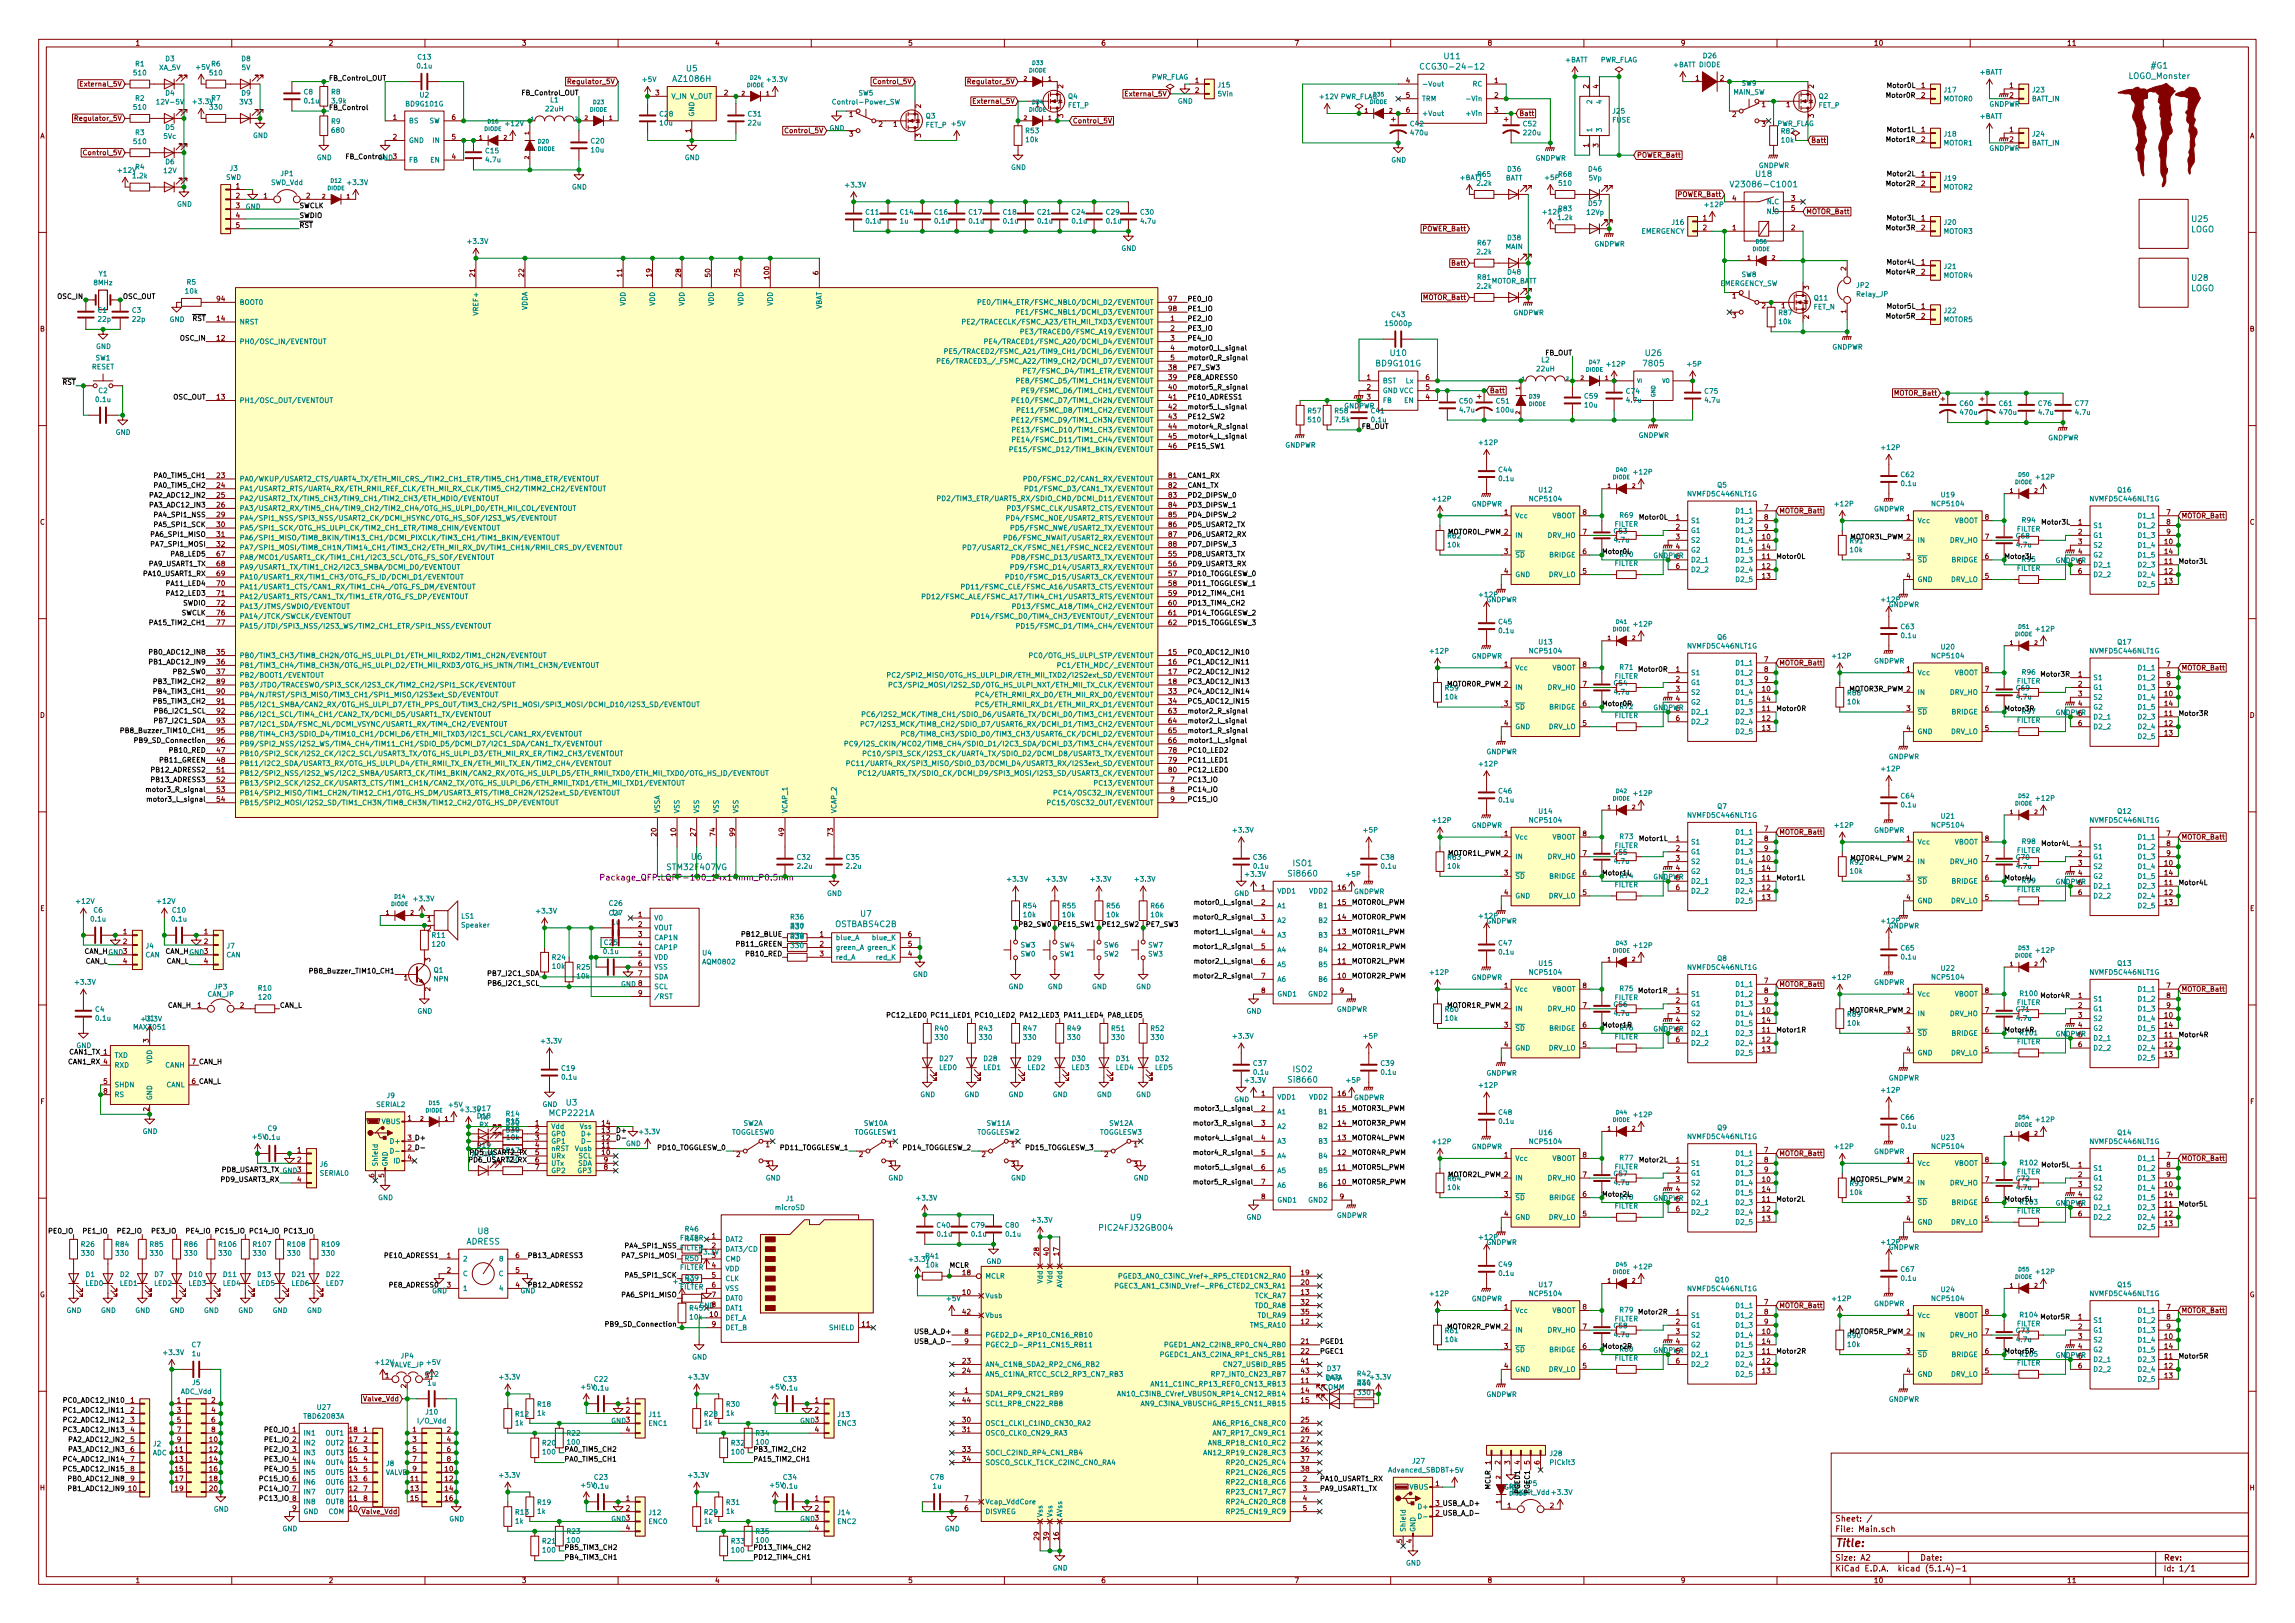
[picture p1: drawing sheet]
<svg xmlns="http://www.w3.org/2000/svg" width="594mm" height="420mm" viewBox="0 0 594 420" stroke-linecap="round" stroke-linejoin="round" font-family="sans-serif">
<defs><g id="words">
<text font-size="2.8" fill="#840000" x="475" y="400.4">Title:</text>
<g font-size="2.1" fill="#008484">
<text x="374" y="15.3">U11</text>
<text x="556.9" y="17.7">#G1</text>
<text x="174.5" y="21.2">AZ1086H</text>
<text x="177.7" y="18.5">U5</text>
<text x="369.3" y="18">CCG30-24-12</text>
<text x="551.1" y="20.4">LOGO_Monster</text>
<text x="454.6" y="45.8">U18</text>
<text x="449.4" y="48.5">V23086-C1001</text>
<text x="567.5" y="57.4">U25</text>
<text x="567.1" y="60.1">LOGO</text>
<text x="567.1" y="75.4">LOGO</text>
<text x="567.5" y="72.7">U28</text>
<text x="356.4" y="94.8">BD9G101G</text>
<text x="360" y="92.1">U10</text>
<text x="425.6" y="94.8">7805</text>
<text x="426.1" y="92.1">U26</text>
<text x="173" y="225.2">STM32F407VG</text>
<text x="179" y="222.5">U6</text>
<text x="333.8" y="226.9">Si8660</text>
<text x="334.8" y="224.2">ISO1</text>
<text x="216.3" y="240">OSTBABS4C2B</text>
<text x="222.8" y="237.3">U7</text>
<text x="333.8" y="280.3">Si8660</text>
<text x="334.8" y="277.6">ISO2</text>
<text x="146.6" y="286.2">U3</text>
<text x="142.5" y="288.9">MCP2221A</text>
<text x="292.7" y="315.9">U9</text>
<text x="120.7" y="322.2">ADRESS</text>
<text x="123.7" y="319.5">U8</text>
<text x="285.3" y="318.6">PIC24FJ32GB004</text>
</g>
<text font-size="2.1" fill="#008400" x="157.9" y="227.9">Package_QFP:LQFP-100_14x14mm_P0.5mm</text>
<g font-size="2.1" fill="#840000">
<text x="475" y="393.9">Sheet: /</text>
<text x="475" y="396.6">File: Main.sch</text>
<text x="475" y="406.8">KiCad E.D.A. kicad (5.1.4)-1</text>
<text x="475" y="404">Size: A2</text>
<text x="497" y="404">Date:</text>
<text x="560" y="404">Rev:</text>
<text x="560" y="406.8">Id: 1/1</text>
</g>
<g font-size="1.8" fill="#840000">
<text x="35" y="11.8">1</text>
<text x="85" y="11.8">2</text>
<text x="135" y="11.8">3</text>
<text x="185" y="11.8">4</text>
<text x="235" y="11.8">5</text>
<text x="285" y="11.8">6</text>
<text x="335" y="11.8">7</text>
<text x="385" y="11.8">8</text>
<text x="435" y="11.8">9</text>
<text x="485" y="11.8">10</text>
<text x="535" y="11.8">11</text>
<text x="21.5" y="22.4">External_5V</text>
<text x="147.8" y="21.8">Regulator_5V</text>
<text x="226.6" y="21.8">Control_5V</text>
<text x="251.3" y="21.8">Regulator_5V</text>
<text x="275.2" y="22.9" transform="rotate(-90 275.2 22.9)">2</text>
<text x="309.4" y="21.5">1</text>
<text x="364" y="21.5">4</text>
<text x="386.9" y="21.5">1</text>
<text x="411.2" y="22.9" transform="rotate(-90 411.2 22.9)">2</text>
<text x="413.8" y="22.9" transform="rotate(-90 413.8 22.9)">4</text>
<text x="438.9" y="20.9">1</text>
<text x="445.3" y="20.9">2</text>
<text x="469.5" y="22.9" transform="rotate(-90 469.5 22.9)">2</text>
<text x="497.4" y="22.8">1</text>
<text x="520.2" y="22.8">1</text>
<text x="169.7" y="24.7">3</text>
<text x="187.5" y="24.7">2</text>
<text x="238.4" y="28" transform="rotate(-90 238.4 28)">2</text>
<text x="252.6" y="26.8">External_5V</text>
<text x="292" y="24.9">External_5V</text>
<text x="309.4" y="24">2</text>
<text x="364" y="25.3">5</text>
<text x="364" y="29.1">6</text>
<text x="386.9" y="25.3">2</text>
<text x="386.9" y="29.1">3</text>
<text x="456.1" y="27.7">1</text>
<text x="462.4" y="27.7">1</text>
<text x="497.4" y="25.3">2</text>
<text x="520.2" y="25.3">2</text>
<text x="10.4" y="35.8">A</text>
<text x="20.2" y="31.3">Regulator_5V</text>
<text x="101.8" y="31">1</text>
<text x="117" y="31">6</text>
<text x="178.8" y="34.3" transform="rotate(-90 178.8 34.3)">1</text>
<text x="203.8" y="34.5">Control_5V</text>
<text x="219.9" y="30.3">1</text>
<text x="219.9" y="35.3">3</text>
<text x="227.5" y="32.8">2</text>
<text x="231.3" y="32.8">1</text>
<text x="238.4" y="35.6" transform="rotate(-90 238.4 35.6)">3</text>
<text x="275.2" y="30.5" transform="rotate(-90 275.2 30.5)">3</text>
<text x="277.6" y="31.9">Control_5V</text>
<text x="393.2" y="30">Batt</text>
<text x="448.5" y="30.3">2</text>
<text x="456.1" y="32.8">3</text>
<text x="469.5" y="30.5" transform="rotate(-90 469.5 30.5)">3</text>
<text x="497.4" y="34.2">1</text>
<text x="520.2" y="34.2">1</text>
<text x="582.4" y="35.8">A</text>
<text x="22.2" y="40.2">Control_5V</text>
<text x="101.8" y="36.1">2</text>
<text x="117" y="41.2">4</text>
<text x="117" y="36.1">5</text>
<text x="411.2" y="38.1" transform="rotate(-90 411.2 38.1)">1</text>
<text x="413.8" y="38.1" transform="rotate(-90 413.8 38.1)">3</text>
<text x="423.7" y="40.8">POWER_Batt</text>
<text x="468.8" y="37">Batt</text>
<text x="497.4" y="36.7">2</text>
<text x="520.2" y="36.7">2</text>
<text x="497.4" y="45.6">1</text>
<text x="61.1" y="48.8">1</text>
<text x="61.1" y="51.4">2</text>
<text x="61.1" y="53.9">3</text>
<text x="68.3" y="51.4">1</text>
<text x="79.3" y="51.4">2</text>
<text x="434.5" y="51">POWER_Batt</text>
<text x="448.5" y="52">4</text>
<text x="463.7" y="52">3</text>
<text x="497.4" y="48.2">2</text>
<text x="61.1" y="56.4">4</text>
<text x="61.1" y="59">5</text>
<text x="368.5" y="59.9">POWER_Batt</text>
<text x="440.8" y="57.1">1</text>
<text x="440.8" y="59.6">2</text>
<text x="448.5" y="59.6">1</text>
<text x="463.7" y="59.6">2</text>
<text x="463.7" y="54.5">5</text>
<text x="467.5" y="55.4">MOTOR_Batt</text>
<text x="497.4" y="57.1">1</text>
<text x="497.4" y="59.6">2</text>
<text x="122.9" y="71.6" transform="rotate(-90 122.9 71.6)">21</text>
<text x="135.6" y="71.6" transform="rotate(-90 135.6 71.6)">22</text>
<text x="161" y="71.6" transform="rotate(-90 161 71.6)">11</text>
<text x="168.7" y="71.6" transform="rotate(-90 168.7 71.6)">19</text>
<text x="176.3" y="71.6" transform="rotate(-90 176.3 71.6)">28</text>
<text x="183.9" y="71.6" transform="rotate(-90 183.9 71.6)">50</text>
<text x="191.5" y="71.6" transform="rotate(-90 191.5 71.6)">75</text>
<text x="211.8" y="71.1" transform="rotate(-90 211.8 71.1)">6</text>
<text x="376.1" y="68.7">Batt</text>
<text x="477.9" y="70" transform="rotate(-90 477.9 70)">2</text>
<text x="497.4" y="68.5">1</text>
<text x="497.4" y="71">2</text>
<text x="199.1" y="72.1" transform="rotate(-90 199.1 72.1)">100</text>
<text x="368.6" y="77.6">MOTOR_Batt</text>
<text x="448.5" y="77.3">1</text>
<text x="468.2" y="74.9" transform="rotate(-90 468.2 74.9)">3</text>
<text x="56.2" y="83.1">14</text>
<text x="56.2" y="78">94</text>
<text x="302.6" y="78">97</text>
<text x="302.6" y="80.6">98</text>
<text x="303" y="83.1">1</text>
<text x="448.5" y="82.3">3</text>
<text x="456.1" y="79.8">2</text>
<text x="461.2" y="79.8">1</text>
<text x="468.2" y="82.6" transform="rotate(-90 468.2 82.6)">2</text>
<text x="477.9" y="81.1" transform="rotate(-90 477.9 81.1)">1</text>
<text x="497.4" y="79.9">1</text>
<text x="497.4" y="82.5">2</text>
<text x="10.4" y="85.8">B</text>
<text x="56.2" y="88.2">12</text>
<text x="303" y="85.6">2</text>
<text x="303" y="88.2">3</text>
<text x="582.4" y="85.8">B</text>
<text x="302.6" y="95.8">38</text>
<text x="303" y="90.7">4</text>
<text x="303" y="93.3">5</text>
<text x="302.6" y="98.3">39</text>
<text x="302.6" y="100.9">40</text>
<text x="353.8" y="98.3">1</text>
<text x="353.8" y="100.9">2</text>
<text x="369.1" y="100.9">5</text>
<text x="369.1" y="98.3">6</text>
<text x="385.6" y="101.8">Batt</text>
<text x="56.2" y="103.4">13</text>
<text x="302.6" y="103.4">41</text>
<text x="302.6" y="106">42</text>
<text x="353.8" y="103.4">3</text>
<text x="369.1" y="103.4">4</text>
<text x="490.5" y="102.4">MOTOR_Batt</text>
<text x="302.6" y="108.5">43</text>
<text x="302.6" y="111">44</text>
<text x="302.6" y="113.6">45</text>
<text x="302.6" y="116.1">46</text>
<text x="56.2" y="123.7">23</text>
<text x="302.6" y="123.7">81</text>
<text x="56.2" y="126.3">24</text>
<text x="56.2" y="128.8">25</text>
<text x="56.2" y="131.4">26</text>
<text x="302.6" y="126.3">82</text>
<text x="302.6" y="128.8">83</text>
<text x="302.6" y="131.4">84</text>
<text x="456.7" y="132">7</text>
<text x="10.4" y="135.8">C</text>
<text x="56.2" y="133.9">29</text>
<text x="56.2" y="136.4">30</text>
<text x="302.6" y="133.9">85</text>
<text x="302.6" y="136.4">86</text>
<text x="389.4" y="133.3">1</text>
<text x="409.7" y="133.3">8</text>
<text x="433.9" y="134.5">1</text>
<text x="433.9" y="137.1">2</text>
<text x="456.7" y="134.5">8</text>
<text x="456.7" y="137.1">9</text>
<text x="460.5" y="132.9">MOTOR_Batt</text>
<text x="493.5" y="134.5">1</text>
<text x="513.9" y="134.5">8</text>
<text x="538" y="135.8">1</text>
<text x="560.9" y="133.3">7</text>
<text x="560.9" y="135.8">8</text>
<text x="564.7" y="134.2">MOTOR_Batt</text>
<text x="582.4" y="135.8">C</text>
<text x="56.2" y="139">31</text>
<text x="56.2" y="141.5">32</text>
<text x="302.6" y="139">87</text>
<text x="302.6" y="141.5">88</text>
<text x="389.4" y="143.4">3</text>
<text x="409.7" y="143.4">6</text>
<text x="409.7" y="138.3">7</text>
<text x="433.9" y="139.6">3</text>
<text x="433.9" y="142.2">4</text>
<text x="456.2" y="139.6">10</text>
<text x="456.2" y="142.2">14</text>
<text x="513.9" y="139.6">7</text>
<text x="538" y="138.3">2</text>
<text x="538" y="140.9">3</text>
<text x="538" y="143.4">4</text>
<text x="560.4" y="140.9">10</text>
<text x="560.4" y="143.4">14</text>
<text x="560.9" y="138.3">9</text>
<text x="56.2" y="144.1">67</text>
<text x="56.2" y="146.6">68</text>
<text x="56.2" y="149.1">69</text>
<text x="302.6" y="144.1">55</text>
<text x="302.6" y="146.6">56</text>
<text x="302.6" y="149.1">57</text>
<text x="389.4" y="148.5">4</text>
<text x="409.7" y="148.5">5</text>
<text x="433.9" y="144.7">5</text>
<text x="433.9" y="147.2">6</text>
<text x="456.2" y="144.7">11</text>
<text x="456.2" y="147.2">12</text>
<text x="456.2" y="149.8">13</text>
<text x="493.5" y="144.7">3</text>
<text x="493.5" y="149.8">4</text>
<text x="513.9" y="149.8">5</text>
<text x="513.9" y="144.7">6</text>
<text x="538" y="146">5</text>
<text x="538" y="148.5">6</text>
<text x="560.4" y="146">11</text>
<text x="560.4" y="148.5">12</text>
<text x="56.2" y="151.7">70</text>
<text x="56.2" y="154.2">71</text>
<text x="302.6" y="151.7">58</text>
<text x="302.6" y="154.2">59</text>
<text x="560.4" y="151">13</text>
<text x="56.2" y="156.8">72</text>
<text x="56.2" y="159.3">76</text>
<text x="56.2" y="161.8">77</text>
<text x="302.6" y="156.8">60</text>
<text x="302.6" y="159.3">61</text>
<text x="302.6" y="161.8">62</text>
<text x="56.2" y="169.5">35</text>
<text x="56.2" y="172">36</text>
<text x="302.6" y="169.5">15</text>
<text x="302.6" y="172">16</text>
<text x="389.4" y="172.6">1</text>
<text x="409.7" y="172.6">8</text>
<text x="433.9" y="173.9">1</text>
<text x="456.7" y="171.4">7</text>
<text x="456.7" y="173.9">8</text>
<text x="460.5" y="172.3">MOTOR_Batt</text>
<text x="493.5" y="173.9">1</text>
<text x="513.9" y="173.9">8</text>
<text x="560.9" y="172.6">7</text>
<text x="564.7" y="173.5">MOTOR_Batt</text>
<text x="56.2" y="174.5">37</text>
<text x="56.2" y="177.1">89</text>
<text x="56.2" y="179.6">90</text>
<text x="302.6" y="174.5">17</text>
<text x="302.6" y="177.1">18</text>
<text x="302.6" y="179.6">33</text>
<text x="409.7" y="177.7">7</text>
<text x="433.9" y="176.4">2</text>
<text x="433.9" y="179">3</text>
<text x="456.2" y="179">10</text>
<text x="456.7" y="176.4">9</text>
<text x="513.9" y="179">7</text>
<text x="538" y="175.2">1</text>
<text x="538" y="177.7">2</text>
<text x="560.9" y="175.2">8</text>
<text x="560.9" y="177.7">9</text>
<text x="10.4" y="185.8">D</text>
<text x="56.2" y="182.2">91</text>
<text x="56.2" y="184.7">92</text>
<text x="302.6" y="182.2">34</text>
<text x="302.6" y="184.7">63</text>
<text x="389.4" y="182.8">3</text>
<text x="409.7" y="182.8">6</text>
<text x="433.9" y="181.5">4</text>
<text x="433.9" y="184.1">5</text>
<text x="456.2" y="184.1">11</text>
<text x="456.2" y="181.5">14</text>
<text x="493.5" y="184.1">3</text>
<text x="513.9" y="184.1">6</text>
<text x="538" y="180.3">3</text>
<text x="538" y="182.8">4</text>
<text x="538" y="185.3">5</text>
<text x="560.4" y="180.3">10</text>
<text x="560.4" y="185.3">11</text>
<text x="560.4" y="182.8">14</text>
<text x="582.4" y="185.8">D</text>
<text x="56.2" y="187.2">93</text>
<text x="56.2" y="189.8">95</text>
<text x="302.6" y="187.2">64</text>
<text x="302.6" y="189.8">65</text>
<text x="389.4" y="187.9">4</text>
<text x="409.7" y="187.9">5</text>
<text x="433.9" y="186.6">6</text>
<text x="456.2" y="186.6">12</text>
<text x="456.2" y="189.1">13</text>
<text x="493.5" y="189.1">4</text>
<text x="513.9" y="189.1">5</text>
<text x="538" y="187.9">6</text>
<text x="560.4" y="187.9">12</text>
<text x="560.4" y="190.4">13</text>
<text x="56.2" y="194.9">47</text>
<text x="56.2" y="197.4">48</text>
<text x="56.2" y="192.3">96</text>
<text x="302.6" y="192.3">66</text>
<text x="302.6" y="194.9">78</text>
<text x="302.6" y="197.4">79</text>
<text x="56.2" y="199.9">51</text>
<text x="56.2" y="202.5">52</text>
<text x="302.6" y="199.9">80</text>
<text x="303" y="202.5">7</text>
<text x="56.2" y="205">53</text>
<text x="56.2" y="207.6">54</text>
<text x="303" y="205">8</text>
<text x="303" y="207.6">9</text>
<text x="456.7" y="215.2">7</text>
<text x="169.9" y="216.4" transform="rotate(-90 169.9 216.4)">20</text>
<text x="175" y="216.4" transform="rotate(-90 175 216.4)">10</text>
<text x="180.1" y="216.4" transform="rotate(-90 180.1 216.4)">27</text>
<text x="185.2" y="216.4" transform="rotate(-90 185.2 216.4)">74</text>
<text x="190.2" y="216.4" transform="rotate(-90 190.2 216.4)">99</text>
<text x="202.9" y="216.4" transform="rotate(-90 202.9 216.4)">49</text>
<text x="215.6" y="216.4" transform="rotate(-90 215.6 216.4)">73</text>
<text x="389.4" y="216.5">1</text>
<text x="409.7" y="221.5">7</text>
<text x="409.7" y="216.5">8</text>
<text x="433.9" y="217.7">1</text>
<text x="433.9" y="220.3">2</text>
<text x="456.7" y="217.7">8</text>
<text x="456.7" y="220.3">9</text>
<text x="460.5" y="216.1">MOTOR_Batt</text>
<text x="493.5" y="217.7">1</text>
<text x="513.9" y="217.7">8</text>
<text x="538" y="219">1</text>
<text x="538" y="221.5">2</text>
<text x="560.9" y="216.5">7</text>
<text x="560.9" y="219">8</text>
<text x="560.9" y="221.5">9</text>
<text x="564.7" y="217.3">MOTOR_Batt</text>
<text x="389.4" y="226.6">3</text>
<text x="409.7" y="226.6">6</text>
<text x="433.9" y="222.8">3</text>
<text x="433.9" y="225.3">4</text>
<text x="433.9" y="227.9">5</text>
<text x="456.2" y="222.8">10</text>
<text x="456.2" y="227.9">11</text>
<text x="456.2" y="225.3">14</text>
<text x="493.5" y="227.9">3</text>
<text x="513.9" y="227.9">6</text>
<text x="513.9" y="222.8">7</text>
<text x="538" y="224.1">3</text>
<text x="538" y="226.6">4</text>
<text x="560.4" y="224.1">10</text>
<text x="560.4" y="226.6">14</text>
<text x="326.5" y="230.4">1</text>
<text x="346.4" y="230.4">16</text>
<text x="389.4" y="231.7">4</text>
<text x="409.7" y="231.7">5</text>
<text x="433.9" y="230.4">6</text>
<text x="456.2" y="230.4">12</text>
<text x="456.2" y="233">13</text>
<text x="493.5" y="233">4</text>
<text x="513.9" y="233">5</text>
<text x="538" y="229.2">5</text>
<text x="538" y="231.7">6</text>
<text x="560.4" y="229.2">11</text>
<text x="560.4" y="231.7">12</text>
<text x="10.4" y="235.8">E</text>
<text x="110.6" y="238.5">1</text>
<text x="165.3" y="237.4">1</text>
<text x="165.3" y="239.9">2</text>
<text x="326.5" y="234.2">2</text>
<text x="326.5" y="238">3</text>
<text x="346.4" y="238">14</text>
<text x="346.4" y="234.2">15</text>
<text x="560.4" y="234.2">13</text>
<text x="582.4" y="235.8">E</text>
<text x="31.9" y="241.9">1</text>
<text x="31.9" y="244.4">2</text>
<text x="52.9" y="241.9">1</text>
<text x="52.9" y="244.4">2</text>
<text x="110.6" y="241.1">2</text>
<text x="165.3" y="242.5">3</text>
<text x="165.3" y="245">4</text>
<text x="212.2" y="242.5">1</text>
<text x="212.2" y="245">2</text>
<text x="235.1" y="245">5</text>
<text x="235.1" y="242.5">6</text>
<text x="326.5" y="241.9">4</text>
<text x="326.5" y="245.7">5</text>
<text x="346.4" y="245.7">12</text>
<text x="346.4" y="241.9">13</text>
<text x="31.9" y="249.5">4</text>
<text x="52.9" y="249.5">4</text>
<text x="111.4" y="248.9" transform="rotate(-90 111.4 248.9)">3</text>
<text x="165.3" y="247.6">5</text>
<text x="165.3" y="250.1">6</text>
<text x="212.2" y="247.6">3</text>
<text x="235.1" y="247.6">4</text>
<text x="326.5" y="249.5">6</text>
<text x="346.4" y="249.5">11</text>
<text x="104.6" y="253.8">1</text>
<text x="111.4" y="256.6" transform="rotate(-90 111.4 256.6)">2</text>
<text x="160.7" y="255.4">GND 8</text>
<text x="165.3" y="252.6">7</text>
<text x="165.3" y="257.7">9</text>
<text x="326.5" y="253.3">7</text>
<text x="326.5" y="257.1">8</text>
<text x="346.4" y="253.3">10</text>
<text x="346.9" y="257.1">9</text>
<text x="389.4" y="255.8">1</text>
<text x="409.7" y="255.8">8</text>
<text x="433.9" y="257.1">1</text>
<text x="456.7" y="254.6">7</text>
<text x="456.7" y="257.1">8</text>
<text x="460.5" y="255.4">MOTOR_Batt</text>
<text x="493.5" y="257.1">1</text>
<text x="513.9" y="257.1">8</text>
<text x="560.9" y="255.8">7</text>
<text x="564.7" y="256.7">MOTOR_Batt</text>
<text x="51.1" y="260.9">1</text>
<text x="62.2" y="260.9">2</text>
<text x="409.7" y="260.9">7</text>
<text x="433.9" y="259.6">2</text>
<text x="433.9" y="262.2">3</text>
<text x="456.2" y="262.2">10</text>
<text x="456.7" y="259.6">9</text>
<text x="513.9" y="262.2">7</text>
<text x="538" y="258.4">1</text>
<text x="538" y="260.9">2</text>
<text x="538" y="263.4">3</text>
<text x="560.4" y="263.4">10</text>
<text x="560.9" y="258.4">8</text>
<text x="560.9" y="260.9">9</text>
<text x="34.8" y="266.5">MAX3051</text>
<text x="38.5" y="269.9" transform="rotate(-90 38.5 269.9)">3</text>
<text x="389.4" y="266">3</text>
<text x="409.7" y="266">6</text>
<text x="433.9" y="264.7">4</text>
<text x="433.9" y="267.3">5</text>
<text x="433.9" y="269.8">6</text>
<text x="456.2" y="267.3">11</text>
<text x="456.2" y="269.8">12</text>
<text x="456.2" y="264.7">14</text>
<text x="493.5" y="267.3">3</text>
<text x="513.9" y="267.3">6</text>
<text x="538" y="266">4</text>
<text x="538" y="268.5">5</text>
<text x="560.4" y="268.5">11</text>
<text x="560.4" y="266">14</text>
<text x="389.4" y="271.1">4</text>
<text x="409.7" y="271.1">5</text>
<text x="456.2" y="272.3">13</text>
<text x="493.5" y="272.3">4</text>
<text x="513.9" y="272.3">5</text>
<text x="538" y="271.1">6</text>
<text x="560.4" y="271.1">12</text>
<text x="560.4" y="273.6">13</text>
<text x="26.8" y="280.6">5</text>
<text x="10.5" y="285.8">F</text>
<text x="26.8" y="283.1">8</text>
<text x="38.5" y="287.7" transform="rotate(-90 38.5 287.7)">2</text>
<text x="326.5" y="283.8">1</text>
<text x="326.5" y="287.6">2</text>
<text x="346.4" y="287.6">15</text>
<text x="346.4" y="283.8">16</text>
<text x="582.5" y="285.8">F</text>
<text x="105.6" y="290.1">1</text>
<text x="138.6" y="291.4">1</text>
<text x="138.6" y="293.3">2</text>
<text x="155.9" y="293.3">13</text>
<text x="155.9" y="291.4">14</text>
<text x="326.5" y="291.4">3</text>
<text x="346.4" y="291.4">14</text>
<text x="77" y="298.4">1</text>
<text x="123.6" y="297.1">D19</text>
<text x="138.6" y="295.2">3</text>
<text x="138.6" y="297.1">4</text>
<text x="138.6" y="299">5</text>
<text x="155.9" y="299">10</text>
<text x="155.9" y="297.1">11</text>
<text x="155.9" y="295.2">12</text>
<text x="190.7" y="299.5">2</text>
<text x="198.3" y="297">1</text>
<text x="222.4" y="299.5">2</text>
<text x="230" y="297">1</text>
<text x="254.2" y="299.5">2</text>
<text x="261.8" y="297">1</text>
<text x="285.9" y="299.5">2</text>
<text x="293.5" y="297">1</text>
<text x="326.5" y="295.2">4</text>
<text x="326.5" y="299">5</text>
<text x="346.4" y="299">12</text>
<text x="346.4" y="295.2">13</text>
<text x="389.4" y="299.6">1</text>
<text x="409.7" y="299.6">8</text>
<text x="456.7" y="298.4">7</text>
<text x="460.5" y="299.3">MOTOR_Batt</text>
<text x="560.9" y="299.6">7</text>
<text x="77" y="300.9">2</text>
<text x="77" y="306">4</text>
<text x="96.9" y="304.8" transform="rotate(-90 96.9 304.8)">6</text>
<text x="99.4" y="304.8" transform="rotate(-90 99.4 304.8)">5</text>
<text x="105.6" y="300.3">4</text>
<text x="138.6" y="300.9">6</text>
<text x="138.6" y="302.8">7</text>
<text x="156.4" y="302.8">8</text>
<text x="156.4" y="300.9">9</text>
<text x="198.3" y="302">3</text>
<text x="230" y="302">3</text>
<text x="261.8" y="302">3</text>
<text x="293.5" y="302">3</text>
<text x="326.5" y="302.8">6</text>
<text x="346.4" y="302.8">11</text>
<text x="409.7" y="304.7">7</text>
<text x="433.9" y="300.9">1</text>
<text x="433.9" y="303.4">2</text>
<text x="433.9" y="306">3</text>
<text x="456.2" y="306">10</text>
<text x="456.7" y="300.9">8</text>
<text x="456.7" y="303.4">9</text>
<text x="493.5" y="300.9">1</text>
<text x="513.9" y="306">7</text>
<text x="513.9" y="300.9">8</text>
<text x="538" y="302.2">1</text>
<text x="538" y="304.7">2</text>
<text x="560.9" y="302.2">8</text>
<text x="560.9" y="304.7">9</text>
<text x="564.7" y="300.5">MOTOR_Batt</text>
<text x="326.5" y="306.6">7</text>
<text x="326.5" y="310.4">8</text>
<text x="346.4" y="306.6">10</text>
<text x="346.9" y="310.4">9</text>
<text x="389.4" y="309.8">3</text>
<text x="409.7" y="309.8">6</text>
<text x="433.9" y="308.5">4</text>
<text x="433.9" y="311.1">5</text>
<text x="456.2" y="311.1">11</text>
<text x="456.2" y="308.5">14</text>
<text x="493.5" y="311.1">3</text>
<text x="513.9" y="311.1">6</text>
<text x="538" y="307.3">3</text>
<text x="538" y="309.8">4</text>
<text x="560.4" y="307.3">10</text>
<text x="560.4" y="309.8">14</text>
<text x="389.4" y="314.9">4</text>
<text x="409.7" y="314.9">5</text>
<text x="433.9" y="313.6">6</text>
<text x="456.2" y="313.6">12</text>
<text x="456.2" y="316.1">13</text>
<text x="493.5" y="316.1">4</text>
<text x="513.9" y="316.1">5</text>
<text x="538" y="312.3">5</text>
<text x="538" y="314.9">6</text>
<text x="560.4" y="312.3">11</text>
<text x="560.4" y="314.9">12</text>
<text x="560.4" y="317.4">13</text>
<text x="184.3" y="320.6">1</text>
<text x="184.3" y="323.1">2</text>
<text x="115.7" y="325.7">1</text>
<text x="115.7" y="329.5">2</text>
<text x="133.5" y="329.5">5</text>
<text x="133.5" y="325.7">6</text>
<text x="184.3" y="325.7">3</text>
<text x="184.3" y="328.2">4</text>
<text x="269" y="325" transform="rotate(-90 269 325)">28</text>
<text x="271.5" y="325" transform="rotate(-90 271.5 325)">40</text>
<text x="274.1" y="325" transform="rotate(-90 274.1 325)">17</text>
<text x="10.3" y="335.8">G</text>
<text x="115.7" y="333.3">3</text>
<text x="133.5" y="333.3">4</text>
<text x="174.6" y="332.4">+3.3V</text>
<text x="184.3" y="330.8">5</text>
<text x="184.3" y="333.3">6</text>
<text x="184.3" y="335.8">7</text>
<text x="249.2" y="335.2">10</text>
<text x="249.2" y="330.1">18</text>
<text x="336.9" y="335.2">13</text>
<text x="336.9" y="330.1">19</text>
<text x="336.9" y="332.7">20</text>
<text x="582.3" y="335.8">G</text>
<text x="183.8" y="340.9">10</text>
<text x="249.2" y="340.3">42</text>
<text x="336.9" y="337.7">32</text>
<text x="336.9" y="340.3">35</text>
<text x="389.4" y="339">1</text>
<text x="409.7" y="339">8</text>
<text x="433.9" y="340.3">1</text>
<text x="456.7" y="337.7">7</text>
<text x="456.7" y="340.3">8</text>
<text x="460.5" y="338.6">MOTOR_Batt</text>
<text x="493.5" y="340.3">1</text>
<text x="513.9" y="340.3">8</text>
<text x="538" y="341.5">1</text>
<text x="560.9" y="339">7</text>
<text x="560.9" y="341.5">8</text>
<text x="564.7" y="339.9">MOTOR_Batt</text>
<text x="184.3" y="343.5">9</text>
<text x="223.2" y="343.5">11</text>
<text x="249.7" y="345.4">8</text>
<text x="249.7" y="347.9">9</text>
<text x="336.9" y="342.8">12</text>
<text x="336.9" y="347.9">21</text>
<text x="409.7" y="344.1">7</text>
<text x="433.9" y="342.8">2</text>
<text x="433.9" y="345.4">3</text>
<text x="433.9" y="347.9">4</text>
<text x="456.2" y="345.4">10</text>
<text x="456.2" y="347.9">14</text>
<text x="456.7" y="342.8">9</text>
<text x="513.9" y="345.4">7</text>
<text x="538" y="344.1">2</text>
<text x="538" y="346.6">3</text>
<text x="560.4" y="346.6">10</text>
<text x="560.9" y="344.1">9</text>
<text x="249.2" y="353">23</text>
<text x="336.9" y="350.4">22</text>
<text x="336.9" y="353">41</text>
<text x="389.4" y="349.2">3</text>
<text x="409.7" y="349.2">6</text>
<text x="433.9" y="350.4">5</text>
<text x="433.9" y="353">6</text>
<text x="456.2" y="350.4">11</text>
<text x="456.2" y="353">12</text>
<text x="493.5" y="350.4">3</text>
<text x="513.9" y="350.4">6</text>
<text x="538" y="349.2">4</text>
<text x="538" y="351.7">5</text>
<text x="560.4" y="351.7">11</text>
<text x="560.4" y="349.2">14</text>
<text x="99.8" y="356.8">1</text>
<text x="105.2" y="359.3" transform="rotate(-90 105.2 359.3)">2</text>
<text x="110.1" y="356.8">3</text>
<text x="249.2" y="355.5">24</text>
<text x="336.9" y="358.1">11</text>
<text x="336.9" y="355.5">43</text>
<text x="342.5" y="359.8">COMM</text>
<text x="389.4" y="354.2">4</text>
<text x="409.7" y="354.2">5</text>
<text x="456.2" y="355.5">13</text>
<text x="493.5" y="355.5">4</text>
<text x="513.9" y="355.5">5</text>
<text x="538" y="354.2">6</text>
<text x="560.4" y="354.2">12</text>
<text x="560.4" y="356.8">13</text>
<text x="33.8" y="363.1">1</text>
<text x="33.8" y="365.7">2</text>
<text x="45.9" y="363.1">1</text>
<text x="45.9" y="365.7">3</text>
<text x="54.8" y="363.1">2</text>
<text x="54.8" y="365.7">4</text>
<text x="94.4" y="362.8">Valve_Vdd</text>
<text x="162.1" y="363.1">1</text>
<text x="162.1" y="365.7">2</text>
<text x="211" y="363.1">1</text>
<text x="211" y="365.7">2</text>
<text x="249.2" y="363.1">44</text>
<text x="249.7" y="360.6">1</text>
<text x="336.9" y="360.6">14</text>
<text x="336.9" y="363.1">15</text>
<text x="33.8" y="368.2">3</text>
<text x="33.8" y="370.8">4</text>
<text x="45.9" y="368.2">5</text>
<text x="45.9" y="370.8">7</text>
<text x="54.8" y="368.2">6</text>
<text x="54.8" y="370.8">8</text>
<text x="90.5" y="370.8">18</text>
<text x="94.1" y="370.8">1</text>
<text x="106.8" y="370.8">1</text>
<text x="115.7" y="370.8">2</text>
<text x="158.2" y="368.5">GND3</text>
<text x="162.1" y="370.8">4</text>
<text x="211" y="370.8">4</text>
<text x="249.2" y="368.2">30</text>
<text x="249.2" y="370.8">31</text>
<text x="336.9" y="368.2">25</text>
<text x="336.9" y="370.8">26</text>
<text x="33.8" y="373.3">5</text>
<text x="33.8" y="375.8">6</text>
<text x="45.4" y="375.8">11</text>
<text x="45.9" y="373.3">9</text>
<text x="54.3" y="373.3">10</text>
<text x="54.3" y="375.8">12</text>
<text x="90.5" y="375.8">16</text>
<text x="90.5" y="373.3">17</text>
<text x="94.1" y="373.3">2</text>
<text x="94.1" y="375.8">3</text>
<text x="106.8" y="373.3">3</text>
<text x="106.8" y="375.8">5</text>
<text x="115.7" y="373.3">4</text>
<text x="115.7" y="375.8">6</text>
<text x="249.2" y="375.8">33</text>
<text x="336.9" y="373.3">27</text>
<text x="336.9" y="375.8">36</text>
<text x="33.8" y="378.4">7</text>
<text x="33.8" y="380.9">8</text>
<text x="33.8" y="383.5">9</text>
<text x="45.4" y="378.4">13</text>
<text x="45.4" y="380.9">15</text>
<text x="45.4" y="383.5">17</text>
<text x="54.3" y="378.4">14</text>
<text x="54.3" y="380.9">16</text>
<text x="54.3" y="383.5">18</text>
<text x="90.5" y="383.5">13</text>
<text x="90.5" y="380.9">14</text>
<text x="90.5" y="378.4">15</text>
<text x="94.1" y="378.4">4</text>
<text x="94.1" y="380.9">5</text>
<text x="94.1" y="383.5">6</text>
<text x="106.3" y="383.5">11</text>
<text x="106.8" y="378.4">7</text>
<text x="106.8" y="380.9">9</text>
<text x="115.2" y="380.9">10</text>
<text x="115.2" y="383.5">12</text>
<text x="115.7" y="378.4">8</text>
<text x="249.2" y="378.4">34</text>
<text x="336.9" y="378.4">37</text>
<text x="336.9" y="380.9">38</text>
<text x="337.3" y="383.5">2</text>
<text x="385.8" y="379.1" transform="rotate(-90 385.8 379.1)">1</text>
<text x="388.4" y="379.1" transform="rotate(-90 388.4 379.1)">2</text>
<text x="390.9" y="379.1" transform="rotate(-90 390.9 379.1)">3</text>
<text x="393.4" y="379.1" transform="rotate(-90 393.4 379.1)">4</text>
<text x="396" y="379.1" transform="rotate(-90 396 379.1)">5</text>
<text x="398.5" y="379.1" transform="rotate(-90 398.5 379.1)">6</text>
<text x="10.4" y="385.8">H</text>
<text x="33.3" y="386">10</text>
<text x="45.4" y="386">19</text>
<text x="54.3" y="386">20</text>
<text x="90.5" y="388.5">11</text>
<text x="90.5" y="386">12</text>
<text x="94.1" y="386">7</text>
<text x="94.1" y="388.5">8</text>
<text x="106.3" y="386">13</text>
<text x="106.3" y="388.5">15</text>
<text x="115.2" y="386">14</text>
<text x="115.2" y="388.5">16</text>
<text x="162.1" y="388.5">1</text>
<text x="211" y="388.5">1</text>
<text x="249.7" y="388.5">7</text>
<text x="337.3" y="386">3</text>
<text x="337.3" y="388.5">4</text>
<text x="371.6" y="384.7">1</text>
<text x="582.4" y="385.8">H</text>
<text x="75.7" y="391.1">9</text>
<text x="90.5" y="391.1">10</text>
<text x="93.5" y="392">Valve_Vdd</text>
<text x="162.1" y="391.1">2</text>
<text x="211" y="391.1">2</text>
<text x="249.7" y="391.1">6</text>
<text x="337.3" y="391.1">5</text>
<text x="390.2" y="390.4">1</text>
<text x="401.3" y="390.4">2</text>
<text x="162.1" y="396.2">4</text>
<text x="211" y="396.2">4</text>
<text x="269" y="398.6" transform="rotate(-90 269 398.6)">29</text>
<text x="271.5" y="398.6" transform="rotate(-90 271.5 398.6)">39</text>
<text x="274.1" y="398.6" transform="rotate(-90 274.1 398.6)">16</text>
<text x="363" y="399.4" transform="rotate(-90 363 399.4)">5</text>
<text x="365.5" y="399.4" transform="rotate(-90 365.5 399.4)">4</text>
<text x="35" y="409.8">1</text>
<text x="85" y="409.8">2</text>
<text x="135" y="409.8">3</text>
<text x="185" y="409.8">4</text>
<text x="235" y="409.8">5</text>
<text x="285" y="409.8">6</text>
<text x="335" y="409.8">7</text>
<text x="385" y="409.8">8</text>
<text x="435" y="409.8">9</text>
<text x="485" y="409.8">10</text>
<text x="535" y="409.8">11</text>
</g>
<g font-size="1.8" fill="#008484">
<text x="35.1" y="17.2">R1</text>
<text x="42.9" y="15.8">D3</text>
<text x="54.8" y="17.2">R6</text>
<text x="62.6" y="15.8">D8</text>
<text x="108.1" y="17.7">0.1u</text>
<text x="108.2" y="15.4">C13</text>
<text x="405.2" y="16.1">+BATT</text>
<text x="414.1" y="16.1">PWR_FLAG</text>
<text x="433.1" y="17.4">+BATT DIODE</text>
<text x="441" y="15.1">D26</text>
<text x="34.7" y="19.5">510</text>
<text x="41.2" y="18.2">XA_5V</text>
<text x="50.9" y="18.1">+5V</text>
<text x="54.4" y="19.5">510</text>
<text x="62.6" y="18.2">5V</text>
<text x="166.4" y="21.2">+5V</text>
<text x="198.7" y="21.2">+3.3V</text>
<text x="297.9" y="20.6">PWR_FLAG</text>
<text x="315.4" y="22.6">J15</text>
<text x="368" y="22.4">-Vout</text>
<text x="381.2" y="22.4">RC</text>
<text x="450.8" y="22.2">SW9</text>
<text x="503.3" y="23.9">J17</text>
<text x="512.5" y="19.3">+BATT</text>
<text x="526.2" y="23.9">J23</text>
<text x="34.7" y="28.4">510</text>
<text x="35.1" y="26.1">R2</text>
<text x="41" y="27">12V-5V</text>
<text x="42.9" y="24.7">D4</text>
<text x="50.1" y="26.9">+3.3V</text>
<text x="54.4" y="28.4">330</text>
<text x="54.8" y="26.1">R7</text>
<text x="62.1" y="27">3V3</text>
<text x="62.6" y="24.7">D9</text>
<text x="78.7" y="24.5">C8</text>
<text x="78.9" y="26.8">0.1u</text>
<text x="85.8" y="24.5">R8</text>
<text x="86" y="26.8">3.9k</text>
<text x="105.2" y="27.6">BD9G101G</text>
<text x="108.7" y="25.2">U2</text>
<text x="141.4" y="28.8">22uH</text>
<text x="142.5" y="26.5">L1</text>
<text x="173.7" y="25.6">V_IN V_OUT</text>
<text x="216.2" y="27">Control-Power_SW</text>
<text x="222.2" y="24.7">SW5</text>
<text x="268.1" y="27.7">1</text>
<text x="276.4" y="27.9">FET_P</text>
<text x="276.6" y="25.6">Q4</text>
<text x="304.9" y="26.8">GND</text>
<text x="315.3" y="25">5Vin</text>
<text x="341.8" y="25.7">+12V PWR_FLAG</text>
<text x="368" y="26.2">TRM</text>
<text x="380.4" y="26.2">-Vin</text>
<text x="412.1" y="26.7" transform="rotate(-90 412.1 26.7)">2</text>
<text x="414.7" y="26.7" transform="rotate(-90 414.7 26.7)">4</text>
<text x="417.6" y="29.4">J25</text>
<text x="448.6" y="24.5">MAIN_SW</text>
<text x="470.7" y="27.9">FET_P</text>
<text x="470.9" y="25.6">Q2</text>
<text x="503.1" y="26.2">MOTOR0</text>
<text x="514.9" y="27.6">GNDPWR</text>
<text x="525.8" y="26.2">BATT_IN</text>
<text x="35.1" y="35">R3</text>
<text x="42.4" y="35.9">5Vc</text>
<text x="42.9" y="33.6">D5</text>
<text x="65.5" y="35.7">GND</text>
<text x="85.8" y="32.1">R9</text>
<text x="86" y="34.4">680</text>
<text x="105.8" y="31.9">BS</text>
<text x="111.1" y="31.9">SW</text>
<text x="131" y="32.7">+12V</text>
<text x="170.8" y="30.2">C28</text>
<text x="170.9" y="32.5">10u</text>
<text x="179.7" y="30.3" transform="rotate(-90 179.7 30.3)">GND</text>
<text x="193.7" y="30.2">C31</text>
<text x="193.8" y="32.5">22u</text>
<text x="214.7" y="33.8">GND</text>
<text x="239.6" y="33">FET_P</text>
<text x="239.7" y="30.7">Q3</text>
<text x="246.4" y="32.7">+5V</text>
<text x="265.6" y="34.5">R53</text>
<text x="365.2" y="32.7">C42</text>
<text x="365.3" y="35">470u</text>
<text x="368" y="30">+Vout</text>
<text x="380" y="30">+Vin</text>
<text x="394.4" y="32.7">C52</text>
<text x="394.5" y="35">220u</text>
<text x="412.1" y="34.3" transform="rotate(-90 412.1 34.3)">1</text>
<text x="414.7" y="34.3" transform="rotate(-90 414.7 34.3)">3</text>
<text x="417.4" y="31.7">FUSE</text>
<text x="459.9" y="32.7">PWR_FLAG</text>
<text x="461.2" y="34.6">R82</text>
<text x="503.3" y="35.3">J18</text>
<text x="512.5" y="30.8">+BATT</text>
<text x="526.2" y="35.3">J24</text>
<text x="34.7" y="37.3">510</text>
<text x="82" y="41.4">GND</text>
<text x="105.8" y="37">GND</text>
<text x="112.1" y="37">IN</text>
<text x="125.8" y="39.7">C15</text>
<text x="153.1" y="37.2">C20</text>
<text x="153.1" y="39.5">10u</text>
<text x="177.2" y="41.4">GND</text>
<text x="265.6" y="36.8">10k</text>
<text x="397.4" y="41.6">GNDPWR</text>
<text x="461.2" y="36.9">10k</text>
<text x="503.1" y="37.7">MOTOR1</text>
<text x="514.9" y="39.1">GNDPWR</text>
<text x="525.8" y="37.7">BATT_IN</text>
<text x="30.7" y="44.7">+12V</text>
<text x="34.5" y="46.2">1.2k</text>
<text x="35.1" y="43.9">R4</text>
<text x="42.4" y="44.8">12V</text>
<text x="42.9" y="42.5">D6</text>
<text x="58.4" y="46.5">SWD</text>
<text x="59.5" y="44.2">J3</text>
<text x="70.1" y="47.9">SWD_Vdd</text>
<text x="72.7" y="45.6">JP1</text>
<text x="90.1" y="47.9">+3.3V</text>
<text x="105.8" y="42.1">FB</text>
<text x="111.5" y="42.1">EN</text>
<text x="125.9" y="42">4.7u</text>
<text x="261.7" y="44">GND</text>
<text x="360.1" y="42.1">GND</text>
<text x="377.9" y="46.6">+BATT</text>
<text x="382.5" y="45.8">R65</text>
<text x="389.6" y="46.7">BATT</text>
<text x="390.3" y="44.4">D36</text>
<text x="400.1" y="46.6">+5P</text>
<text x="403.5" y="45.8">R68</text>
<text x="411.3" y="44.4">D46</text>
<text x="411.3" y="46.7">5Vp</text>
<text x="455.2" y="43.5">GNDPWR</text>
<text x="503.3" y="46.8">J19</text>
<text x="45.8" y="53.5">GND</text>
<text x="148" y="49.1">GND</text>
<text x="219" y="48.5">+3.3V</text>
<text x="382.4" y="48.1">2.2k</text>
<text x="403.7" y="48.1">510</text>
<text x="411.3" y="53.3">D57</text>
<text x="441.5" y="53.6">+12P</text>
<text x="457.6" y="52.9">N.C</text>
<text x="503.1" y="49.1">MOTOR2</text>
<text x="63.6" y="54.1">GND</text>
<text x="224.2" y="55.6">C11</text>
<text x="224.3" y="57.9">0.1u</text>
<text x="233" y="57.9">1u</text>
<text x="233.1" y="55.6">C14</text>
<text x="242" y="55.6">C16</text>
<text x="242.1" y="57.9">0.1u</text>
<text x="250.9" y="55.6">C17</text>
<text x="251" y="57.9">0.1u</text>
<text x="259.7" y="55.6">C18</text>
<text x="259.9" y="57.9">0.1u</text>
<text x="268.6" y="55.6">C21</text>
<text x="268.8" y="57.9">0.1u</text>
<text x="277.5" y="55.6">C24</text>
<text x="277.6" y="57.9">0.1u</text>
<text x="286.4" y="55.6">C29</text>
<text x="286.5" y="57.9">0.1u</text>
<text x="295.3" y="55.6">C30</text>
<text x="295.4" y="57.9">4.7u</text>
<text x="399.6" y="55.5">+12P</text>
<text x="403.4" y="57">1.2k</text>
<text x="403.5" y="54.7">R83</text>
<text x="410.8" y="55.6">12Vp</text>
<text x="432.9" y="58.2">J16</text>
<text x="457.5" y="55.4">N.O</text>
<text x="503.3" y="58.2">J20</text>
<text x="121.2" y="63.1">+3.3V</text>
<text x="290.3" y="64.9">GND</text>
<text x="382.4" y="65.9">2.2k</text>
<text x="382.5" y="63.5">R67</text>
<text x="389.7" y="64.5">MAIN</text>
<text x="390.3" y="62.2">D38</text>
<text x="412.6" y="63.8">GNDPWR</text>
<text x="424.8" y="60.5">EMERGENCY</text>
<text x="503.1" y="60.5">MOTOR3</text>
<text x="25.6" y="71.5">Y1</text>
<text x="390.3" y="71.1">D48</text>
<text x="450.8" y="71.7">SW8</text>
<text x="503.1" y="71.9">MOTOR4</text>
<text x="503.3" y="69.6">J21</text>
<text x="24.4" y="73.8">8MHz</text>
<text x="48.1" y="76">10k</text>
<text x="48.4" y="73.7">R5</text>
<text x="382.4" y="74.7">2.2k</text>
<text x="382.5" y="72.4">R81</text>
<text x="385.8" y="73.4">MOTOR_BATT</text>
<text x="445.1" y="74">EMERGENCY_SW</text>
<text x="469.7" y="77.8">Q11</text>
<text x="480.6" y="74.5">JP2</text>
<text x="480.7" y="76.8">Relay_JP</text>
<text x="25.3" y="81">C1</text>
<text x="25.5" y="83.3">22p</text>
<text x="34.2" y="81">C3</text>
<text x="34.4" y="83.3">22p</text>
<text x="43.9" y="83.4">GND</text>
<text x="62" y="84">NRST</text>
<text x="62" y="78.9">BOOT0</text>
<text x="123.8" y="81.2" transform="rotate(-90 123.8 81.2)">VREF+</text>
<text x="136.5" y="80.5" transform="rotate(-90 136.5 80.5)">VDDA</text>
<text x="161.9" y="79.2" transform="rotate(-90 161.9 79.2)">VDD</text>
<text x="169.5" y="79.2" transform="rotate(-90 169.5 79.2)">VDD</text>
<text x="177.2" y="79.2" transform="rotate(-90 177.2 79.2)">VDD</text>
<text x="184.8" y="79.2" transform="rotate(-90 184.8 79.2)">VDD</text>
<text x="192.4" y="79.2" transform="rotate(-90 192.4 79.2)">VDD</text>
<text x="200" y="79.2" transform="rotate(-90 200 79.2)">VDD</text>
<text x="212.7" y="80.3" transform="rotate(-90 212.7 80.3)">VBAT</text>
<text x="252.3" y="84">PE2/TRACECLK/FSMC_A23/ETH_MII_TXD3/EVENTOUT</text>
<text x="256.8" y="78.9">PE0/TIM4_ETR/FSMC_NBL0/DCMI_D2/EVENTOUT</text>
<text x="265.9" y="81.4">PE1/FSMC_NBL1/DCMI_D3/EVENTOUT</text>
<text x="360.3" y="82.1">C43</text>
<text x="391.7" y="81.6">GNDPWR</text>
<text x="460.5" y="81.6">R87</text>
<text x="460.6" y="83.9">10k</text>
<text x="469.4" y="80.1">FET_N</text>
<text x="503.1" y="83.4">MOTOR5</text>
<text x="503.3" y="81.1">J22</text>
<text x="62" y="89.1">PH0/OSC_IN/EVENTOUT</text>
<text x="258.4" y="89.1">PE4/TRACED1/FSMC_A20/DCMI_D4/EVENTOUT</text>
<text x="266.7" y="86.5">PE3/TRACED0/FSMC_A19/EVENTOUT</text>
<text x="359" y="84.4">15000p</text>
<text x="23.7" y="95.6">RESET</text>
<text x="24.8" y="93.3">SW1</text>
<text x="24.8" y="90.3">GND</text>
<text x="247.4" y="94.1">PE6/TRACED3_/_FSMC_A22/TIM9_CH2/DCMI_D7/EVENTOUT</text>
<text x="249.4" y="91.6">PE5/TRACED2/FSMC_A21/TIM9_CH1/DCMI_D6/EVENTOUT</text>
<text x="399" y="93.8">L2</text>
<text x="416.1" y="94.9">+12P</text>
<text x="436.9" y="94.9">+5P</text>
<text x="474.2" y="90.5">GNDPWR</text>
<text x="25.6" y="101.8">C2</text>
<text x="266.2" y="99.2">PE8/FSMC_D5/TIM1_CH1N/EVENTOUT</text>
<text x="267.4" y="96.7">PE7/FSMC_D4/TIM1_ETR/EVENTOUT</text>
<text x="267.4" y="101.8">PE9/FSMC_D6/TIM1_CH1/EVENTOUT</text>
<text x="357.9" y="99.2">BST</text>
<text x="357.9" y="101.8">GND VCC</text>
<text x="364" y="99.2">Lx</text>
<text x="397.9" y="96.1">22uH</text>
<text x="421" y="101.9">C74</text>
<text x="441.4" y="101.9">C75</text>
<text x="24.9" y="104.1">0.1u</text>
<text x="62" y="104.3">PH1/OSC_OUT/EVENTOUT</text>
<text x="265.2" y="104.3">PE10/FSMC_D7/TIM1_CH2N/EVENTOUT</text>
<text x="266.5" y="106.8">PE11/FSMC_D8/TIM1_CH2/EVENTOUT</text>
<text x="338.6" y="107">R57</text>
<text x="345.6" y="107">R58</text>
<text x="347.9" y="105.7">GNDPWR</text>
<text x="355" y="107">C41</text>
<text x="357.9" y="104.3">FB</text>
<text x="363.6" y="104.3">EN</text>
<text x="377.9" y="104.5">C50</text>
<text x="378" y="106.8">4.7u</text>
<text x="387.4" y="104.5">C51</text>
<text x="387.6" y="106.8">100u</text>
<text x="410.2" y="103.2">C59</text>
<text x="410.3" y="105.5">10u</text>
<text x="421.2" y="104.2">4.7u</text>
<text x="441.5" y="104.2">4.7u</text>
<text x="507.4" y="105.1">C60</text>
<text x="507.6" y="107.4">470u</text>
<text x="517.6" y="105.1">C61</text>
<text x="517.7" y="107.4">470u</text>
<text x="527.7" y="105.1">C76</text>
<text x="527.8" y="107.4">4.7u</text>
<text x="537.2" y="105.1">C77</text>
<text x="537.4" y="107.4">4.7u</text>
<text x="29.9" y="112.6">GND</text>
<text x="265.2" y="109.4">PE12/FSMC_D9/TIM1_CH3N/EVENTOUT</text>
<text x="265.5" y="111.9">PE13/FSMC_D10/TIM1_CH3/EVENTOUT</text>
<text x="338.7" y="109.3">510</text>
<text x="345.7" y="109.3">7.5k</text>
<text x="355.1" y="109.3">0.1u</text>
<text x="424.1" y="113.4">GNDPWR</text>
<text x="530.1" y="114">GNDPWR</text>
<text x="264.7" y="117">PE15/FSMC_D12/TIM1_BKIN/EVENTOUT</text>
<text x="265.5" y="114.5">PE14/FSMC_D11/TIM1_CH4/EVENTOUT</text>
<text x="332.6" y="115.9">GNDPWR</text>
<text x="383.1" y="115.2">+12P</text>
<text x="487.2" y="116.5">+12P</text>
<text x="62" y="124.6">PA0/WKUP/USART2_CTS/UART4_TX/ETH_MII_CRS_/TIM2_CH1_ETR/TIM5_CH1/TIM8_ETR/EVENTOUT</text>
<text x="267.6" y="124.6">PD0/FSMC_D2/CAN1_RX/EVENTOUT</text>
<text x="388" y="122.2">C44</text>
<text x="388.1" y="124.6">0.1u</text>
<text x="423.1" y="122.8">+12P</text>
<text x="492.2" y="123.5">C62</text>
<text x="492.3" y="125.8">0.1u</text>
<text x="527.3" y="124.1">+12P</text>
<text x="62" y="127.2">PA1/USART2_RTS/UART4_RX/ETH_RMII_REF_CLK/ETH_MII_RX_CLK/TIM5_CH2/TIMM2_CH2/EVENTOUT</text>
<text x="62" y="129.7">PA2/USART2_TX/TIM5_CH3/TIM9_CH1/TIM2_CH3/ETH_MDIO/EVENTOUT</text>
<text x="247.2" y="129.7">PD2/TIM3_ETR/UART5_RX/SDIO_CMD/DCMI_D11/EVENTOUT</text>
<text x="267.8" y="127.2">PD1/FSMC_D3/CAN1_TX/EVENTOUT</text>
<text x="371" y="129.8">+12P</text>
<text x="380.9" y="131.1">GNDPWR</text>
<text x="396.2" y="129.8">NCP5104</text>
<text x="398.4" y="127.5">U12</text>
<text x="437.1" y="128.5">NVMFD5C446NLT1G</text>
<text x="444.6" y="126.2">Q5</text>
<text x="475.2" y="131.1">+12P</text>
<text x="500.4" y="131.1">NCP5104</text>
<text x="502.6" y="128.7">U19</text>
<text x="541.3" y="129.8">NVMFD5C446NLT1G</text>
<text x="548.2" y="127.5">Q16</text>
<text x="62" y="132.2">PA3/USART2_RX/TIM5_CH4/TIM9_CH2/TIM2_CH4/OTG_HS_ULPI_D0/ETH_MII_COL/EVENTOUT</text>
<text x="62" y="134.8">PA4/SPI1_NSS/SPI3_NSS/USART2_CK/DCMI_HSYNC/OTG_HS_SOF/I2S3_WS/EVENTOUT</text>
<text x="62" y="137.3">PA5/SPI1_SCK/OTG_HS_ULPI_CK/TIM2_CH1_ETR/TIM8_CHIN/EVENTOUT</text>
<text x="262.7" y="134.8">PD4/FSMC_NOE/USART2_RTS/EVENTOUT</text>
<text x="262.9" y="132.2">PD3/FSMC_CLK/USART2_CTS/EVENTOUT</text>
<text x="263.7" y="137.3">PD5/FSMC_NWE/USART2_TX/EVENTOUT</text>
<text x="392.2" y="134.2">Vcc</text>
<text x="401.6" y="134.2">VBOOT</text>
<text x="417.9" y="136.3">FILTER</text>
<text x="419.4" y="134">R69</text>
<text x="437.6" y="135.4">S1</text>
<text x="437.6" y="138">G1</text>
<text x="449.7" y="132.9">D1_1</text>
<text x="449.7" y="135.4">D1_2</text>
<text x="449.7" y="138">D1_3</text>
<text x="485" y="132.4">GNDPWR</text>
<text x="496.3" y="135.4">Vcc</text>
<text x="505.8" y="135.4">VBOOT</text>
<text x="522" y="137.6">FILTER</text>
<text x="523.5" y="135.3">R94</text>
<text x="541.8" y="136.7">S1</text>
<text x="553.8" y="134.2">D1_1</text>
<text x="553.8" y="136.7">D1_2</text>
<text x="62" y="139.9">PA6/SPI1_MISO/TIM8_BKIN/TIM13_CH1/DCMI_PIXCLK/TIM3_CH1/TIM1_BKIN/EVENTOUT</text>
<text x="62" y="142.4">PA7/SPI1_MOSI/TIM8_CH1N/TIM14_CH1/TIM3_CH2/ETH_MII_RX_DV/TIM1_CH1N/RMII_CRS_DV/EVENTOUT</text>
<text x="252.9" y="142.4">PD7/USART2_CK/FSMC_NE1/FSMC_NCE2/EVENTOUT</text>
<text x="261.8" y="139.9">PD6/FSMC_NWAIT/USART2_RX/EVENTOUT</text>
<text x="374.8" y="139.4">R62</text>
<text x="374.9" y="141.7">10k</text>
<text x="392.2" y="139.2">IN</text>
<text x="400.6" y="139.2">DRV_HO</text>
<text x="417.9" y="138.1">C53</text>
<text x="418" y="140.4">4.7u</text>
<text x="437.6" y="140.5">S2</text>
<text x="437.6" y="143">G2</text>
<text x="449.7" y="140.5">D1_4</text>
<text x="449.7" y="143">D1_5</text>
<text x="478.9" y="140.7">R91</text>
<text x="479" y="143">10k</text>
<text x="496.3" y="140.5">IN</text>
<text x="504.7" y="140.5">DRV_HO</text>
<text x="522" y="139.4">C68</text>
<text x="522.1" y="141.7">4.7u</text>
<text x="541.8" y="139.2">G1</text>
<text x="541.8" y="141.8">S2</text>
<text x="553.8" y="141.8">D1_4</text>
<text x="553.8" y="139.2">D1_3</text>
<text x="62" y="144.9">PA8/MCO1/USART1_CK/TIM1_CH1/I2C3_SCL/OTG_FS_SOF/EVENTOUT</text>
<text x="62" y="147.5">PA9/USART1_TX/TIM1_CH2/I2C3_SMBA/DCMI_D0/EVENTOUT</text>
<text x="264.4" y="147.5">PD9/FSMC_D14/USART3_RX/EVENTOUT</text>
<text x="264.6" y="144.9">PD8/FSMC_D13/USART3_TX/EVENTOUT</text>
<text x="392.2" y="144.3">SD</text>
<text x="392.2" y="149.4">GND</text>
<text x="400.8" y="149.4">DRV_LO</text>
<text x="401" y="144.3">BRIDGE</text>
<text x="417.9" y="146.5">FILTER</text>
<text x="427.9" y="144.5">GNDPWR</text>
<text x="437.6" y="145.6">D2_1</text>
<text x="437.6" y="148.1">D2_2</text>
<text x="449.7" y="145.6">D2_3</text>
<text x="449.7" y="148.1">D2_4</text>
<text x="496.3" y="145.6">SD</text>
<text x="505.2" y="145.6">BRIDGE</text>
<text x="522" y="147.8">FILTER</text>
<text x="532" y="145.7">GNDPWR</text>
<text x="541.8" y="144.3">G2</text>
<text x="541.8" y="146.9">D2_1</text>
<text x="541.8" y="149.4">D2_2</text>
<text x="553.8" y="146.9">D2_3</text>
<text x="553.8" y="149.4">D2_4</text>
<text x="553.8" y="144.3">D1_5</text>
<text x="62" y="150">PA10/USART1_RX/TIM1_CH3/OTG_FS_ID/DCMI_D1/EVENTOUT</text>
<text x="62" y="152.6">PA11/USART1_CTS/CAN1_RX/TIM1_CH4_/OTG_FS_DM/EVENTOUT</text>
<text x="62" y="155.1">PA12/USART1_RTS/CAN1_TX/TIM1_ETR/OTG_FS_DP/EVENTOUT</text>
<text x="243.3" y="155.1">PD12/FSMC_ALE/FSMC_A17/TIM4_CH1/USART3_RTS/EVENTOUT</text>
<text x="252.3" y="152.6">PD11/FSMC_CLE/FSMC_A16/USART3_CTS/EVENTOUT</text>
<text x="263.3" y="150">PD10/FSMC_D15/USART3_CK/EVENTOUT</text>
<text x="383.1" y="154.6">+12P</text>
<text x="384.7" y="155.9">GNDPWR</text>
<text x="449.7" y="150.7">D2_5</text>
<text x="487.2" y="155.8">+12P</text>
<text x="496.3" y="150.7">GND</text>
<text x="504.9" y="150.7">DRV_LO</text>
<text x="553.8" y="151.9">D2_5</text>
<text x="62" y="157.6">PA13/JTMS/SWDIO/EVENTOUT</text>
<text x="62" y="160.2">PA14/JTCK/SWCLK/EVENTOUT</text>
<text x="255.3" y="160.2">PD14/FSMC_D0/TIM4_CH3/EVENTOUT/_EVENTOUT</text>
<text x="265.4" y="157.6">PD13/FSMC_A18/TIM4_CH2/EVENTOUT</text>
<text x="388" y="161.6">C45</text>
<text x="488.8" y="157.2">GNDPWR</text>
<text x="62" y="162.7">PA15/JTDI/SPI3_NSS/I2S3_WS/TIM2_CH1_ETR/SPI1_NSS/EVENTOUT</text>
<text x="266.4" y="162.7">PD15/FSMC_D1/TIM4_CH4/EVENTOUT</text>
<text x="388.1" y="163.9">0.1u</text>
<text x="398.4" y="166.8">U13</text>
<text x="423.1" y="162.2">+12P</text>
<text x="437.1" y="167.9">NVMFD5C446NLT1G</text>
<text x="444.6" y="165.6">Q6</text>
<text x="492.2" y="162.9">C63</text>
<text x="492.3" y="165.2">0.1u</text>
<text x="527.3" y="163.5">+12P</text>
<text x="548.2" y="166.8">Q17</text>
<text x="62" y="170.3">PB0/TIM3_CH3/TIM8_CH2N/OTG_HS_ULPI_D1/ETH_MII_RXD2/TIM1_CH2N/EVENTOUT</text>
<text x="62" y="172.9">PB1/TIM3_CH4/TIM8_CH3N/OTG_HS_ULPI_D2/ETH_MII_RXD3/OTG_HS_INTN/TIM1_CH3N/EVENTOUT</text>
<text x="267.9" y="170.3">PC0/OTG_HS_ULPI_STP/EVENTOUT</text>
<text x="275.1" y="172.9">PC1/ETH_MDC/_EVENTOUT</text>
<text x="370.4" y="169.2">+12P</text>
<text x="380.9" y="170.5">GNDPWR</text>
<text x="392.2" y="173.5">Vcc</text>
<text x="396.2" y="169.2">NCP5104</text>
<text x="401.6" y="173.5">VBOOT</text>
<text x="419.4" y="173.4">R71</text>
<text x="449.7" y="172.3">D1_1</text>
<text x="474.5" y="170.5">+12P</text>
<text x="485" y="171.8">GNDPWR</text>
<text x="500.4" y="170.4">NCP5104</text>
<text x="502.6" y="168.1">U20</text>
<text x="541.3" y="169.2">NVMFD5C446NLT1G</text>
<text x="553.8" y="173.5">D1_1</text>
<text x="62" y="175.4">PB2/BOOT1/EVENTOUT</text>
<text x="62" y="178">PB3/JTDO/TRACESWO/SPI3_SCK/I2S3_CK/TIM2_CH2/SPI1_SCK/EVENTOUT</text>
<text x="235.1" y="178">PC3/SPI2_MOSI/I2S2_SD/OTG_HS_ULPI_NXT/ETH_MII_TX_CLK/EVENTOUT</text>
<text x="235.4" y="175.4">PC2/SPI2_MISO/OTG_HS_ULPI_DIR/ETH_MII_TXD2/I2S2ext_SD/EVENTOUT</text>
<text x="374.2" y="178.8">R59</text>
<text x="392.2" y="178.6">IN</text>
<text x="400.6" y="178.6">DRV_HO</text>
<text x="417.9" y="177.5">C54</text>
<text x="417.9" y="175.7">FILTER</text>
<text x="418" y="179.8">4.7u</text>
<text x="437.6" y="174.8">S1</text>
<text x="437.6" y="177.3">G1</text>
<text x="437.6" y="179.9">S2</text>
<text x="449.7" y="179.9">D1_4</text>
<text x="449.7" y="174.8">D1_2</text>
<text x="449.7" y="177.3">D1_3</text>
<text x="496.3" y="174.8">Vcc</text>
<text x="496.3" y="179.9">IN</text>
<text x="504.7" y="179.9">DRV_HO</text>
<text x="505.8" y="174.8">VBOOT</text>
<text x="522" y="178.8">C69</text>
<text x="522" y="177">FILTER</text>
<text x="523.5" y="174.7">R96</text>
<text x="541.8" y="176.1">S1</text>
<text x="541.8" y="178.6">G1</text>
<text x="553.8" y="176.1">D1_2</text>
<text x="553.8" y="178.6">D1_3</text>
<text x="62" y="180.5">PB4/NJTRST/SPI3_MISO/TIM3_CH1/SPI1_MISO/I2S3ext_SD/EVENTOUT</text>
<text x="62" y="183">PB5/I2C1_SMBA/CAN2_RX/OTG_HS_ULPI_D7/ETH_PPS_OUT/TIM3_CH2/SPI1_MOSI/SPI3_MOSI/DCMI_D10/I2S3_SD/EVENTOUT</text>
<text x="62" y="185.6">PB6/I2C1_SCL/TIM4_CH1/CAN2_TX/DCMI_D5/USART1_TX/EVENTOUT</text>
<text x="230.8" y="185.6">PC6/I2S2_MCK/TIM8_CH1/SDIO_D6/USART6_TX/DCMI_D0/TIM3_CH1/EVENTOUT</text>
<text x="255.5" y="180.5">PC4/ETH_RMII_RX_D0/ETH_MII_RX_D0/EVENTOUT</text>
<text x="255.5" y="183">PC5/ETH_RMII_RX_D1/ETH_MII_RX_D1/EVENTOUT</text>
<text x="374.2" y="181.1">10k</text>
<text x="392.2" y="183.7">SD</text>
<text x="401" y="183.7">BRIDGE</text>
<text x="417.9" y="185.9">FILTER</text>
<text x="427.9" y="183.8">GNDPWR</text>
<text x="437.6" y="182.4">G2</text>
<text x="437.6" y="185">D2_1</text>
<text x="449.7" y="185">D2_3</text>
<text x="449.7" y="182.4">D1_5</text>
<text x="478.3" y="180">R88</text>
<text x="478.4" y="182.3">10k</text>
<text x="496.3" y="185">SD</text>
<text x="505.2" y="185">BRIDGE</text>
<text x="522.1" y="181.1">4.7u</text>
<text x="532" y="185.1">GNDPWR</text>
<text x="541.8" y="181.1">S2</text>
<text x="541.8" y="183.7">G2</text>
<text x="553.8" y="181.1">D1_4</text>
<text x="553.8" y="183.7">D1_5</text>
<text x="62" y="188.1">PB7/I2C1_SDA/FSMC_NL/DCMI_VSYNC/USART1_RX/TIM4_CH2/EVENTOUT</text>
<text x="62" y="190.7">PB8/TIM4_CH3/SDIO_D4/TIM10_CH1/DCMI_D6/ETH_MII_TXD3/I2C1_SCL/CAN1_RX/EVENTOUT</text>
<text x="230.6" y="188.1">PC7/I2S3_MCK/TIM8_CH2/SDIO_D7/USART6_RX/DCMI_D1/TIM3_CH2/EVENTOUT</text>
<text x="239.6" y="190.7">PC8/TIM8_CH3/SDIO_D0/TIM3_CH3/USART6_CK/DCMI_D2/EVENTOUT</text>
<text x="392.2" y="188.8">GND</text>
<text x="400.8" y="188.8">DRV_LO</text>
<text x="437.6" y="187.5">D2_2</text>
<text x="449.7" y="187.5">D2_4</text>
<text x="449.7" y="190">D2_5</text>
<text x="496.3" y="190">GND</text>
<text x="504.9" y="190">DRV_LO</text>
<text x="522" y="187.1">FILTER</text>
<text x="541.8" y="186.2">D2_1</text>
<text x="541.8" y="188.8">D2_2</text>
<text x="553.8" y="186.2">D2_3</text>
<text x="553.8" y="188.8">D2_4</text>
<text x="553.8" y="191.3">D2_5</text>
<text x="62" y="195.7">PB10/SPI2_SCK/I2S2_CK/I2C2_SCL/USART3_TX/OTG_HS_ULPI_D3/ETH_MII_RX_ER/TIM2_CH3/EVENTOUT</text>
<text x="62" y="193.2">PB9/SPI2_NSS/I2S2_WS/TIM4_CH4/TIM11_CH1/SDIO_D5/DCMI_D7/I2C1_SDA/CAN1_TX/EVENTOUT</text>
<text x="227.7" y="193.2">PC9/I2S_CKIN/MCO2/TIM8_CH4/SDIO_D1/I2C3_SDA/DCMI_D3/TIM3_CH4/EVENTOUT</text>
<text x="230.7" y="195.7">PC10/SPI3_SCK/I2S3_CK/UART4_TX/SDIO_D2/DCMI_D8/USART3_TX/EVENTOUT</text>
<text x="384.7" y="195.3">GNDPWR</text>
<text x="488.8" y="196.5">GNDPWR</text>
<text x="62" y="198.3">PB11/I2C2_SDA/USART3_RX/OTG_HS_ULPI_D4/ETH_RMII_TX_EN/ETH_MII_TX_EN/TIM2_CH4/EVENTOUT</text>
<text x="62" y="200.8">PB12/SPI2_NSS/I2S2_WS/I2C2_SMBA/USART3_CK/TIM1_BKIN/CAN2_RX/OTG_HS_ULPI_D5/ETH_RMII_TXD0/ETH_MII_TXD0/OTG_HS_ID/EVENTOUT</text>
<text x="62" y="203.4">PB13/SPI2_SCK/I2S2_CK/USART3_CTS/TIM1_CH1N/CAN2_TX/OTG_HS_ULPI_D6/ETH_RMII_TXD1/ETH_MII_TXD1/EVENTOUT</text>
<text x="227.1" y="198.3">PC11/UART4_RX/SPI3_MISO/SDIO_D3/DCMI_D4/USART3_RX/I2S3ext_SD/EVENTOUT</text>
<text x="229.4" y="200.8">PC12/UART5_TX/SDIO_CK/DCMI_D9/SPI3_MOSI/I2S3_SD/USART3_CK/EVENTOUT</text>
<text x="284.1" y="203.4">PC13/EVENTOUT</text>
<text x="383.1" y="198.4">+12P</text>
<text x="487.2" y="199.7">+12P</text>
<text x="62" y="205.9">PB14/SPI2_MISO/TIM1_CH2N/TIM12_CH1/OTG_HS_DM/USART3_RTS/TIM8_CH2N/I2S2ext_SD/EVENTOUT</text>
<text x="62" y="208.4">PB15/SPI2_MOSI/I2S2_SD/TIM1_CH3N/TIM8_CH3N/TIM12_CH2/OTG_HS_DP/EVENTOUT</text>
<text x="273.2" y="208.4">PC15/OSC32_OUT/EVENTOUT</text>
<text x="275.1" y="205.9">PC14/OSC32_IN/EVENTOUT</text>
<text x="388" y="205.4">C46</text>
<text x="388.1" y="207.7">0.1u</text>
<text x="423.1" y="206">+12P</text>
<text x="444.6" y="209.4">Q7</text>
<text x="492.2" y="206.7">C64</text>
<text x="492.3" y="209">0.1u</text>
<text x="527.3" y="207.3">+12P</text>
<text x="170.8" y="210.6" transform="rotate(-90 170.8 210.6)">VSSA</text>
<text x="175.9" y="210.6" transform="rotate(-90 175.9 210.6)">VSS</text>
<text x="181" y="210.6" transform="rotate(-90 181 210.6)">VSS</text>
<text x="186.1" y="210.6" transform="rotate(-90 186.1 210.6)">VSS</text>
<text x="191.1" y="210.6" transform="rotate(-90 191.1 210.6)">VSS</text>
<text x="203.8" y="210.6" transform="rotate(-90 203.8 210.6)">VCAP_1</text>
<text x="216.5" y="210.6" transform="rotate(-90 216.5 210.6)">VCAP_2</text>
<text x="319.4" y="215.5">+3.3V</text>
<text x="353.1" y="215.5">+5P</text>
<text x="371" y="213">+12P</text>
<text x="380.9" y="214.3">GNDPWR</text>
<text x="396.2" y="213">NCP5104</text>
<text x="398.4" y="210.7">U14</text>
<text x="437.1" y="211.7">NVMFD5C446NLT1G</text>
<text x="475.2" y="214.3">+12P</text>
<text x="485" y="215.6">GNDPWR</text>
<text x="500.4" y="214.2">NCP5104</text>
<text x="502.6" y="211.9">U21</text>
<text x="541.3" y="213">NVMFD5C446NLT1G</text>
<text x="548.2" y="210.7">Q12</text>
<text x="392.2" y="217.3">Vcc</text>
<text x="401.6" y="217.3">VBOOT</text>
<text x="417.9" y="221.3">C55</text>
<text x="417.9" y="219.5">FILTER</text>
<text x="419.4" y="217.2">R73</text>
<text x="437.6" y="218.6">S1</text>
<text x="437.6" y="221.1">G1</text>
<text x="449.7" y="216.1">D1_1</text>
<text x="449.7" y="218.6">D1_2</text>
<text x="449.7" y="221.1">D1_3</text>
<text x="496.3" y="218.6">Vcc</text>
<text x="505.8" y="218.6">VBOOT</text>
<text x="522" y="220.8">FILTER</text>
<text x="523.5" y="218.5">R98</text>
<text x="541.8" y="219.9">S1</text>
<text x="553.8" y="217.3">D1_1</text>
<text x="553.8" y="219.9">D1_2</text>
<text x="206.4" y="222.6">C32</text>
<text x="206.5" y="224.9">2.2u</text>
<text x="219.1" y="222.6">C35</text>
<text x="219.2" y="224.9">2.2u</text>
<text x="322.5" y="227">+3.3V</text>
<text x="324.5" y="222.6">C36</text>
<text x="324.6" y="224.9">0.1u</text>
<text x="348.7" y="227">+5P</text>
<text x="357.5" y="222.6">C38</text>
<text x="357.7" y="224.9">0.1u</text>
<text x="374.8" y="222.6">R63</text>
<text x="374.9" y="224.9">10k</text>
<text x="392.2" y="222.4">IN</text>
<text x="392.2" y="227.5">SD</text>
<text x="400.6" y="222.4">DRV_HO</text>
<text x="401" y="227.5">BRIDGE</text>
<text x="418" y="223.6">4.7u</text>
<text x="427.9" y="227.7">GNDPWR</text>
<text x="437.6" y="223.7">S2</text>
<text x="437.6" y="226.2">G2</text>
<text x="449.7" y="223.7">D1_4</text>
<text x="449.7" y="226.2">D1_5</text>
<text x="478.9" y="223.8">R92</text>
<text x="479" y="226.2">10k</text>
<text x="496.3" y="223.7">IN</text>
<text x="504.7" y="223.7">DRV_HO</text>
<text x="522" y="222.6">C70</text>
<text x="522.1" y="224.9">4.7u</text>
<text x="541.8" y="222.4">G1</text>
<text x="541.8" y="225">S2</text>
<text x="541.8" y="227.5">G2</text>
<text x="553.8" y="225">D1_4</text>
<text x="553.8" y="222.4">D1_3</text>
<text x="553.8" y="227.5">D1_5</text>
<text x="19.9" y="234">+12V</text>
<text x="40.8" y="234">+12V</text>
<text x="107.3" y="233.3">+3.3V</text>
<text x="214.1" y="231.9">GND</text>
<text x="260.9" y="228.2">+3.3V</text>
<text x="271.1" y="228.2">+3.3V</text>
<text x="282.5" y="228.2">+3.3V</text>
<text x="294" y="228.2">+3.3V</text>
<text x="319.5" y="231.9">GND</text>
<text x="330.6" y="231.3">VDD1</text>
<text x="339.1" y="231.3">VDD2</text>
<text x="350.4" y="231.5">GNDPWR</text>
<text x="392.2" y="232.6">GND</text>
<text x="400.8" y="232.6">DRV_LO</text>
<text x="417.9" y="229.7">FILTER</text>
<text x="437.6" y="228.8">D2_1</text>
<text x="437.6" y="231.3">D2_2</text>
<text x="449.7" y="228.8">D2_3</text>
<text x="449.7" y="231.3">D2_4</text>
<text x="449.7" y="233.8">D2_5</text>
<text x="496.3" y="228.8">SD</text>
<text x="496.3" y="233.8">GND</text>
<text x="504.9" y="233.8">DRV_LO</text>
<text x="505.2" y="228.8">BRIDGE</text>
<text x="522" y="231">FILTER</text>
<text x="532" y="228.9">GNDPWR</text>
<text x="541.8" y="230">D2_1</text>
<text x="541.8" y="232.6">D2_2</text>
<text x="553.8" y="230">D2_3</text>
<text x="553.8" y="232.6">D2_4</text>
<text x="23.6" y="238.6">0.1u</text>
<text x="24.3" y="236.3">C6</text>
<text x="44.6" y="238.6">0.1u</text>
<text x="44.7" y="236.3">C10</text>
<text x="119.4" y="237.8">LS1</text>
<text x="139" y="236.5">+3.3V</text>
<text x="157.8" y="237">C27</text>
<text x="157.8" y="234.5">C26</text>
<text x="158.4" y="239.3">1u</text>
<text x="158.4" y="236.8">1u</text>
<text x="169.3" y="238.3">V0</text>
<text x="204.7" y="238">R36</text>
<text x="264.9" y="235.1">R54</text>
<text x="265" y="237.5">10k</text>
<text x="275.1" y="235.1">R55</text>
<text x="275.2" y="237.5">10k</text>
<text x="286.5" y="235.1">R56</text>
<text x="286.6" y="237.5">10k</text>
<text x="298" y="235.1">R66</text>
<text x="298" y="237.5">10k</text>
<text x="330.6" y="235.1">A1</text>
<text x="330.6" y="238.9">A2</text>
<text x="341.5" y="238.9">B2</text>
<text x="341.5" y="235.1">B1</text>
<text x="383.1" y="237.8">+12P</text>
<text x="384.7" y="239.1">GNDPWR</text>
<text x="487.2" y="239">+12P</text>
<text x="553.8" y="235.1">D2_5</text>
<text x="37.8" y="245.5">J4</text>
<text x="58.8" y="245.5">J7</text>
<text x="111.9" y="242.8">R11</text>
<text x="112" y="245.1">120</text>
<text x="119.6" y="240.1">Speaker</text>
<text x="156.5" y="244.6">C25</text>
<text x="169.3" y="240.8">VOUT</text>
<text x="169.3" y="243.4">CAP1N</text>
<text x="169.3" y="245.9">CAP1P</text>
<text x="204.9" y="240.4">330</text>
<text x="204.9" y="242.9">330</text>
<text x="204.9" y="245.4">330</text>
<text x="216.3" y="243.4">blue_A</text>
<text x="216.3" y="245.9">green_A</text>
<text x="224.9" y="245.9">green_K</text>
<text x="226.1" y="243.4">blue_K</text>
<text x="264.2" y="245.3">SW3</text>
<text x="274.4" y="245.3">SW4</text>
<text x="285.8" y="245.3">SW6</text>
<text x="297.2" y="245.3">SW7</text>
<text x="330.6" y="242.7">A3</text>
<text x="341.5" y="242.7">B3</text>
<text x="388" y="244.8">C47</text>
<text x="423.1" y="245.4">+12P</text>
<text x="488.8" y="240.4">GNDPWR</text>
<text x="37.6" y="247.8">CAN</text>
<text x="58.5" y="247.8">CAN</text>
<text x="112.3" y="251.8">Q1</text>
<text x="143" y="248.5">R24</text>
<text x="143.1" y="250.8">10k</text>
<text x="149.4" y="251">R25</text>
<text x="156.4" y="247">0.1u</text>
<text x="169.3" y="248.5">VDD</text>
<text x="169.3" y="251">VSS</text>
<text x="181.9" y="247.3">U4</text>
<text x="182.1" y="249.6">AQM0802</text>
<text x="216.3" y="248.5">red_A</text>
<text x="227" y="248.5">red_K</text>
<text x="264.2" y="247.6">SW0</text>
<text x="274.4" y="247.6">SW1</text>
<text x="285.8" y="247.6">SW2</text>
<text x="297.2" y="247.6">SW3</text>
<text x="330.6" y="246.5">A4</text>
<text x="330.6" y="250.4">A5</text>
<text x="341.5" y="250.4">B5</text>
<text x="341.5" y="246.5">B4</text>
<text x="388.1" y="247.1">0.1u</text>
<text x="398.4" y="250">U15</text>
<text x="437.1" y="251.1">NVMFD5C446NLT1G</text>
<text x="444.6" y="248.8">Q8</text>
<text x="492.2" y="246.1">C65</text>
<text x="492.3" y="248.4">0.1u</text>
<text x="502.6" y="251.3">U22</text>
<text x="527.3" y="246.7">+12P</text>
<text x="548.2" y="250">Q13</text>
<text x="19.6" y="254.9">+3.3V</text>
<text x="55.6" y="256.1">JP3</text>
<text x="66.9" y="256.5">R10</text>
<text x="112.3" y="254.1">NPN</text>
<text x="149.4" y="253.3">10k</text>
<text x="169.3" y="253.5">SDA</text>
<text x="169.3" y="256.1">SCL</text>
<text x="236.3" y="252.9">GND</text>
<text x="261.1" y="256.1">GND</text>
<text x="271.2" y="256.1">GND</text>
<text x="282.7" y="256.1">GND</text>
<text x="294.1" y="256.1">GND</text>
<text x="330.6" y="254.2">A6</text>
<text x="330.6" y="258">GND1</text>
<text x="338.9" y="258">GND2</text>
<text x="341.5" y="254.2">B6</text>
<text x="370.4" y="252.4">+12P</text>
<text x="380.9" y="253.7">GNDPWR</text>
<text x="392.2" y="256.7">Vcc</text>
<text x="396.2" y="252.3">NCP5104</text>
<text x="401.6" y="256.7">VBOOT</text>
<text x="419.4" y="256.6">R75</text>
<text x="437.6" y="258">S1</text>
<text x="449.7" y="255.4">D1_1</text>
<text x="449.7" y="258">D1_2</text>
<text x="474.5" y="253.6">+12P</text>
<text x="485" y="255">GNDPWR</text>
<text x="496.3" y="258">Vcc</text>
<text x="500.4" y="253.6">NCP5104</text>
<text x="505.8" y="258">VBOOT</text>
<text x="523" y="257.9">R100</text>
<text x="541.3" y="252.3">NVMFD5C446NLT1G</text>
<text x="553.8" y="256.7">D1_1</text>
<text x="24.7" y="261.9">C4</text>
<text x="53.7" y="258">CAN_JP</text>
<text x="67.1" y="258.8">120</text>
<text x="108" y="262.4">GND</text>
<text x="169.3" y="258.6">/RST</text>
<text x="322.7" y="262.4">GND</text>
<text x="346" y="261.9">GNDPWR</text>
<text x="374.2" y="261.9">R60</text>
<text x="392.2" y="261.8">IN</text>
<text x="400.6" y="261.8">DRV_HO</text>
<text x="417.9" y="260.7">C56</text>
<text x="417.9" y="258.9">FILTER</text>
<text x="418" y="263">4.7u</text>
<text x="437.6" y="260.5">G1</text>
<text x="437.6" y="263.1">S2</text>
<text x="449.7" y="263.1">D1_4</text>
<text x="449.7" y="260.5">D1_3</text>
<text x="478.3" y="263.2">R89</text>
<text x="496.3" y="263.1">IN</text>
<text x="504.7" y="263.1">DRV_HO</text>
<text x="522" y="261.9">C71</text>
<text x="522" y="260.2">FILTER</text>
<text x="541.8" y="259.2">S1</text>
<text x="541.8" y="261.8">G1</text>
<text x="553.8" y="259.2">D1_2</text>
<text x="553.8" y="261.8">D1_3</text>
<text x="24.9" y="264.3">0.1u</text>
<text x="36.8" y="264.4">+3.3V</text>
<text x="37.6" y="264.2">U1</text>
<text x="242.1" y="266.9">R40</text>
<text x="242.2" y="269.2">330</text>
<text x="253.5" y="266.9">R43</text>
<text x="253.6" y="269.2">330</text>
<text x="264.9" y="266.9">R47</text>
<text x="265.1" y="269.2">330</text>
<text x="276.4" y="266.9">R49</text>
<text x="276.5" y="269.2">330</text>
<text x="287.8" y="266.9">R51</text>
<text x="287.9" y="269.2">330</text>
<text x="298" y="266.9">R52</text>
<text x="298.1" y="269.2">330</text>
<text x="319.4" y="268.9">+3.3V</text>
<text x="353.1" y="268.9">+5P</text>
<text x="374.2" y="264.3">10k</text>
<text x="392.2" y="266.9">SD</text>
<text x="401" y="266.9">BRIDGE</text>
<text x="417.9" y="269.1">FILTER</text>
<text x="427.9" y="267">GNDPWR</text>
<text x="437.6" y="265.6">G2</text>
<text x="437.6" y="268.1">D2_1</text>
<text x="449.7" y="268.1">D2_3</text>
<text x="449.7" y="265.6">D1_5</text>
<text x="478.4" y="265.5">10k</text>
<text x="496.3" y="268.1">SD</text>
<text x="505.2" y="268.1">BRIDGE</text>
<text x="522.1" y="264.3">4.7u</text>
<text x="532" y="268.3">GNDPWR</text>
<text x="541.8" y="264.3">S2</text>
<text x="541.8" y="266.9">G2</text>
<text x="541.8" y="269.4">D2_1</text>
<text x="553.8" y="264.3">D1_4</text>
<text x="553.8" y="269.4">D2_3</text>
<text x="553.8" y="266.9">D1_5</text>
<text x="19.8" y="271.3">GND</text>
<text x="29.6" y="273.9">TXD</text>
<text x="39.4" y="275.4" transform="rotate(-90 39.4 275.4)">VDD</text>
<text x="140.3" y="270.1">+3.3V</text>
<text x="243.3" y="274.7">D27</text>
<text x="254.7" y="274.7">D28</text>
<text x="266.2" y="274.7">D29</text>
<text x="277.6" y="274.7">D30</text>
<text x="289" y="274.7">D31</text>
<text x="299.2" y="274.7">D32</text>
<text x="324.5" y="275.9">C37</text>
<text x="357.5" y="275.9">C39</text>
<text x="392.2" y="271.9">GND</text>
<text x="400.8" y="271.9">DRV_LO</text>
<text x="437.6" y="270.7">D2_2</text>
<text x="449.7" y="270.7">D2_4</text>
<text x="449.7" y="273.2">D2_5</text>
<text x="496.3" y="273.2">GND</text>
<text x="504.9" y="273.2">DRV_LO</text>
<text x="522" y="270.3">FILTER</text>
<text x="541.8" y="271.9">D2_2</text>
<text x="553.8" y="271.9">D2_4</text>
<text x="553.8" y="274.5">D2_5</text>
<text x="29.6" y="276.4">RXD</text>
<text x="29.6" y="281.5">SHDN</text>
<text x="42.8" y="276.4">CANH</text>
<text x="43" y="281.5">CANL</text>
<text x="145.4" y="277.2">C19</text>
<text x="145.6" y="279.5">0.1u</text>
<text x="243.2" y="277">LED0</text>
<text x="254.6" y="277">LED1</text>
<text x="266" y="277">LED2</text>
<text x="277.4" y="277">LED3</text>
<text x="288.9" y="277">LED4</text>
<text x="299" y="277">LED5</text>
<text x="322.5" y="280.3">+3.3V</text>
<text x="324.6" y="278.2">0.1u</text>
<text x="348.7" y="280.3">+5P</text>
<text x="357.7" y="278.2">0.1u</text>
<text x="383.1" y="281.6">+12P</text>
<text x="384.7" y="278.5">GNDPWR</text>
<text x="488.8" y="279.7">GNDPWR</text>
<text x="29.6" y="284">RS</text>
<text x="39.4" y="284.9" transform="rotate(-90 39.4 284.9)">GND</text>
<text x="97.4" y="286.6">SERIAL2</text>
<text x="100.2" y="284.3">J9</text>
<text x="116.3" y="286.7">+5V</text>
<text x="119.3" y="287.9">+3.3VD17</text>
<text x="140.4" y="286.6">GND</text>
<text x="238.2" y="284">GND</text>
<text x="249.6" y="284">GND</text>
<text x="261.1" y="284">GND</text>
<text x="272.5" y="284">GND</text>
<text x="283.9" y="284">GND</text>
<text x="294.1" y="284">GND</text>
<text x="319.5" y="285.3">GND</text>
<text x="330.6" y="284.6">VDD1</text>
<text x="339.1" y="284.6">VDD2</text>
<text x="350.4" y="284.8">GNDPWR</text>
<text x="487.2" y="282.8">+12P</text>
<text x="36.9" y="293.5">GND</text>
<text x="69.4" y="292.8">C9</text>
<text x="98.9" y="291">VBUS</text>
<text x="124.1" y="291.8">RX</text>
<text x="124.2" y="289.9">TX</text>
<text x="131.1" y="289">R14</text>
<text x="131.2" y="293.2">330</text>
<text x="131.2" y="291.3">330</text>
<text x="142.6" y="292.3">Vdd</text>
<text x="150.1" y="292.3">Vss</text>
<text x="165.7" y="293.6">+3.3V</text>
<text x="189.3" y="293.7">TOGGLESW0</text>
<text x="192.4" y="291.4">SW2A</text>
<text x="221.1" y="293.7">TOGGLESW1</text>
<text x="223.6" y="291.4">SW10A</text>
<text x="252.8" y="293.7">TOGGLESW2</text>
<text x="255.4" y="291.4">SW11A</text>
<text x="284.6" y="293.7">TOGGLESW3</text>
<text x="287.1" y="291.4">SW12A</text>
<text x="330.6" y="288.5">A1</text>
<text x="330.6" y="292.3">A2</text>
<text x="341.5" y="292.3">B2</text>
<text x="341.5" y="288.5">B1</text>
<text x="388" y="288.6">C48</text>
<text x="388.1" y="290.9">0.1u</text>
<text x="398.4" y="293.8">U16</text>
<text x="423.1" y="289.2">+12P</text>
<text x="444.6" y="292.6">Q9</text>
<text x="492.2" y="289.9">C66</text>
<text x="492.3" y="292.2">0.1u</text>
<text x="527.3" y="290.5">+12P</text>
<text x="548.2" y="293.8">Q14</text>
<text x="65.5" y="294.9">+5V0.1u</text>
<text x="101.4" y="296.1">D+</text>
<text x="131.2" y="295.1">10k</text>
<text x="142.6" y="294.2">GP0</text>
<text x="142.6" y="296.1">GP1</text>
<text x="142.6" y="298">nRST</text>
<text x="142.6" y="299.9">URx</text>
<text x="149" y="298">Vusb</text>
<text x="149.8" y="299.9">SCL</text>
<text x="151" y="294.2">D+</text>
<text x="162" y="296.7">GND</text>
<text x="330.6" y="296.1">A3</text>
<text x="330.6" y="299.9">A4</text>
<text x="341.5" y="299.9">B4</text>
<text x="341.5" y="296.1">B3</text>
<text x="371" y="296.2">+12P</text>
<text x="380.9" y="297.5">GNDPWR</text>
<text x="396.2" y="296.2">NCP5104</text>
<text x="437.1" y="294.9">NVMFD5C446NLT1G</text>
<text x="449.7" y="299.3">D1_1</text>
<text x="475.2" y="297.5">+12P</text>
<text x="485" y="298.8">GNDPWR</text>
<text x="500.4" y="297.4">NCP5104</text>
<text x="502.6" y="295.1">U23</text>
<text x="541.3" y="296.2">NVMFD5C446NLT1G</text>
<text x="82.8" y="304.4">SERIAL0</text>
<text x="82.9" y="302">J6</text>
<text x="97.8" y="302" transform="rotate(-90 97.8 302)">Shield</text>
<text x="100.3" y="302" transform="rotate(-90 100.3 302)">GND</text>
<text x="102" y="301.2">ID</text>
<text x="142.6" y="301.8">UTx</text>
<text x="142.6" y="303.7">GP2</text>
<text x="149.6" y="301.8">SDA</text>
<text x="149.8" y="303.7">GP3</text>
<text x="198.2" y="305.6">GND</text>
<text x="229.9" y="305.6">GND</text>
<text x="261.7" y="305.6">GND</text>
<text x="293.4" y="305.6">GND</text>
<text x="330.6" y="303.7">A5</text>
<text x="341.5" y="303.7">B5</text>
<text x="374.8" y="305.8">R64</text>
<text x="392.2" y="300.5">Vcc</text>
<text x="392.2" y="305.6">IN</text>
<text x="400.6" y="305.6">DRV_HO</text>
<text x="401.6" y="300.5">VBOOT</text>
<text x="417.9" y="304.5">C57</text>
<text x="417.9" y="302.7">FILTER</text>
<text x="419.4" y="300.4">R77</text>
<text x="437.6" y="301.8">S1</text>
<text x="437.6" y="304.3">G1</text>
<text x="449.7" y="301.8">D1_2</text>
<text x="449.7" y="304.3">D1_3</text>
<text x="496.3" y="301.8">Vcc</text>
<text x="505.8" y="301.8">VBOOT</text>
<text x="522" y="305.8">C72</text>
<text x="522" y="304">FILTER</text>
<text x="523" y="301.7">R102</text>
<text x="541.8" y="303.1">S1</text>
<text x="541.8" y="305.6">G1</text>
<text x="553.8" y="300.5">D1_1</text>
<text x="553.8" y="303.1">D1_2</text>
<text x="553.8" y="305.6">D1_3</text>
<text x="97.9" y="310.7">GND</text>
<text x="203.5" y="310.9">J1</text>
<text x="237.4" y="310.8">+3.3V</text>
<text x="330.6" y="307.5">A6</text>
<text x="330.6" y="311.3">GND1</text>
<text x="338.9" y="311.3">GND2</text>
<text x="341.5" y="307.5">B6</text>
<text x="374.9" y="308.1">10k</text>
<text x="392.2" y="310.7">SD</text>
<text x="401" y="310.7">BRIDGE</text>
<text x="418" y="306.8">4.7u</text>
<text x="427.9" y="310.8">GNDPWR</text>
<text x="437.6" y="306.9">S2</text>
<text x="437.6" y="309.4">G2</text>
<text x="437.6" y="312">D2_1</text>
<text x="449.7" y="306.9">D1_4</text>
<text x="449.7" y="312">D2_3</text>
<text x="449.7" y="309.4">D1_5</text>
<text x="478.9" y="307">R93</text>
<text x="479" y="309.3">10k</text>
<text x="496.3" y="306.9">IN</text>
<text x="496.3" y="312">SD</text>
<text x="504.7" y="306.9">DRV_HO</text>
<text x="505.2" y="312">BRIDGE</text>
<text x="522.1" y="308.1">4.7u</text>
<text x="541.8" y="308.1">S2</text>
<text x="541.8" y="310.7">G2</text>
<text x="553.8" y="308.1">D1_4</text>
<text x="553.8" y="310.7">D1_5</text>
<text x="200.8" y="313.2">microSD</text>
<text x="242.6" y="317.8">C40</text>
<text x="251.5" y="317.8">C79</text>
<text x="260.4" y="317.8">C80</text>
<text x="267.3" y="316.5">+3.3V</text>
<text x="322.7" y="315.8">GND</text>
<text x="346" y="315.3">GNDPWR</text>
<text x="392.2" y="315.8">GND</text>
<text x="400.8" y="315.8">DRV_LO</text>
<text x="417.9" y="312.9">FILTER</text>
<text x="437.6" y="314.5">D2_2</text>
<text x="449.7" y="314.5">D2_4</text>
<text x="449.7" y="317">D2_5</text>
<text x="496.3" y="317">GND</text>
<text x="504.9" y="317">DRV_LO</text>
<text x="522" y="314.1">FILTER</text>
<text x="532" y="312.1">GNDPWR</text>
<text x="541.8" y="313.2">D2_1</text>
<text x="541.8" y="315.8">D2_2</text>
<text x="553.8" y="313.2">D2_3</text>
<text x="553.8" y="315.8">D2_4</text>
<text x="21.1" y="322.8">R26</text>
<text x="30" y="322.8">R84</text>
<text x="38.9" y="322.8">R85</text>
<text x="47.8" y="322.8">R86</text>
<text x="56.8" y="322.8">R106</text>
<text x="65.7" y="322.8">R107</text>
<text x="74.6" y="322.8">R108</text>
<text x="83.5" y="322.8">R109</text>
<text x="176" y="321.1">FILTER</text>
<text x="176" y="323.7">FILTER</text>
<text x="177.4" y="318.8">R46</text>
<text x="177.4" y="321.4">R48</text>
<text x="187.7" y="321.5">DAT2</text>
<text x="242.7" y="320.1">0.1u</text>
<text x="251.6" y="320.1">0.1u</text>
<text x="260.5" y="320.1">0.1u</text>
<text x="383.1" y="320.9">+12P</text>
<text x="384.7" y="322.3">GNDPWR</text>
<text x="487.2" y="322.2">+12P</text>
<text x="488.8" y="323.5">GNDPWR</text>
<text x="553.8" y="318.3">D2_5</text>
<text x="21.2" y="325.1">330</text>
<text x="30.1" y="325.1">330</text>
<text x="39" y="325.1">330</text>
<text x="47.9" y="325.1">330</text>
<text x="56.8" y="325.1">330</text>
<text x="65.7" y="325.1">330</text>
<text x="74.6" y="325.1">330</text>
<text x="83.5" y="325.1">330</text>
<text x="119.8" y="326.6">2</text>
<text x="129.4" y="326.6">8</text>
<text x="176" y="328.7">FILTER</text>
<text x="177.4" y="326.4">R50</text>
<text x="180.9" y="324.8">+3.3V</text>
<text x="187.7" y="324">DAT3/CD</text>
<text x="187.7" y="326.6">CMD</text>
<text x="187.7" y="329.1">VDD</text>
<text x="235.5" y="326.7">+3.3V</text>
<text x="239.7" y="325.8">R41</text>
<text x="239.8" y="328.1">10k</text>
<text x="255.3" y="327.2">GND</text>
<text x="388" y="328">C49</text>
<text x="423.1" y="328.6">+12P</text>
<text x="492.2" y="329.3">C67</text>
<text x="527.3" y="329.8">+12P</text>
<text x="22.2" y="332.9">LED0</text>
<text x="22.3" y="330.6">D1</text>
<text x="31.1" y="332.9">LED1</text>
<text x="31.1" y="330.6">D2</text>
<text x="40" y="332.9">LED2</text>
<text x="40" y="330.6">D7</text>
<text x="48.8" y="332.9">LED3</text>
<text x="49" y="330.6">D10</text>
<text x="57.7" y="332.9">LED4</text>
<text x="57.9" y="330.6">D11</text>
<text x="66.6" y="332.9">LED5</text>
<text x="66.8" y="330.6">D13</text>
<text x="75.5" y="332.9">LED6</text>
<text x="75.7" y="330.6">D21</text>
<text x="84.4" y="332.9">LED7</text>
<text x="84.6" y="330.6">D22</text>
<text x="111.8" y="334.8">GND</text>
<text x="119.8" y="330.4">C</text>
<text x="119.8" y="334.2">1</text>
<text x="129.2" y="330.4">C</text>
<text x="129.4" y="334.2">4</text>
<text x="134.7" y="334.8">GND</text>
<text x="176" y="333.8">FILTER</text>
<text x="177.4" y="331.5">R39</text>
<text x="187.7" y="331.6">CLK</text>
<text x="187.7" y="334.2">VSS</text>
<text x="255" y="331">MCLR</text>
<text x="269.9" y="332.2" transform="rotate(-90 269.9 332.2)">Vdd</text>
<text x="272.4" y="332.2" transform="rotate(-90 272.4 332.2)">Vdd</text>
<text x="275" y="333.5" transform="rotate(-90 275 333.5)">AVdd</text>
<text x="290.9" y="333.5">PGEC3_AN1_C3IND_Vref-_RP6_CTED2_CN3_RA1</text>
<text x="291.5" y="331">PGED3_AN0_C3INC_Vref+_RP5_CTED1CN2_RA0</text>
<text x="370.4" y="335.6">+12P</text>
<text x="388.1" y="330.3">0.1u</text>
<text x="396.2" y="335.5">NCP5104</text>
<text x="398.4" y="333.2">U17</text>
<text x="437.1" y="334.3">NVMFD5C446NLT1G</text>
<text x="444.1" y="331.9">Q10</text>
<text x="492.3" y="331.6">0.1u</text>
<text x="502.6" y="334.5">U24</text>
<text x="541.3" y="335.5">NVMFD5C446NLT1G</text>
<text x="548.2" y="333.2">Q15</text>
<text x="17.2" y="339.9">GND</text>
<text x="26.1" y="339.9">GND</text>
<text x="35" y="339.9">GND</text>
<text x="43.9" y="339.9">GND</text>
<text x="52.8" y="339.9">GND</text>
<text x="61.7" y="339.9">GND</text>
<text x="70.6" y="339.9">GND</text>
<text x="79.5" y="339.9">GND</text>
<text x="178.6" y="339.3">R45</text>
<text x="178.6" y="341.6">10k</text>
<text x="187.7" y="341.8">DET_A</text>
<text x="187.7" y="336.7">DAT0</text>
<text x="187.7" y="339.3">DAT1</text>
<text x="245.2" y="336.8">+5V</text>
<text x="255" y="336.1">Vusb</text>
<text x="255" y="341.2">Vbus</text>
<text x="324.7" y="338.6">TDO_RA8</text>
<text x="324.8" y="336.1">TCK_RA7</text>
<text x="325.6" y="341.2">TDI_RA9</text>
<text x="380.9" y="336.9">GNDPWR</text>
<text x="392.2" y="339.9">Vcc</text>
<text x="401.6" y="339.9">VBOOT</text>
<text x="419.4" y="339.8">R79</text>
<text x="437.6" y="341.2">S1</text>
<text x="449.7" y="338.6">D1_1</text>
<text x="449.7" y="341.2">D1_2</text>
<text x="474.5" y="336.8">+12P</text>
<text x="485" y="338.1">GNDPWR</text>
<text x="496.3" y="341.2">Vcc</text>
<text x="500.4" y="336.8">NCP5104</text>
<text x="505.8" y="341.2">VBOOT</text>
<text x="523" y="341">R104</text>
<text x="553.8" y="339.9">D1_1</text>
<text x="187.7" y="344.3">DET_B</text>
<text x="214.8" y="344.3">SHIELD</text>
<text x="255" y="346.2">PGED2_D+_RP10_CN16_RB10</text>
<text x="323.7" y="343.7">TMS_RA10</text>
<text x="374.2" y="345.1">R61</text>
<text x="374.2" y="347.4">10k</text>
<text x="392.2" y="345">IN</text>
<text x="400.6" y="345">DRV_HO</text>
<text x="417.9" y="343.9">C58</text>
<text x="417.9" y="342.1">FILTER</text>
<text x="418" y="346.2">4.7u</text>
<text x="437.6" y="343.7">G1</text>
<text x="437.6" y="346.2">S2</text>
<text x="449.7" y="346.2">D1_4</text>
<text x="449.7" y="343.7">D1_3</text>
<text x="478.3" y="346.4">R90</text>
<text x="496.3" y="346.2">IN</text>
<text x="504.7" y="346.2">DRV_HO</text>
<text x="522" y="345.1">C73</text>
<text x="522" y="343.3">FILTER</text>
<text x="522.1" y="347.4">4.7u</text>
<text x="541.8" y="342.4">S1</text>
<text x="541.8" y="345">G1</text>
<text x="541.8" y="347.5">S2</text>
<text x="553.8" y="347.5">D1_4</text>
<text x="553.8" y="342.4">D1_2</text>
<text x="553.8" y="345">D1_3</text>
<text x="42.5" y="350.8">+3.3V</text>
<text x="49.7" y="348.8">C7</text>
<text x="49.8" y="351.1">1u</text>
<text x="97.4" y="353.3">+12V</text>
<text x="100.9" y="354">VALVE_JP</text>
<text x="103.8" y="351.7">JP4</text>
<text x="110.5" y="353.3">+5V</text>
<text x="179.1" y="352">GND</text>
<text x="255" y="353.9">AN4_C1NB_SDA2_RP2_CN6_RB2</text>
<text x="255" y="348.8">PGEC2_D-_RP11_CN15_RB11</text>
<text x="301.4" y="351.3">PGEDC1_AN3_C2INA_RP1_CN5_RB1</text>
<text x="302.7" y="348.8">PGED1_AN2_C2INB_RP0_CN4_RB0</text>
<text x="317.5" y="353.9">CN27_USBID_RB5</text>
<text x="392.2" y="350.1">SD</text>
<text x="401" y="350.1">BRIDGE</text>
<text x="417.9" y="352.2">FILTER</text>
<text x="427.9" y="350.2">GNDPWR</text>
<text x="437.6" y="348.8">G2</text>
<text x="437.6" y="351.3">D2_1</text>
<text x="437.6" y="353.9">D2_2</text>
<text x="449.7" y="351.3">D2_3</text>
<text x="449.7" y="353.9">D2_4</text>
<text x="449.7" y="348.8">D1_5</text>
<text x="478.4" y="348.7">10k</text>
<text x="496.3" y="351.3">SD</text>
<text x="505.2" y="351.3">BRIDGE</text>
<text x="522" y="353.5">FILTER</text>
<text x="532" y="351.5">GNDPWR</text>
<text x="541.8" y="350.1">G2</text>
<text x="541.8" y="352.6">D2_1</text>
<text x="553.8" y="352.6">D2_3</text>
<text x="553.8" y="350.1">D1_5</text>
<text x="49.8" y="358.6">J5</text>
<text x="110.1" y="356.4">C12</text>
<text x="110.7" y="358.7">1u</text>
<text x="129.5" y="357.1">+3.3V</text>
<text x="150.5" y="359.7">+5V0.1u</text>
<text x="153.9" y="357.7">C22</text>
<text x="178.4" y="357.1">+3.3V</text>
<text x="199.4" y="359.7">+5V0.1u</text>
<text x="202.8" y="357.7">C33</text>
<text x="255" y="356.4">AN5_C1INA_RTCC_SCL2_RP3_CN7_RB3</text>
<text x="299.9" y="358.9">AN11_C1INC_RP13_REFO_CN13_RB13</text>
<text x="314.7" y="356.4">RP7_INT0_CN23_RB7</text>
<text x="343.6" y="357.5">D49</text>
<text x="343.6" y="354.9">D37</text>
<text x="351.4" y="356.3">R42</text>
<text x="351.6" y="358.6">330</text>
<text x="354.9" y="357.1">+3.3V</text>
<text x="392.2" y="355.1">GND</text>
<text x="400.8" y="355.1">DRV_LO</text>
<text x="449.7" y="356.4">D2_5</text>
<text x="496.3" y="356.4">GND</text>
<text x="504.9" y="356.4">DRV_LO</text>
<text x="541.8" y="355.1">D2_2</text>
<text x="553.8" y="355.1">D2_4</text>
<text x="553.8" y="357.7">D2_5</text>
<text x="46.7" y="360.9">ADC_Vdd</text>
<text x="82.2" y="365">U27</text>
<text x="139.2" y="364.2">R18</text>
<text x="188.1" y="364.2">R30</text>
<text x="255" y="361.5">SDA1_RP9_CN21_RB9</text>
<text x="255" y="364">SCL1_RP8_CN22_RB8</text>
<text x="291.5" y="361.5">AN10_C3INB_CVref_VBUSON_RP14_CN12_RB14</text>
<text x="296.9" y="364">AN9_C3INA_VBUSCHG_RP15_CN11_RB15</text>
<text x="351.6" y="361.1">330</text>
<text x="384.7" y="361.6">GNDPWR</text>
<text x="488.8" y="362.9">GNDPWR</text>
<text x="78.5" y="371.6">IN1</text>
<text x="78.9" y="367.3">TBD62083A</text>
<text x="84.4" y="371.6">OUT1</text>
<text x="108.4" y="368.5">I/O_Vdd</text>
<text x="110.3" y="366.2">J10</text>
<text x="133.5" y="369">1k</text>
<text x="133.5" y="366.7">R12</text>
<text x="139.2" y="366.5">1k</text>
<text x="146.8" y="371.7">R22</text>
<text x="167.9" y="369.1">ENC1</text>
<text x="168" y="366.8">J11</text>
<text x="182.3" y="369">1k</text>
<text x="182.4" y="366.7">R28</text>
<text x="188.1" y="366.5">1k</text>
<text x="195.7" y="371.7">R34</text>
<text x="207.1" y="368.5">GND3</text>
<text x="216.8" y="369.1">ENC3</text>
<text x="216.9" y="366.8">J13</text>
<text x="255" y="369.1">OSC1_CLKI_C1IND_CN30_RA2</text>
<text x="255" y="371.6">OSC0_CLK0_CN29_RA3</text>
<text x="315" y="369.1">AN6_RP16_CN8_RC0</text>
<text x="315" y="371.6">AN7_RP17_CN9_RC1</text>
<text x="39.5" y="376.7">ADC</text>
<text x="39.7" y="374.4">J2</text>
<text x="78.5" y="374.2">IN2</text>
<text x="78.5" y="376.7">IN3</text>
<text x="84.4" y="376.7">OUT3</text>
<text x="84.4" y="374.2">OUT2</text>
<text x="140.5" y="374.2">R20</text>
<text x="140.6" y="376.5">100</text>
<text x="147" y="374">100</text>
<text x="189.4" y="374.2">R32</text>
<text x="189.5" y="376.5">100</text>
<text x="195.9" y="374">100</text>
<text x="255" y="376.7">SOCI_C2IND_RP4_CN1_RB4</text>
<text x="313" y="376.7">AN12_RP19_CN28_RC3</text>
<text x="314" y="374.2">AN8_RP18_CN10_RC2</text>
<text x="401.3" y="376.9">J28</text>
<text x="78.5" y="379.3">IN4</text>
<text x="78.5" y="381.8">IN5</text>
<text x="84.4" y="381.8">OUT5</text>
<text x="84.4" y="379.3">OUT4</text>
<text x="99.7" y="381.8">VALVE</text>
<text x="100" y="379.5">J8</text>
<text x="129.5" y="382.5">+3.3V</text>
<text x="153.9" y="383.1">C23</text>
<text x="178.4" y="382.5">+3.3V</text>
<text x="202.8" y="383.1">C34</text>
<text x="240.9" y="383.1">C78</text>
<text x="255" y="379.3">SOSCO_SCLK_T1CK_C2INC_CN0_RA4</text>
<text x="318.5" y="379.3">RP20_CN25_RC4</text>
<text x="318.5" y="381.8">RP21_CN26_RC5</text>
<text x="359.5" y="381.2">Advanced_SBDBT +5V</text>
<text x="365.7" y="378.9">J27</text>
<text x="401.4" y="379.2">PICkit3</text>
<text x="78.5" y="384.3">IN6</text>
<text x="78.5" y="386.9">IN7</text>
<text x="78.5" y="389.4">IN8</text>
<text x="84.4" y="389.4">OUT8</text>
<text x="84.4" y="386.9">OUT7</text>
<text x="84.4" y="384.3">OUT6</text>
<text x="139.2" y="389.6">R19</text>
<text x="150.5" y="385.1">+5V0.1u</text>
<text x="188.1" y="389.6">R31</text>
<text x="199.4" y="385.1">+5V0.1u</text>
<text x="241.6" y="385.4">1u</text>
<text x="255" y="389.4">Vcap_VddCore</text>
<text x="318.5" y="384.3">RP22_CN18_RC6</text>
<text x="318.5" y="386.9">RP23_CN17_RC7</text>
<text x="318.5" y="389.4">RP24_CN20_RC8</text>
<text x="364.9" y="385.6">VBUS</text>
<text x="391.6" y="387">PIKkit_Vdd</text>
<text x="401.9" y="387">+3.3V</text>
<text x="55.3" y="391.3">GND</text>
<text x="78.5" y="392">GND</text>
<text x="85" y="392">COM</text>
<text x="116.3" y="393.9">GND</text>
<text x="133.5" y="394.4">1k</text>
<text x="133.5" y="392.1">R13</text>
<text x="139.2" y="391.9">1k</text>
<text x="158.2" y="393.9">GND3</text>
<text x="167.9" y="394.5">ENC0</text>
<text x="168" y="392.2">J12</text>
<text x="182.3" y="394.4">1k</text>
<text x="182.4" y="392.1">R29</text>
<text x="188.1" y="391.9">1k</text>
<text x="207.1" y="393.9">GND3</text>
<text x="216.8" y="394.5">ENC2</text>
<text x="216.9" y="392.2">J14</text>
<text x="255" y="392">DISVREG</text>
<text x="269.9" y="392.9" transform="rotate(-90 269.9 392.9)">Vss</text>
<text x="272.4" y="392.9" transform="rotate(-90 272.4 392.9)">Vss</text>
<text x="275" y="392.9" transform="rotate(-90 275 392.9)">AVss</text>
<text x="318.5" y="392">RP25_CN19_RC9</text>
<text x="367.5" y="390.7">D+</text>
<text x="73.1" y="396.4">GND</text>
<text x="140.5" y="399.6">R21</text>
<text x="140.6" y="401.9">100</text>
<text x="146.8" y="397.1">R23</text>
<text x="147" y="399.4">100</text>
<text x="189.4" y="399.6">R33</text>
<text x="189.5" y="401.9">100</text>
<text x="195.7" y="397.1">R35</text>
<text x="195.9" y="399.4">100</text>
<text x="244.6" y="396.4">GND</text>
<text x="363.9" y="396.7" transform="rotate(-90 363.9 396.7)">Shield</text>
<text x="366.4" y="396.7" transform="rotate(-90 366.4 396.7)">GND</text>
<text x="272.5" y="406.6">GND</text>
<text x="363.9" y="405.3">GND</text>
</g>
<g font-size="1.8">
<text x="85.1" y="20.9">FB_Control_OUT</text>
<text x="488.9" y="22.8">Motor0L</text>
<text x="85.1" y="28.5">FB_Control</text>
<text x="135.5" y="24.7">FB_Control_OUT</text>
<text x="488.8" y="25.3">Motor0R</text>
<text x="488.9" y="34.2">Motor1L</text>
<text x="90.1" y="41.2">FB_Control</text>
<text x="97.9" y="41.4">GND3</text>
<text x="488.8" y="36.7">Motor1R</text>
<text x="488.9" y="45.6">Motor2L</text>
<text x="77.5" y="53.9">SWCLK</text>
<text x="488.8" y="48.2">Motor2R</text>
<text x="77.5" y="59">RST</text>
<text x="77.5" y="56.4">SWDIO</text>
<text x="488.8" y="59.6">Motor3R</text>
<text x="488.9" y="57.1">Motor3L</text>
<text x="488.8" y="71">Motor4R</text>
<text x="488.9" y="68.5">Motor4L</text>
<text x="15" y="77.4">OSC_IN</text>
<text x="31.7" y="77.4">OSC_OUT</text>
<text x="49.8" y="83.1">RST</text>
<text x="307.3" y="83.1">PE2_IO</text>
<text x="307.3" y="80.6">PE1_IO</text>
<text x="307.3" y="78">PE0_IO</text>
<text x="488.8" y="82.5">Motor5R</text>
<text x="488.9" y="79.9">Motor5L</text>
<text x="46.8" y="88.2">OSC_IN</text>
<text x="307.3" y="88.2">PE4_IO</text>
<text x="307.3" y="85.6">PE3_IO</text>
<text x="307.3" y="93.3">motor0_R_signal</text>
<text x="307.3" y="90.7">motor0_L_signal</text>
<text x="307.3" y="95.8">PE7_SW3</text>
<text x="399.9" y="92">FB_OUT</text>
<text x="16.2" y="99.6">RST</text>
<text x="307.3" y="98.3">PE8_ADRESS0</text>
<text x="307.3" y="100.9">motor5_R_signal</text>
<text x="44.8" y="103.4">OSC_OUT</text>
<text x="307.3" y="103.4">PE10_ADRESS1</text>
<text x="307.3" y="106">motor5_L_signal</text>
<text x="307.3" y="108.5">PE12_SW2</text>
<text x="307.3" y="111">motor4_R_signal</text>
<text x="307.3" y="113.6">motor4_L_signal</text>
<text x="352.4" y="111">FB_OUT</text>
<text x="307.3" y="116.1">PE15_SW1</text>
<text x="40.4" y="123.7">PA0_TIM5_CH1</text>
<text x="307.3" y="123.7">CAN1_RX</text>
<text x="39.4" y="128.8">PA2_ADC12_IN2</text>
<text x="39.4" y="131.4">PA3_ADC12_IN3</text>
<text x="40.4" y="126.3">PA0_TIM5_CH2</text>
<text x="307.3" y="126.3">CAN1_TX</text>
<text x="307.3" y="131.4">PD3_DIPSW_1</text>
<text x="307.3" y="128.8">PD2_DIPSW_0</text>
<text x="40.4" y="136.4">PA5_SPI1_SCK</text>
<text x="40.5" y="133.9">PA4_SPI1_NSS</text>
<text x="307.3" y="136.4">PD5_USART2_TX</text>
<text x="307.3" y="133.9">PD4_DIPSW_2</text>
<text x="424.8" y="134.5">Motor0L</text>
<text x="529" y="135.8">Motor3L</text>
<text x="39.6" y="139">PA6_SPI1_MISO</text>
<text x="39.6" y="141.5">PA7_SPI1_MOSI</text>
<text x="307.3" y="139">PD6_USART2_RX</text>
<text x="307.3" y="141.5">PD7_DIPSW_3</text>
<text x="374.7" y="138.3">MOTOR0L_PWM 2</text>
<text x="414.7" y="143.4">Motor0L</text>
<text x="478.8" y="139.6">MOTOR3L_PWM 2</text>
<text x="37.4" y="149.1">PA10_USART1_RX</text>
<text x="38.6" y="146.6">PA9_USART1_TX</text>
<text x="44.4" y="144.1">PA8_LED5</text>
<text x="307.3" y="149.1">PD10_TOGGLESW_0</text>
<text x="307.3" y="144.1">PD8_USART3_TX</text>
<text x="307.3" y="146.6">PD9_USART3_RX</text>
<text x="419.4" y="144.2">R70</text>
<text x="459.7" y="144.7">Motor0L</text>
<text x="518.8" y="144.7">Motor3L</text>
<text x="523.5" y="145.5">R95</text>
<text x="563.9" y="146">Motor3L</text>
<text x="43.4" y="154.2">PA12_LED3</text>
<text x="43.4" y="151.7">PA11_LED4</text>
<text x="307.3" y="151.7">PD11_TOGGLESW_1</text>
<text x="307.3" y="154.2">PD12_TIM4_CH1</text>
<text x="39.4" y="161.8">PA15_TIM2_CH1</text>
<text x="46.9" y="159.3">SWCLK</text>
<text x="47.3" y="156.8">SWDIO</text>
<text x="307.3" y="161.8">PD15_TOGGLESW_3</text>
<text x="307.3" y="159.3">PD14_TOGGLESW_2</text>
<text x="307.3" y="156.8">PD13_TIM4_CH2</text>
<text x="39.4" y="169.5">PB0_ADC12_IN8</text>
<text x="39.4" y="172">PB1_ADC12_IN9</text>
<text x="307.3" y="169.5">PC0_ADC12_IN10</text>
<text x="307.3" y="172">PC1_ADC12_IN11</text>
<text x="424.6" y="173.9">Motor0R</text>
<text x="40.4" y="177.1">PB3_TIM2_CH2</text>
<text x="40.4" y="179.6">PB4_TIM3_CH1</text>
<text x="45.1" y="174.5">PB2_SW0</text>
<text x="307.3" y="174.5">PC2_ADC12_IN12</text>
<text x="307.3" y="177.1">PC3_ADC12_IN13</text>
<text x="307.3" y="179.6">PC4_ADC12_IN14</text>
<text x="374.5" y="177.7">MOTOR0R_PWM 2</text>
<text x="478.6" y="179">MOTOR3R_PWM 2</text>
<text x="528.8" y="175.2">Motor3R</text>
<text x="40.4" y="182.2">PB5_TIM3_CH2</text>
<text x="40.7" y="184.7">PB6_I2C1_SCL</text>
<text x="307.3" y="182.2">PC5_ADC12_IN15</text>
<text x="307.3" y="184.7">motor2_R_signal</text>
<text x="414.7" y="182.8">Motor0R</text>
<text x="419.4" y="183.6">R72</text>
<text x="459.7" y="184.1">Motor0R</text>
<text x="518.8" y="184.1">Motor3R</text>
<text x="523.5" y="184.8">R97</text>
<text x="563.9" y="185.3">Motor3R</text>
<text x="32.6" y="189.8">PB8_Buzzer_TIM10_CH1</text>
<text x="40.5" y="187.2">PB7_I2C1_SDA</text>
<text x="307.3" y="189.8">motor1_R_signal</text>
<text x="307.3" y="187.2">motor2_L_signal</text>
<text x="35.7" y="192.3">PB9_SD_Connection</text>
<text x="41.6" y="197.4">PB11_GREEN</text>
<text x="44.2" y="194.9">PB10_RED</text>
<text x="307.3" y="194.9">PC10_LED2</text>
<text x="307.3" y="197.4">PC11_LED1</text>
<text x="307.3" y="192.3">motor1_L_signal</text>
<text x="39.6" y="202.5">PB13_ADRESS3</text>
<text x="39.6" y="199.9">PB12_ADRESS2</text>
<text x="307.3" y="202.5">PC13_IO</text>
<text x="307.3" y="199.9">PC12_LED0</text>
<text x="39" y="205">motor3_R_signal</text>
<text x="39.2" y="207.6">motor3_L_signal</text>
<text x="307.3" y="207.6">PC15_IO</text>
<text x="307.3" y="205">PC14_IO</text>
<text x="374.7" y="221.5">MOTOR1L_PWM 2</text>
<text x="424.8" y="217.7">Motor1L</text>
<text x="529" y="219">Motor4L</text>
<text x="414.7" y="226.6">Motor1L</text>
<text x="419.4" y="227.4">R74</text>
<text x="459.7" y="227.9">Motor1L</text>
<text x="478.8" y="222.8">MOTOR4L_PWM 2</text>
<text x="518.8" y="227.9">Motor4L</text>
<text x="523.5" y="228.6">R99</text>
<text x="563.9" y="229.2">Motor4L</text>
<text x="263.5" y="239.9">PB2_SW0</text>
<text x="273.7" y="239.9">PE15_SW1</text>
<text x="285.1" y="239.9">PE12_SW2</text>
<text x="296.5" y="239.9">PE7_SW3</text>
<text x="310.1" y="238">motor0_R_signal</text>
<text x="310.3" y="234.2">motor0_L_signal</text>
<text x="349.9" y="234.2">MOTOR0L_PWM</text>
<text x="349.9" y="238">MOTOR0R_PWM</text>
<text x="190.9" y="245">PB11_GREEN</text>
<text x="192.4" y="242.5">PB12_BLUE</text>
<text x="310.1" y="245.7">motor1_R_signal</text>
<text x="310.3" y="241.9">motor1_L_signal</text>
<text x="349.9" y="245.7">MOTOR1R_PWM</text>
<text x="349.9" y="241.9">MOTOR1L_PWM</text>
<text x="21.8" y="246.9">CAN_HGND3</text>
<text x="22" y="249.5">CAN_L</text>
<text x="42.8" y="246.9">CAN_HGND3</text>
<text x="43" y="249.5">CAN_L</text>
<text x="193.4" y="247.6">PB10_RED</text>
<text x="310.3" y="249.5">motor2_L_signal</text>
<text x="349.9" y="249.5">MOTOR2L_PWM</text>
<text x="81.5" y="252">PB8_Buzzer_TIM10_CH1</text>
<text x="126.8" y="252.6">PB7_I2C1_SDA</text>
<text x="127" y="255.2">PB6_I2C1_SCL</text>
<text x="310.1" y="253.3">motor2_R_signal</text>
<text x="349.9" y="253.3">MOTOR2R_PWM</text>
<text x="424.6" y="257.1">Motor1R</text>
<text x="43.4" y="260.9">CAN_H</text>
<text x="72.4" y="260.9">CAN_L</text>
<text x="230.1" y="263.4">PC12_LED0</text>
<text x="241.5" y="263.4">PC11_LED1</text>
<text x="253" y="263.4">PC10_LED2</text>
<text x="264.4" y="263.4">PA12_LED3</text>
<text x="275.8" y="263.4">PA11_LED4</text>
<text x="287" y="263.4">PA8_LED5</text>
<text x="374.5" y="260.9">MOTOR1R_PWM 2</text>
<text x="478.6" y="262.2">MOTOR4R_PWM 2</text>
<text x="528.8" y="258.4">Motor4R</text>
<text x="414.7" y="266">Motor1R</text>
<text x="419.4" y="266.7">R76</text>
<text x="459.7" y="267.3">Motor1R</text>
<text x="518.8" y="267.3">Motor4R</text>
<text x="523" y="268">R101</text>
<text x="563.9" y="268.5">Motor4R</text>
<text x="17.8" y="275.5">CAN1_RX 4</text>
<text x="18" y="273">CAN1_TX 1</text>
<text x="49.7" y="275.5">7 CAN_H</text>
<text x="49.7" y="280.6">6 CAN_L</text>
<text x="310.3" y="287.6">motor3_L_signal</text>
<text x="349.9" y="287.6">MOTOR3L_PWM</text>
<text x="159.4" y="293.3">D+</text>
<text x="310.1" y="291.4">motor3_R_signal</text>
<text x="349.9" y="291.4">MOTOR3R_PWM</text>
<text x="105.6" y="297.7">2 D-</text>
<text x="105.6" y="295.2">3 D+</text>
<text x="121.8" y="299">PD5_USART2_TX</text>
<text x="122" y="299.5">ACTIVE</text>
<text x="131.1" y="298.5">R17</text>
<text x="170.3" y="297.7">PD10_TOGGLESW_0</text>
<text x="202" y="297.7">PD11_TOGGLESW_1</text>
<text x="233.8" y="297.7">PD14_TOGGLESW_2</text>
<text x="265.5" y="297.7">PD15_TOGGLESW_3</text>
<text x="310.1" y="299">motor4_R_signal</text>
<text x="310.3" y="295.2">motor4_L_signal</text>
<text x="349.9" y="295.2">MOTOR4L_PWM</text>
<text x="349.9" y="299">MOTOR4R_PWM</text>
<text x="57.5" y="306">PD9_USART3_RX</text>
<text x="57.7" y="303.4">PD8_USART3_TX GND3</text>
<text x="121.6" y="300.9">PD6_USART2_RX</text>
<text x="131.2" y="300.8">330</text>
<text x="310.3" y="302.8">motor5_L_signal</text>
<text x="349.9" y="302.8">MOTOR5L_PWM</text>
<text x="374.7" y="304.7">MOTOR2L_PWM 2</text>
<text x="424.8" y="300.9">Motor2L</text>
<text x="478.8" y="306">MOTOR5L_PWM 2</text>
<text x="529" y="302.2">Motor5L</text>
<text x="310.1" y="306.6">motor5_R_signal</text>
<text x="349.9" y="306.6">MOTOR5R_PWM</text>
<text x="414.7" y="309.8">Motor2L</text>
<text x="419.4" y="310.6">R78</text>
<text x="459.7" y="311.1">Motor2L</text>
<text x="518.8" y="311.1">Motor5L</text>
<text x="523" y="311.8">R103</text>
<text x="563.9" y="312.3">Motor5L</text>
<text x="12.9" y="319.3">PE0_IO</text>
<text x="21.7" y="319.3">PE1_IO</text>
<text x="30.6" y="319.3">PE2_IO</text>
<text x="39.5" y="319.3">PE3_IO</text>
<text x="48.4" y="319.3">PE4_IO</text>
<text x="56.2" y="319.3">PC15_IO</text>
<text x="65.1" y="319.3">PC14_IO</text>
<text x="74" y="319.3">PC13_IO</text>
<text x="162.4" y="323.1">PA4_SPI1_NSS</text>
<text x="100" y="325.7">PE10_ADRESS1</text>
<text x="136.5" y="325.7">PB13_ADRESS3</text>
<text x="161.5" y="325.7">PA7_SPI1_MOSI</text>
<text x="245.7" y="328.2">MCLR</text>
<text x="101" y="333.3">PE8_ADRESS0</text>
<text x="136.5" y="333.3">PB12_ADRESS2</text>
<text x="161.5" y="335.8">PA6_SPI1_MISO</text>
<text x="162.3" y="330.8">PA5_SPI1_SCK</text>
<text x="424.6" y="340.3">Motor2R</text>
<text x="528.8" y="341.5">Motor5R</text>
<text x="157.7" y="343.5">PB9_SD_Connection</text>
<text x="237.1" y="345.4">USB_A_D+</text>
<text x="237.5" y="347.9">USB_A_D-</text>
<text x="341.6" y="347.9">PGED1</text>
<text x="374.5" y="344.1">MOTOR2R_PWM 2</text>
<text x="478.6" y="345.4">MOTOR5R_PWM 2</text>
<text x="341.6" y="350.4">PGEC1</text>
<text x="414.7" y="349.2">Motor2R</text>
<text x="419.4" y="349.9">R80</text>
<text x="459.7" y="350.4">Motor2R</text>
<text x="518.8" y="350.4">Motor5R</text>
<text x="523" y="351.2">R105</text>
<text x="563.9" y="351.7">Motor5R</text>
<text x="17.4" y="363.1">PC0_ADC12_IN10</text>
<text x="17.4" y="365.7">PC1_ADC12_IN11</text>
<text x="17.4" y="368.2">PC2_ADC12_IN12</text>
<text x="17.4" y="370.8">PC3_ADC12_IN13</text>
<text x="68.7" y="370.8">PE0_IO 1</text>
<text x="18.4" y="373.3">PA2_ADC12_IN2</text>
<text x="18.4" y="375.8">PA3_ADC12_IN3</text>
<text x="68.7" y="375.8">PE2_IO 3</text>
<text x="68.7" y="373.3">PE1_IO 2</text>
<text x="146" y="375.8">PA0_TIM5_CH2</text>
<text x="194.9" y="375.8">PB3_TIM2_CH2</text>
<text x="17.4" y="380.9">PC5_ADC12_IN15</text>
<text x="17.4" y="378.4">PC4_ADC12_IN14</text>
<text x="18.4" y="383.5">PB0_ADC12_IN8</text>
<text x="67.7" y="383.5">PC15_IO 6</text>
<text x="68.7" y="378.4">PE3_IO 4</text>
<text x="68.7" y="380.9">PE4_IO 5</text>
<text x="146" y="378.4">PA0_TIM5_CH1</text>
<text x="194.9" y="378.4">PA15_TIM2_CH1</text>
<text x="341.6" y="383.5">PA10_USART1_RX</text>
<text x="18.4" y="386">PB1_ADC12_IN9</text>
<text x="67.7" y="386">PC14_IO 7</text>
<text x="67.7" y="388.5">PC13_IO 8</text>
<text x="341.6" y="386">PA9_USART1_TX</text>
<text x="371.6" y="389.8">3 USB_A_D+</text>
<text x="385.8" y="385.6" transform="rotate(-90 385.8 385.6)">MCLR</text>
<text x="393.4" y="386.5" transform="rotate(-90 393.4 386.5)">PGED1</text>
<text x="394.7" y="384.7">JP5</text>
<text x="396" y="386.5" transform="rotate(-90 396 386.5)">PGEC1</text>
<text x="371.6" y="392.3">2 USB_A_D-</text>
<text x="146" y="401.2">PB5_TIM3_CH2</text>
<text x="194.9" y="401.2">PD13_TIM4_CH2</text>
<text x="146" y="403.8">PB4_TIM3_CH1</text>
<text x="194.9" y="403.8">PD12_TIM4_CH1</text>
</g>
<text font-size="1.8" fill="#000084" x="181.1" y="338.6">GND8</text>
<g font-size="1.4" fill="#008484">
<text x="267.3" y="16.8">D33</text>
<text x="193.3" y="22.5">DIODE</text>
<text x="194.3" y="20.6">D24</text>
<text x="266.4" y="18.7">DIODE</text>
<text x="152.7" y="28.9">DIODE</text>
<text x="153.6" y="27">D23</text>
<text x="266.4" y="28.9">DIODE</text>
<text x="267.3" y="27">D34</text>
<text x="354.6" y="26.9">DIODE</text>
<text x="355.6" y="25">D35</text>
<text x="125.4" y="33.9">DIODE</text>
<text x="126.3" y="31.9">D16</text>
<text x="139.2" y="39.1">DIODE</text>
<text x="139.4" y="37.1">D20</text>
<text x="85.7" y="47.3">D12</text>
<text x="84.8" y="49.2">DIODE</text>
<text x="453.7" y="65">DIODE</text>
<text x="454.6" y="63.1">D56</text>
<text x="411.5" y="94.3">D47</text>
<text x="410.5" y="96.2">DIODE</text>
<text x="423.7" y="99.1">VI</text>
<text x="430.3" y="99.1">VO</text>
<text x="395.8" y="105.1">DIODE</text>
<text x="395.9" y="103.2">D39</text>
<text x="428.5" y="102.9" transform="rotate(-90 428.5 102.9)">GND</text>
<text x="417.5" y="124">DIODE</text>
<text x="418.4" y="122.1">D40</text>
<text x="521.6" y="125.3">DIODE</text>
<text x="522.6" y="123.4">D50</text>
<text x="418.4" y="161.5">D41</text>
<text x="417.5" y="163.4">DIODE</text>
<text x="521.6" y="164.7">DIODE</text>
<text x="522.6" y="162.8">D51</text>
<text x="417.5" y="207.2">DIODE</text>
<text x="418.4" y="205.3">D42</text>
<text x="521.6" y="208.5">DIODE</text>
<text x="522.6" y="206.6">D52</text>
<text x="102.2" y="232.6">D14</text>
<text x="101.2" y="234.5">DIODE</text>
<text x="418.4" y="244.7">D43</text>
<text x="522.6" y="245.9">D53</text>
<text x="417.5" y="246.6">DIODE</text>
<text x="521.6" y="247.9">DIODE</text>
<text x="110.2" y="288">DIODE</text>
<text x="111.1" y="286">D15</text>
<text x="417.5" y="290.4">DIODE</text>
<text x="418.4" y="288.5">D44</text>
<text x="521.6" y="291.7">DIODE</text>
<text x="522.6" y="289.8">D54</text>
<text x="417.5" y="329.8">DIODE</text>
<text x="418.4" y="327.9">D45</text>
<text x="522.6" y="329.1">D55</text>
<text x="521.6" y="331.1">DIODE</text>
</g>
<g font-size="1.4" fill="#840000">
<text x="265" y="20.9">2</text>
<text x="271.4" y="20.9">1</text>
<text x="192" y="24.7">2</text>
<text x="198.4" y="24.7">1</text>
<text x="353.3" y="29.1">1</text>
<text x="359.7" y="29.1">2</text>
<text x="136.9" y="34.8" transform="rotate(-90 136.9 34.8)">1</text>
<text x="151.4" y="31">2</text>
<text x="157.7" y="31">1</text>
<text x="265" y="31">2</text>
<text x="271.4" y="31">1</text>
<text x="124.1" y="36.1">1</text>
<text x="130.4" y="36.1">2</text>
<text x="136.9" y="41.2" transform="rotate(-90 136.9 41.2)">2</text>
<text x="83.4" y="51.4">2</text>
<text x="89.8" y="51.4">1</text>
<text x="452.4" y="67.2">1</text>
<text x="458.7" y="67.2">2</text>
<text x="393.4" y="100.9" transform="rotate(-90 393.4 100.9)">1</text>
<text x="409.2" y="98.3">2</text>
<text x="415.5" y="98.3">1</text>
<text x="393.4" y="107.2" transform="rotate(-90 393.4 107.2)">2</text>
<text x="416.2" y="126.3">1</text>
<text x="422.5" y="126.3">2</text>
<text x="520.3" y="127.6">1</text>
<text x="526.7" y="127.6">2</text>
<text x="416.2" y="165.7">1</text>
<text x="422.5" y="165.7">2</text>
<text x="520.3" y="166.9">1</text>
<text x="526.7" y="166.9">2</text>
<text x="416.2" y="209.5">1</text>
<text x="422.5" y="209.5">2</text>
<text x="520.3" y="210.7">1</text>
<text x="526.7" y="210.7">2</text>
<text x="99.9" y="236.8">1</text>
<text x="106.3" y="236.8">2</text>
<text x="416.2" y="248.8">1</text>
<text x="422.5" y="248.8">2</text>
<text x="520.3" y="250.1">1</text>
<text x="526.7" y="250.1">2</text>
<text x="108.8" y="290.1">2</text>
<text x="115.2" y="290.1">1</text>
<text x="416.2" y="292.7">1</text>
<text x="422.5" y="292.7">2</text>
<text x="520.3" y="293.9">1</text>
<text x="526.7" y="293.9">2</text>
<text x="416.2" y="332">1</text>
<text x="422.5" y="332">2</text>
<text x="520.3" y="333.3">1</text>
<text x="526.7" y="333.3">2</text>
<text x="388.4" y="382.8" transform="rotate(-90 388.4 382.8)">2</text>
<text x="388.4" y="389.2" transform="rotate(-90 388.4 389.2)">1</text>
</g>
<g font-size="1.4">
<text x="390.7" y="387.1">DIODE</text>
<text x="390.9" y="385.2">D58</text>
</g>
<g font-size="1.1" fill="#008484">
<text x="137.5" y="31.1">1</text>
<text x="148.9" y="31.1">2</text>
<text x="394.1" y="98.4">1</text>
<text x="405.5" y="98.4">2</text>
</g>
</g></defs>
<g fill="none" stroke="#840000" stroke-width=".26">
<path d="M10 10.2h574v400h-574zM12 12.2h570v396h-570zM52.1 19.2v2.6h1.2M52.1 19.2l-.8 1.3M52.1 19.2l.7 1.3M60 10.2v2M110 10.2v2M160 10.2v2M210 10.2v2M260 10.2v2M269.9 19.9v2.5M310 10.2v2"/>
<path d="M360 10.2v2M367 19.2h17.8v12.7h-17.8zM407.7 17.3l-.8 1.3M407.7 17.3v2.6M407.7 17.3l.7 1.3M410 10.2v2M411.5 19.9v5M414 19.9v5M419.1 18.6l1-.7-1-.6-1 .6 1 .7v1.3M419.1 19.9h.1M435.6 18.6l-.8 1.3M435.6 18.6v2.5"/>
<path d="M435.6 18.6l.8 1.3M444.5 18.6v5.1M460 10.2v2M510 10.2v2M536.5 11.8h.8M560 10.2v2M18.8 29.5h12.9l.7 1.1-.7 1.2h-12.9zM19.4 30.6l.7-.1v-.4l-.7-.2v1.3M19.7 30.6l.4 .6M20.2 20.6h11.5l.7 1.2-.7 1.1h-11.5zM20.8 21.7h.4M21 38.4h10.7l.7 1.1-.7 1.2h-10.7z"/>
<path d="M21.4 21h-.6v1.3h.6M22.4 39a.56 .56 0 0 0-.8 .5 .56 .56 0 0 0 .8 .5M32.4 21.8h1.3M32.4 30.6h1.3M32.4 39.5h1.3M33.7 38.5h5v2.1h-5zM33.7 29.6h5v2.1h-5zM33.7 20.7h5v2.1h-5zM38.7 21.8h8.9M38.7 30.6h8.9M38.7 39.5h8.9M42.5 38.3l2.6 1.2-2.6 1.3z"/>
<path d="M42.5 29.4l2.6 1.2-2.6 1.3zM42.5 20.5l2.6 1.3-2.6 1.2zM45.1 20.5v2.5M45.1 29.4v2.5M45.1 38.3v2.5M47.1 38v-.7h-.7h.7l-1.5 1.5M47.1 29.1v-.7h-.7h.7l-1.5 1.5M47.1 20.2v-.7h-.7h.7l-1.5 1.5M48.4 38v-.7h-.8h.8l-1.5 1.5M48.4 29.1v-.7h-.8h.8l-1.5 1.5M48.4 20.2v-.7h-.8h.8l-1.5 1.5M52.1 28.1l-.8 1.3"/>
<path d="M52.1 28.1v2.5h1.2M52.1 28.1l.7 1.3M53.3 20.7h5.1v2.1h-5.1zM53.3 29.6h5.1v2.1h-5.1zM58.4 30.6h8.9v1.3h1.3l-1.3 1.3-1.3-1.3h1.3M58.4 21.8h8.9M62.2 20.5l2.6 1.3-2.6 1.2zM62.2 29.4l2.6 1.2-2.6 1.3zM64.8 20.5v2.5M64.8 29.4v2.5M66.8 20.2v-.7h-.8h.8l-1.5 1.5M66.8 29.1v-.7h-.8h.8l-1.5 1.5"/>
<path d="M68.1 20.2v-.7h-.8h.8l-1.6 1.5M68.1 29.1v-.7h-.8h.8l-1.6 1.5M75.6 21.1v2.8M75.6 26v2.7M82.8 22.4h2v5.1h-2zM82.8 30h2v5.1h-2zM83.8 35.1v2.5h1.3l-1.3 1.3-1.3-1.3h1.3M83.8 21.1v1.3M83.8 27.5v2.5M99.7 31.3h5.1M104.8 28.7h10.1v15.3h-10.1zM104.8 36.4h-5.1v1.2h1.3l-1.3 1.3-1.3-1.3h1.3"/>
<path d="M106 21.1h2.8M110.9 21.1h2.8M114.9 31.3h5.1M114.9 36.4h5.1M126.4 36.4h-3.8v2.8M126.4 35.1v2.5M132.7 33.8v2.6h-3.8M132.7 33.8l-.7 1.3M132.7 33.8l.8 1.3M135.9 36.4h2.5M137.2 31.3h1.2a1.27 1.27 0 0 1 1.3-1.3 1.27 1.27 0 0 1 1.3 1.3 1.27 1.27 0 0 1 1.2-1.3 1.27 1.27 0 0 1 1.3 1.3 1.27 1.27 0 0 1 1.3-1.3 1.27 1.27 0 0 1 1.2 1.3 1.27 1.27 0 0 1 1.3-1.3 1.27 1.27 0 0 1 1.3 1.3h5.1M137.2 32.6v3.8"/>
<path d="M137.2 38.9v3.8M146.4 20h13l.6 1.1-.6 1.1h-13zM147 21.1l.7-.1v-.5l-.7-.1v1.3M147.3 21.1l.5 .6M149.9 33.8v2.8M149.9 38.7v2.7M156.2 31.3h3.8M156.2 30v2.6M167.6 22.4v2.5h5.1M167.6 26.8v2.8M167.6 31.7v2.8M167.6 22.4l-.7 1.3"/>
<path d="M167.6 22.4l.8 1.3M172.7 22.4h12.7v8.9h-12.7zM179.1 31.3v6.3h1.2l-1.2 1.3-1.3-1.3h1.3M185.4 24.9h8.9M190.5 26.8v2.8M190.5 31.7v2.8M196.8 23.7v2.5M200.7 22.4v2.5h-3.9M200.7 22.4l-.8 1.3M200.7 22.4l.7 1.3M202.6 32.7h10.8l.6 1.1-.6 1.1h-10.8zM204 33.2a.56 .56 0 0 0-.8 .5 .56 .56 0 0 0 .8 .6"/>
<path d="M216.5 28.7v1.3h1.3l-1.3 1.3-1.2-1.3h1.2M219.1 28.7h2.5M219.1 33.8h2.5M221.6 29.3l4.1 1.7M224.2 28.2v2.1M225.5 20h10.7l.7 1.1-.7 1.1h-10.7zM226.7 31.3h7.9M226.8 20.5a.56 .56 0 0 0-.7 .5 .56 .56 0 0 0 .7 .6M234.6 29.4v3.8M235.1 29.5h2.5v3.6h-.7M235.1 29v1M235.1 30.8v1"/>
<path d="M235.1 32.6v1M235.1 33.1h1.8M236.9 26.2v5.1h-1.8M236.9 33.1v3.3M237.2 31h.8l-.4 .7zM238.1 31.5l-1 .3M247.6 33.8v2.6M247.6 33.8l-.7 1.3M247.6 33.8l.8 1.3M249.9 20h13l.6 1.1-.6 1.1h-13zM250.5 21.1l.7-.1v-.5l-.7-.1v1.3M250.9 21.1l.4 .6"/>
<path d="M251.3 25.1h11.6l.6 1.1-.6 1.1h-11.6zM251.9 26.1h.5M252.6 25.5h-.7v1.3h.7M262.5 32.6h2v5h-2zM263.5 37.6v2.6h1.3l-1.3 1.2-1.2-1.2h1.2M263.5 21.1h3.8M266.1 26.2h5.3M267.3 31.3h-3.8v1.3M269.9 21.1h3.8v5.1h-1.8M269.9 30v2.6M271.4 24.3v3.8M271.9 24.4h2.5v3.6h-.7"/>
<path d="M271.9 28h1.8M271.9 23.9v1M271.9 25.7v1M271.9 27.5v1M273.7 28v3.3h-3.8M274.1 26h.7l-.4 .6zM275 26.5l-1.1 .2M277.5 30.2h10.7v2.2h-10.7l-.6-1.1zM286.9 30.6l.4 1.2 .5-1.2M290.7 23.2h11.6l.6 1.1-.6 1.1h-11.6zM291.3 24.2h.4M291.9 23.6h-.6v1.3h.6"/>
<path d="M302.9 23l1-.6-1-.6-1 .6 1 .6v1.3M302.9 24.3h.1M306.7 21.8v1.2h1.3l-1.3 1.3-1.3-1.3h1.3M308 21.8h3.8M308 24.3h3.8M311.8 20.5h2.5v5.1h-2.5zM311.8 24.2h1.3v.2h-1.3zM311.8 21.6h1.3v.3h-1.3zM343.5 26.8v2.6M343.5 26.8l-.7 1.3M343.5 26.8l.8 1.3M351.8 28.1l1-.6-1-.7-1 .7 1 .6v1.3"/>
<path d="M351.8 29.4h.1M351.8 29.4h3.8M355.6 28.1v2.5M358.1 29.4h8.9M360.2 30.9h1M360.7 30.4v1M361.9 33.7v4.6h1.3l-1.3 1.2-1.2-1.2h1.2M361.9 21.8h5.1M361.9 25.6h5.1M361.9 29.4v2.8M384.8 21.8h5.1M384.8 25.6h5.1"/>
<path d="M384.8 29.4h5.1M389.4 30.9h1M389.9 30.4v1M391.2 29.4v2.8M391.2 33.7v3.3M393.1 28.3h4.4v2.2h-4.4l-.7-1.1zM396.5 29.1h.5M396.7 28.7v1.1l.3 .1M400 39l.3-.7h2l-.2 .7M400.8 38.3l-.2 .7M401.3 37v1.3l-.2 .7M401.8 38.3l-.2 .7"/>
<path d="M408.9 24.9h7.7v10.2h-7.7zM411.5 35.1v5.1M414 35.1v5.1M423.5 39.1h11.9v2.2h-11.9l-.6-1.1zM437.5 21.1h3.8M443.9 21.1h3.8M447.7 28.7h2.5M452.8 25.7v2M455.3 31.3h2.5M455.3 26.2h2.5M455.3 26.7l-4.1 1.8M458.1 32.6h2v5h-2z"/>
<path d="M459.1 37.6v2.6l-.2 .7M459.1 31.3v1.3M460.4 26.2h5.3M464.8 35.1l1-.6-1-.7-1 .7 1 .6v1.3M464.8 36.4h.1M465.7 24.3v3.8M466.2 24.4h2.6v3.6h-.8M466.2 23.9v1M466.2 25.7v1M466.2 27.5v1M466.2 28h1.8M468 21.1v5.1h-1.8"/>
<path d="M468 28v3.3M468.4 26h.7l-.3 .6zM468.6 35.2h4.5v2.3h-4.5l-.6-1.1zM469.3 26.5l-1.1 .2M472.1 36.1h.5M472.3 35.7v1l.3 .2M495.9 25.6h3.8M495.9 23h3.8M495.9 34.5h3.8M495.9 37h3.8M499.7 21.8h2.6v5h-2.6zM499.7 25.4h1.3v.3h-1.3z"/>
<path d="M499.7 22.9h1.3v.3h-1.3zM499.7 33.2h2.6v5.1h-2.6zM499.7 36.9h1.3v.2h-1.3zM499.7 34.3h1.3v.3h-1.3zM515 20.5l-.8 1.3M515 20.5v2.5M515 31.9v2.6M515 20.5l.7 1.3M515 31.9l-.8 1.3M515 31.9l.7 1.3M517.5 36.5l.3-.8h2l-.2 .8M517.5 25.1l.3-.8h2l-.2 .8"/>
<path d="M518.3 35.7l-.3 .8M518.3 24.3l-.3 .8M518.8 25.6h3.8M518.8 37h3.8M519.3 35.7l-.3 .8M519.3 24.3l-.3 .8M522.6 21.8h2.5v5h-2.5zM522.6 25.4h1.3v.3h-1.3zM522.6 22.9h1.3v.3h-1.3zM522.6 33.2h2.5v5.1h-2.5zM522.6 36.9h1.3v.2h-1.3zM522.6 34.3h1.3v.3h-1.3z"/>
<path d="M522.6 34.5h-3.8v1.2l-.3 .8M522.6 23h-3.8v1.3l-.3 .8M32.4 45.9v2.5h1.3M32.4 45.9l-.8 1.3M32.4 45.9l.7 1.3M33.7 47.4h5v2h-5zM38.7 48.4h8.9v1.3h1.3l-1.3 1.3-1.2-1.3h1.2M42.5 47.2l2.6 1.2-2.6 1.3zM45.1 47.2v2.5M47.1 46.9v-.8h-.7h.7l-1.5 1.6M48.4 46.9v-.8h-.8h.8l-1.5 1.6M57.1 47.8h2.6v12.7h-2.6z"/>
<path d="M58.4 59.1h1.3v.3h-1.3zM58.4 56.6h1.3v.2h-1.3zM58.4 51.5h1.3v.2h-1.3zM58.4 48.9h1.3v.3h-1.3zM58.4 54h1.3v.3h-1.3zM59.7 49.1h3.8M59.7 51.6h3.8M59.7 54.1h3.8M59.7 56.7h3.8M59.7 59.2h3.8M65.4 49.1v1.2h1.3l-1.3 1.3-1.3-1.3h1.3M66.7 51.6h4.2"/>
<path d="M71.8 50.3a3.2 3.2 0 0 1 5 0M77.7 51.6h8M88.3 50.3v2.6M92.1 49.1v2.5h-3.8M92.1 49.1l-.8 1.2M92.1 49.1l.7 1.2M99.7 41.4h5.1M114.9 41.4h5.1M122.6 41.2v2.8M149.9 44v1.3h1.2l-1.2 1.2-1.3-1.2h1.3M221 49.7v5.3M221 57.1v2.8"/>
<path d="M221 49.7l-.8 1.3M221 49.7l.7 1.3M229.9 52.2v2.8M229.9 57.1v2.8M238.8 52.2v2.8M238.8 57.1v2.8M247.6 52.2v2.8M247.6 57.1v2.8M256.5 52.2v2.8M256.5 57.1v2.8M265.4 52.2v2.8M265.4 57.1v2.8"/>
<path d="M274.3 52.2v2.8M274.3 57.1v2.8M283.2 52.2v2.8M283.2 57.1v2.8M292.1 57.1v4h1.3l-1.3 1.3-1.3-1.3h1.3M292.1 52.2v2.8M367.8 58.1h11.9l.7 1.1-.7 1.1h-11.9zM380.4 47.8v2.5h1.2M380.4 47.8l-.8 1.3M380.4 47.8l.7 1.3M381.6 49.3h5.1v2.1h-5.1zM386.7 50.3h8.9"/>
<path d="M390.5 49.1l2.6 1.2-2.6 1.3zM393.1 49.1v2.5M395.1 48.8v-.8h-.8h.8l-1.5 1.6M396.4 48.8v-.8h-.8h.8l-1.6 1.6M401.3 56.7v2.5h1.3M401.3 56.7l-.7 1.3M401.3 47.8v2.5h1.3M401.3 56.7l.8 1.3M401.3 47.8l-.7 1.3M401.3 47.8l.8 1.3M402.6 58.2h5.1v2h-5.1zM402.6 49.3h5.1v2.1h-5.1z"/>
<path d="M407.7 59.2h8.9v1.3l-.3 .8M407.7 50.3h8.9M411.5 58l2.5 1.2-2.5 1.3zM411.5 49.1l2.5 1.2-2.5 1.3zM414 49.1v2.5M414 58v2.5M416.1 57.7v-.8h-.8h.8l-1.6 1.6M416.1 48.8v-.8h-.8h.8l-1.6 1.6M417.3 57.7v-.8h-.7h.7l-1.5 1.6M417.3 48.8v-.8h-.7h.7l-1.5 1.6M433.9 49.2h11.9l.6 1.1-.6 1.2h-11.9zM436.9 56h2.5v5.1h-2.5z"/>
<path d="M438.1 59.7h1.3v.3h-1.3zM438.1 57.2h1.3v.2h-1.3zM439.4 59.9h3.8M443.2 54.8v2.5h-3.8M443.2 54.8l-.7 1.2M443.2 54.8l.8 1.2M446.4 59.9h8.9M451.5 49.7h10.1v12.7h-10.1zM455.3 57.3h2.5v3.8h-2.5zM457.8 40.9l.3-.7h2l-.2 .7M457.8 59.9h8.9M457.8 57.3l-2.5 3.8"/>
<path d="M458.6 40.2l-.3 .7M459.1 53.5v1.3h7.6M459.1 51l-3.8 1.2h-8.9M459.6 40.2l-.2 .7M461.6 52.2h5.1M467.4 53.7h11.7v2.2h-11.7l-.7-1.1zM495.9 57.3h3.8M495.9 59.9h3.8M495.9 48.4h3.8M495.9 45.9h3.8M499.7 44.6h2.6v5.1h-2.6zM499.7 48.3h1.3v.3h-1.3z"/>
<path d="M499.7 45.8h1.3v.2h-1.3zM499.7 56h2.6v5.1h-2.6zM499.7 59.7h1.3v.3h-1.3zM499.7 57.2h1.3v.2h-1.3zM553.7 51.6h12.7v12.7h-12.7zM10 60.2h2M22.2 77.6v2.8M22.9 77.6h1.9M28.6 77.6h1.9M31.1 77.6v2.8M47 77.3h5.1v2h-5.1zM47 78.3h-1.3v1.2h1.3l-1.3 1.3-1.3-1.3h1.3"/>
<path d="M52.1 78.3h8.9M61 74.5h238.7v137.1h-238.7zM123.2 64.3v10.2M123.2 64.3l-.8 1.3M123.2 64.3l.8 1.3M135.9 66.8v7.7M161.3 66.8v7.7M168.9 66.8v7.7M176.5 66.8v7.7M184.1 66.8v7.7M191.8 66.8v7.7M199.4 66.8v7.7"/>
<path d="M212.1 66.8v7.7M299.7 78.3h7.6M368 75.9h11.7l.7 1.1-.7 1.1h-11.7zM375.3 67h4.4l.7 1.1-.7 1.1h-4.4zM380.4 77h1.2M380.4 68.1h1.2M381.6 76h5.1v2h-5.1zM381.6 67.1h5.1v2h-5.1zM386.7 77h8.9v1.3l-.2 .7M386.7 68.1h8.9M390.5 75.7l2.6 1.3-2.6 1.3zM390.5 66.8l2.6 1.3-2.6 1.3z"/>
<path d="M393.1 66.8v2.6M393.1 75.7v2.6M394.3 79l.3-.7h2l-.2 .7M395.1 75.5v-.8h-.8h.8l-1.5 1.5M395.1 78.3l-.3 .7M395.1 66.6v-.8h-.8h.8l-1.5 1.6M396.1 78.3l-.2 .7M396.4 75.5v-.8h-.8h.8l-1.6 1.5M396.4 66.6v-.8h-.8h.8l-1.6 1.6M415.3 61.3l.2-.8h2.1l-.3 .8M416.1 60.5l-.3 .8M417.1 60.5l-.3 .8"/>
<path d="M447.7 75.7h2.5M450.2 76.2l4.1 1.8M450.8 67.5h3.9M452.8 75.2v2.1M454.7 66.2v2.5M455.3 78.3h2.5M457.2 67.5h3.8M457.5 79.5h2v5.1h-2zM458.5 78.3v1.2M459.1 78.3h5.3M464.4 76.4v3.8M464.9 78.3h1.8v5.1"/>
<path d="M464.9 76v1M464.9 77.8v1M464.9 79.5v1.1M464.9 76.5h1.8M466.7 76.5h.8v3.6h-2.6M466.7 73.2v3.3M467 77.8l1 .2M467.5 77.9l.4 .6h-.8zM476.9 72.6a3.2 3.2 0 0 0 0 5M478.2 67.5v4.2M478.2 78.5v4.2M495.9 68.7h3.8"/>
<path d="M495.9 71.3h3.8M499.7 78.9h2.6v5.1h-2.6zM499.7 67.5h2.6v5.1h-2.6zM499.7 71.2h1.3v.2h-1.3zM499.7 68.6h1.3v.3h-1.3zM553.7 66.8h12.7v12.7h-12.7zM582 60.2h2M21.6 99.9h2.5M22.2 82.5v2.8M24.1 98.6h5.1M26.7 85.3v1.2h1.2l-1.2 1.3-1.3-1.3h1.3M26.7 96.8v1.8"/>
<path d="M29.2 99.9h2.5M31.1 82.5v2.8M53.3 83.4h7.7M53.3 88.4h7.7M299.7 98.6h7.6M299.7 83.4h7.6M299.7 88.4h7.6M299.7 85.9h7.6M299.7 96.1h7.6M299.7 91h7.6M299.7 93.5h7.6M299.7 80.8h7.6"/>
<path d="M351.8 98.6h5.1M356.9 96.1h10.1v10.1h-10.1zM358.1 87.8h2.8M363 87.8h2.8M367 98.6h5.1M406.4 98.6h-1.3a1.27 1.27 0 0 0-1.2-1.3 1.27 1.27 0 0 0-1.3 1.3 1.27 1.27 0 0 0-1.3-1.3 1.27 1.27 0 0 0-1.3 1.3 1.27 1.27 0 0 0-1.2-1.3 1.27 1.27 0 0 0-1.3 1.3 1.27 1.27 0 0 0-1.3-1.3 1.27 1.27 0 0 0-1.2 1.3h-1.3v3.8M407 99.9v2.8M407.7 98.6h3.8M414 98.6h8.9M414 97.3v2.6M417.8 96.1l-.7 1.2M417.8 96.1v5.3"/>
<path d="M417.8 96.1l.8 1.2M422.9 96.1h10.2v7.6h-10.2zM433.1 98.6h5M438.1 96.1v5.3M438.1 96.1l-.7 1.2M438.1 96.1l.8 1.2M447.7 80.8h2.5M458.5 84.6v1.3M476.9 87.9l.2-.7h2.1l-.3 .7M477.6 87.2l-.2 .7M478.2 85.9v1.3l-.3 .7M478.7 87.2l-.3 .7"/>
<path d="M495.9 80.2h3.8M495.9 82.7h3.8M499.7 82.6h1.3v.2h-1.3zM499.7 80.1h1.3v.2h-1.3zM10 110.2h2M22.9 107.5h2.8M27.7 107.5h2.8M31.7 107.5v1.3h1.3l-1.3 1.2-1.2-1.2h1.2M53.3 103.7h7.7M299.7 103.7h7.6M299.7 101.1h7.6M299.7 106.2h7.6"/>
<path d="M299.7 108.8h7.6M299.7 111.3h7.6M299.7 113.8h7.6M299.7 116.4h7.6M335.3 113.3l.2-.7h2.1l-.3 .7M335.5 104.9h2.1v5.1h-2.1zM336 112.6l-.2 .7M336.5 110v2.6l-.2 .7M336.5 103.7v1.2M337.1 112.6l-.3 .7M342.5 104.9h2.1v5.1h-2.1zM343.5 103.7v1.2"/>
<path d="M343.5 110v1.3M350.5 103.2l.3-.8h2l-.2 .8M351.3 102.4l-.3 .8M351.8 108.5v2.8M352.3 102.4l-.3 .8M356.9 101.1h-5.1v1.3l-.3 .8M356.9 103.7h-5.1v2.8M367 103.7h5.1M367 101.1h5.1M374.6 101.1v2.8M374.6 106v2.8M382.4 102.7h1"/>
<path d="M382.9 102.2v1M384.2 101.1v2.8M384.2 105.5v3.3M384.8 116.4v5.3M384.8 116.4l-.8 1.2M384.8 116.4l.8 1.2M385.4 100h4.5v2.3h-4.5l-.6-1.2zM388.9 100.9h.5M389.1 100.4v1.1l.3 .2M392.4 102.4h2.6M393.7 104.9v3.9M407 104.7v2.8"/>
<path d="M417.8 103.4v2.8M426.7 110.8l.3-.8h2l-.2 .8M427.5 110l-.3 .8M428 108.8v1.2l-.3 .8M428 103.7v2.5M428.5 110l-.3 .8M438.1 103.4v2.8M488.9 117.6v5.4M488.9 117.6l-.7 1.3M488.9 117.6l.8 1.3M489.9 100.7h11.7l.7 1.1-.7 1.1h-11.7zM502.4 103.3h1"/>
<path d="M502.9 102.8v1M504.2 101.8v2.8M504.2 106.1v3.3M512.6 103.3h1M513.1 102.8v1M514.3 101.8v2.8M514.3 106.1v3.3M524.5 101.8v2.8M524.5 106.6v2.8M532.8 111.4l.2-.7h2.1l-.3 .7M533.5 110.7l-.2 .7M534 106.6v4.1l-.2 .7"/>
<path d="M534 101.8v2.8M534.5 110.7l-.2 .7M582 110.2h2M53.3 124h7.7M53.3 126.5h7.7M53.3 129.1h7.7M53.3 131.6h7.7M53.3 134.2h7.7M53.3 136.7h7.7M53.3 139.2h7.7M299.7 124h7.6M299.7 126.5h7.6"/>
<path d="M299.7 129.1h7.6M299.7 131.6h7.6M299.7 134.2h7.6M299.7 136.7h7.6M299.7 139.2h7.6M371.7 137.3h2.1v5.1h-2.1zM372.7 131v2.5M372.7 136.1v1.2M372.7 131l-.7 1.2M372.7 131l.8 1.2M383.5 128.6l.3-.8h2l-.2 .8M384.3 127.8l-.3 .8"/>
<path d="M384.8 123.7v4.1l-.2 .8M385.3 127.8l-.2 .8M388.6 138.6h2.6M388.6 133.5h2.6M391.2 131h17.7v20.3h-17.7zM408.9 138.6h2.6M408.9 133.5h2.6M414.7 134.8v2.8M414.7 139.6v2.8M414.7 126.5h3.8M417.2 138.6h1.3M418.5 137.6h5v2h-5z"/>
<path d="M418.5 125.3v2.5M423.5 138.6h1.3M424.8 124l-.7 1.3M424.8 124v2.5h-3.8M424.8 124l.8 1.3M431.8 134.8h5.1M431.8 137.3h5.1M436.9 129.7h17.8v22.9h-17.8zM436.9 139.9h-5.1v1.2l-.3 .8M454.7 134.8h5M454.7 139.9h5M454.7 137.3h5"/>
<path d="M454.7 132.2h5M460.4 131.1h11.7v2.3h-11.7l-.7-1.2zM475.9 138.6h2v5.1h-2zM476.9 132.2v2.6M476.9 137.3v1.3M476.9 132.2l-.8 1.3M476.9 132.2l.7 1.3M487.7 129.8l.2-.7h2.1l-.3 .7M488.4 129.1l-.2 .7M488.9 125v4.1l-.2 .7M489.5 129.1l-.3 .7M492.8 134.8h2.5"/>
<path d="M492.8 139.9h2.5M495.3 132.2h17.8v20.4h-17.8zM513.1 134.8h2.5M513.1 139.9h2.5M518.8 127.8h3.8M518.8 136.1v2.8M521.3 139.9h1.3M522.6 138.9h5.1v2h-5.1zM522.6 126.5v2.6M527.7 139.9h1.3M529 125.3v2.5h-3.9M529 125.3l-.8 1.2"/>
<path d="M529 125.3l.7 1.2M535.9 136.1h5.1M535.9 138.6h5.1M541 131h17.8v22.8h-17.8zM558.8 136.1h5.1M558.8 138.6h5.1M558.8 133.5h5.1M564.5 132.4h11.8v2.2h-11.8l-.6-1.1zM53.3 141.8h7.7M53.3 144.3h7.7M53.3 146.9h7.7M53.3 149.4h7.7"/>
<path d="M53.3 151.9h7.7M53.3 154.5h7.7M53.3 157h7.7M53.3 159.6h7.7M299.7 141.8h7.6M299.7 144.3h7.6M299.7 146.9h7.6M299.7 149.4h7.6M299.7 151.9h7.6M299.7 154.5h7.6M299.7 157h7.6M299.7 159.6h7.6"/>
<path d="M372.7 142.4v1.3M384.8 155.7v5.4M384.8 155.7l-.8 1.3M384.8 155.7l.8 1.3M387.3 153.3l.3-.7h2l-.2 .7M388.1 152.6l-.2 .7M388.6 151.3v1.3l-.2 .7M388.6 148.8h2.6M388.6 143.7h2.6M389.1 152.6l-.2 .7M408.9 148.8h2.6M408.9 143.7h2.6"/>
<path d="M417.2 148.8h1.3M418.5 147.7h5v2.1h-5zM423.5 148.8h1.3M430.5 141.9l.3-.8h2l-.2 .8M431.3 141.1l-.3 .8M431.8 144.9h5.1M431.8 147.5h5.1M431.8 142.4h5.1M432.3 141.1l-.2 .8M454.7 144.9h5M454.7 150h5M454.7 147.5h5"/>
<path d="M454.7 142.4h5M476.9 143.7v1.2M488.9 157v5.3M488.9 157l-.7 1.3M488.9 157l.8 1.3M491.5 154.6l.2-.8h2.1l-.3 .8M492.3 153.8l-.3 .8M492.8 152.6v1.2l-.3 .8M492.8 144.9h2.5M492.8 150h2.5M493.3 153.8l-.3 .8M513.1 144.9h2.5"/>
<path d="M513.1 150h2.5M518.8 140.9v2.8M521.3 150h1.3M522.6 149h5.1v2h-5.1zM527.7 150h1.3M534.7 143.2l.2-.8h2.1l-.3 .8M535.4 142.4l-.2 .8M535.9 146.2h5.1M535.9 148.8h5.1M535.9 143.7h5.1M536.4 142.4l-.2 .8M541 141.1h-5.1v1.3l-.2 .8"/>
<path d="M558.8 141.1h5.1M558.8 146.2h5.1M558.8 148.8h5.1M558.8 143.7h5.1M558.8 151.3h5.1M10 160.2h2M53.3 169.7h7.7M53.3 172.3h7.7M53.3 174.8h7.7M53.3 177.3h7.7M53.3 179.9h7.7M53.3 162.1h7.7"/>
<path d="M299.7 169.7h7.6M299.7 172.3h7.6M299.7 174.8h7.6M299.7 177.3h7.6M299.7 179.9h7.6M299.7 162.1h7.6M371.1 176.7h2v5.1h-2zM372.1 170.3v2.6M372.1 175.4v1.3M372.1 170.3l-.8 1.3M372.1 170.3l.8 1.3M383.5 167.9l.3-.7h2l-.2 .7"/>
<path d="M384.3 167.2l-.3 .7M384.8 163.1v4.1l-.2 .7M385.3 167.2l-.2 .7M388.6 178h2.6M388.6 172.9h2.6M391.2 170.3h17.7v20.4h-17.7zM408.9 178h2.6M408.9 172.9h2.6M414.7 174.2v2.8M414.7 179v2.8M414.7 165.9h3.8M417.2 178h1.3"/>
<path d="M418.5 177h5v2h-5zM418.5 164.6v2.6M423.5 178h1.3M424.8 163.4v2.5h-3.8M424.8 163.4l-.7 1.2M424.8 163.4l.8 1.2M431.8 174.2h5.1M431.8 176.7h5.1M436.9 169.1h17.8v22.8h-17.8zM436.9 179.2h-5.1v1.3l-.3 .8M454.7 174.2h5M454.7 179.2h5"/>
<path d="M454.7 176.7h5M454.7 171.6h5M460.4 170.5h11.7v2.2h-11.7l-.7-1.1zM475.2 178h2.1v5h-2.1zM476.2 171.6v2.6M476.2 176.7v1.3M476.2 171.6l-.7 1.3M476.2 171.6l.8 1.3M487.7 169.2l.2-.8h2.1l-.3 .8M488.4 168.4l-.2 .8M488.9 164.4v4l-.2 .8M489.5 168.4l-.3 .8"/>
<path d="M492.8 174.2h2.5M492.8 179.2h2.5M495.3 171.6h17.8v20.3h-17.8zM513.1 174.2h2.5M513.1 179.2h2.5M518.8 175.4v2.8M518.8 167.2h3.8M521.3 179.2h1.3M522.6 178.2h5.1v2.1h-5.1zM522.6 165.9v2.5M527.7 179.2h1.3M529 164.6v2.6h-3.9"/>
<path d="M529 164.6l-.8 1.3M529 164.6l.7 1.3M535.9 175.4h5.1M535.9 178h5.1M541 170.3h17.8v22.9h-17.8zM558.8 175.4h5.1M558.8 178h5.1M558.8 172.9h5.1M564.5 171.8h11.8v2.2h-11.8l-.6-1.1zM582 160.2h2M53.3 182.4h7.7M53.3 195.1h7.7"/>
<path d="M53.3 197.7h7.7M53.3 185h7.7M53.3 187.5h7.7M53.3 190h7.7M53.3 192.6h7.7M299.7 182.4h7.6M299.7 195.1h7.6M299.7 197.7h7.6M299.7 185h7.6M299.7 187.5h7.6M299.7 190h7.6M299.7 192.6h7.6"/>
<path d="M372.1 181.8v1.2M384.8 199.6v5.3M384.8 199.6l-.8 1.2M384.8 199.6l.8 1.2M387.3 192.7l.3-.8h2l-.2 .8M388.1 191.9l-.2 .8M388.6 190.7v1.2l-.2 .8M388.6 188.1h2.6M388.6 183h2.6M389.1 191.9l-.2 .8M408.9 188.1h2.6M408.9 183h2.6"/>
<path d="M417.2 188.1h1.3M418.5 187.1h5v2h-5zM423.5 188.1h1.3M430.5 181.3l.3-.8h2l-.2 .8M431.3 180.5l-.3 .8M431.8 184.3h5.1M431.8 186.9h5.1M431.8 181.8h5.1M432.3 180.5l-.2 .8M454.7 184.3h5M454.7 189.4h5M454.7 186.9h5"/>
<path d="M454.7 181.8h5M476.2 183v1.3M491.5 194l.2-.8h2.1l-.3 .8M492.3 193.2l-.3 .8M492.8 191.9v1.3l-.3 .8M492.8 184.3h2.5M492.8 189.4h2.5M493.3 193.2l-.3 .8M513.1 184.3h2.5M513.1 189.4h2.5M518.8 180.3v2.7M521.3 189.4h1.3"/>
<path d="M522.6 188.4h5.1v2h-5.1zM527.7 189.4h1.3M534.7 182.5l.2-.7h2.1l-.3 .7M535.4 181.8l-.2 .7M535.9 185.6h5.1M535.9 188.1h5.1M535.9 183h5.1M536.4 181.8l-.2 .7M541 180.5h-5.1v1.3l-.2 .7M558.8 180.5h5.1M558.8 185.6h5.1M558.8 188.1h5.1"/>
<path d="M558.8 183h5.1M558.8 190.7h5.1M10 210.2h2M53.3 200.2h7.7M53.3 202.7h7.7M53.3 205.3h7.7M53.3 207.8h7.7M170.2 211.6v7.6M175.3 211.6v7.6M180.3 211.6v7.6M185.4 211.6v7.6M190.5 211.6v7.6"/>
<path d="M203.2 211.6v10.4M215.9 211.6v10.4M299.7 200.2h7.6M299.7 202.7h7.6M299.7 205.3h7.6M299.7 207.8h7.6M321.3 216.7v5.3M321.3 216.7l-.8 1.3M321.3 216.7l.8 1.3M354.3 216.7v5.3M354.3 216.7l-.7 1.3M354.3 216.7l.8 1.3"/>
<path d="M372.7 214.2v2.5M372.7 219.2v1.3M372.7 214.2l-.7 1.2M372.7 214.2l.8 1.2M383.5 211.8l.3-.8h2l-.2 .8M384.3 211l-.3 .8M384.8 206.9v4.1l-.2 .8M385.3 211l-.2 .8M388.6 216.7h2.6M391.2 214.2h17.7v20.3h-17.7zM408.9 216.7h2.6M414.7 218v2.8"/>
<path d="M414.7 209.7h3.8M418.5 208.4v2.6M424.8 207.2v2.5h-3.8M424.8 207.2l-.7 1.2M424.8 207.2l.8 1.2M431.8 218h5.1M436.9 212.9h17.8v22.9h-17.8zM454.7 218h5M454.7 215.4h5M460.4 214.3h11.7v2.3h-11.7l-.7-1.2zM476.9 215.4v2.6M476.9 215.4l-.8 1.3"/>
<path d="M476.9 215.4l.7 1.3M487.7 213l.2-.7h2.1l-.3 .7M488.4 212.3l-.2 .7M488.9 208.2v4.1l-.2 .7M488.9 200.8v5.4M488.9 200.8l-.7 1.3M488.9 200.8l.8 1.3M489.5 212.3l-.3 .7M492.8 218h2.5M495.3 215.4h17.8v20.4h-17.8zM513.1 218h2.5M518.8 219.2v2.8"/>
<path d="M518.8 211h3.8M522.6 209.7v2.6M529 208.4v2.6h-3.9M529 208.4l-.8 1.3M529 208.4l.7 1.3M535.9 219.2h5.1M541 214.2h17.8v22.8h-17.8zM558.8 216.7h5.1M558.8 219.2h5.1M564.5 215.6h11.8v2.2h-11.8l-.6-1.1zM582 210.2h2M21.6 235.1l-.8 1.3"/>
<path d="M21.6 235.1v2.6M21.6 235.1l.8 1.3M42.5 235.1l-.7 1.3M42.5 235.1v2.6M42.5 235.1l.8 1.3M98.4 237h3.8M102.2 235.8v2.5M104.8 237h3.8M109.2 234.5l-.7 1.3M109.2 234.5v2.5M109.2 234.5l.8 1.3M109.9 237h2.5"/>
<path d="M112.4 235.8h3.6v5h-3.6zM112.4 239.6h-2.5v1.2M116 235.8l2.5-2.6v10.2l-2.5-2.6M141 237.7v2.5M141 237.7l-.8 1.2M141 237.7l.7 1.2M163.2 237.7h5.1M168.3 235.1h12.7v25.4h-12.7zM203.2 224.1v2.8M215.9 224.1v4h1.3l-1.3 1.3-1.3-1.3h1.3M261.9 233.2h2v5.1h-2zM262.9 229.4v3.8"/>
<path d="M262.9 238.3v1.3M262.9 229.4l-.8 1.3M262.9 229.4l.8 1.3M272 233.2h2.1v5.1h-2.1zM273 229.4v3.8M273 238.3v1.3M273 229.4l-.7 1.3M273 229.4l.8 1.3M283.5 233.2h2v5.1h-2zM284.5 229.4v3.8M284.5 238.3v1.3M284.5 229.4l-.8 1.3"/>
<path d="M284.5 229.4l.7 1.3M294.9 233.2h2v5.1h-2zM295.9 229.4v3.8M295.9 238.3v1.3M295.9 229.4l-.8 1.3M295.9 229.4l.8 1.3M321.3 224.1v4h1.3l-1.3 1.3-1.3-1.3h1.3M324.5 228.1v2.6h5.1M324.5 228.1l-.8 1.3M324.5 228.1l.7 1.3M324.5 234.5h5.1M324.5 238.3h5.1"/>
<path d="M329.6 228.1h15.2v31.8h-15.2zM344.8 234.5h5.1M344.8 238.3h5.1M349.9 228.1v2.6h-5.1M349.9 228.1l-.8 1.3M349.9 228.1l.7 1.3M353.1 228.9l.2-.8h2l-.2 .8M353.8 228.1l-.2 .8M354.3 224.1v4l-.2 .8M354.8 228.1l-.2 .8M371.7 220.5h2.1v5.1h-2.1zM372.7 225.6v1.3"/>
<path d="M384.8 238.9v5.4M384.8 238.9l-.8 1.3M384.8 238.9l.8 1.3M387.3 236.5l.3-.7h2l-.2 .7M388.1 235.8l-.2 .7M388.6 234.5v1.3l-.2 .7M388.6 231.9h2.6M388.6 221.8h2.6M388.6 226.9h2.6M389.1 235.8l-.2 .7M408.9 231.9h2.6M408.9 221.8h2.6"/>
<path d="M408.9 226.9h2.6M414.7 222.8v2.8M417.2 231.9h1.3M417.2 221.8h1.3M418.5 230.9h5v2.1h-5zM418.5 220.8h5v2h-5zM423.5 231.9h1.3M423.5 221.8h1.3M430.5 225.1l.3-.8h2l-.2 .8M431.3 224.3l-.3 .8M431.8 228.1h5.1M431.8 230.7h5.1"/>
<path d="M431.8 220.5h5.1M431.8 225.6h5.1M432.3 224.3l-.2 .8M436.9 223.1h-5.1v1.2l-.3 .8M454.7 223.1h5M454.7 228.1h5M454.7 233.2h5M454.7 230.7h5M454.7 220.5h5M454.7 225.6h5M475.9 221.8h2v5.1h-2zM476.9 220.5v1.3"/>
<path d="M476.9 226.9v1.2M491.5 237.8l.2-.8h2.1l-.3 .8M492.3 237l-.3 .8M492.8 235.8v1.2l-.3 .8M492.8 223.1h2.5M492.8 228.1h2.5M492.8 233.2h2.5M493.3 237l-.3 .8M513.1 223.1h2.5M513.1 228.1h2.5M513.1 233.2h2.5M518.8 224.1v2.8"/>
<path d="M521.3 223.1h1.3M521.3 233.2h1.3M522.6 222h5.1v2.1h-5.1zM522.6 232.2h5.1v2h-5.1zM527.7 223.1h1.3M527.7 233.2h1.3M534.7 226.4l.2-.8h2.1l-.3 .8M535.4 225.6l-.2 .8M535.9 231.9h5.1M535.9 221.8h5.1M535.9 226.9h5.1M535.9 229.4h5.1"/>
<path d="M536.4 225.6l-.2 .8M541 224.3h-5.1v1.3l-.2 .8M558.8 231.9h5.1M558.8 221.8h5.1M558.8 226.9h5.1M558.8 224.3h5.1M558.8 229.4h5.1M558.8 234.5h5.1M21.6 256.1v5.3M21.6 242.1h2.8M21.6 256.1l-.8 1.2M21.6 256.1l.8 1.2"/>
<path d="M26.4 242.1h2.8M29.8 242.1v1.3h1.3l-1.3 1.2-1.2-1.2h1.2M30.5 242.1h3.8M30.5 244.6h3.8M30.5 247.2h3.8M30.5 249.7h3.8M34.3 240.8h2.5v10.2h-2.5zM34.3 249.6h1.3v.3h-1.3zM34.3 247.1h1.3v.2h-1.3zM34.3 242h1.3v.2h-1.3zM34.3 244.5h1.3v.3h-1.3zM42.5 242.1h2.8"/>
<path d="M47.4 242.1h2.8M50.8 242.1v1.3h1.3l-1.3 1.2-1.3-1.2h1.3M51.4 242.1h3.8M51.4 244.6h3.8M51.4 247.2h3.8M51.4 249.7h3.8M54.6 259.9a3.2 3.2 0 0 1 5.1 0M55.2 240.8h2.6v10.2h-2.6zM55.2 249.6h1.3v.3h-1.3zM55.2 247.1h1.3v.2h-1.3zM55.2 242h1.3v.2h-1.3zM55.2 244.5h1.3v.3h-1.3z"/>
<path d="M102.2 252.3h5.7M107.9 252.9l2 1.9v3.8h1.2l-1.2 1.3-1.3-1.3h1.3M108.8 240.8h2.1v5.1h-2.1zM109.9 245.9v3.8l-2 1.9M140 246.5h2v5.1h-2zM141 245.3v1.2M141 251.6v1.3M146.3 249.1h2v5.1h-2zM147.3 247.8v1.3M147.3 254.2v1.2M154.3 250.4h2.8M155.6 242.7h2.8"/>
<path d="M155.6 240.2h2.8M159.1 250.4h2.8M160.4 242.7h7.9M160.4 240.2h7.9M162.6 250.4v1.2h1.2l-1.2 1.3-1.3-1.3h1.3M163.2 250.4h5.1M163.2 245.3h5.1M163.2 247.8h5.1M163.2 252.9h5.1M163.2 255.4h5.1M163.2 258h5.1M202.6 242.7h1.2"/>
<path d="M202.6 245.3h1.2M202.6 247.8h1.2M203.8 241.7h5.1v2.1h-5.1zM203.8 244.3h5.1v2h-5.1zM203.8 246.8h5.1v2h-5.1zM208.9 242.7h6.4M208.9 245.3h6.4M208.9 247.8h6.4M215.3 241.5h17.7v7.6h-17.7zM233 247.8h5.1v1.3h1.3l-1.3 1.3-1.2-1.3h1.2M233 242.7h5.1M233 245.3h5.1"/>
<path d="M259.8 245.9h1.8M261.6 243.4v5.1M262.9 248.5v3.8h1.3l-1.3 1.2-1.3-1.2h1.3M262.9 240.8v2.6M270 245.9h1.8M271.8 243.4v5.1M273 248.5v3.8h1.3l-1.3 1.2-1.2-1.2h1.2M273 240.8v2.6M281.4 245.9h1.8M283.2 243.4v5.1M284.5 248.5v3.8h1.2l-1.2 1.2-1.3-1.2h1.3M284.5 240.8v2.6"/>
<path d="M292.9 245.9h1.7M294.6 243.4v5.1M295.9 248.5v3.8h1.3l-1.3 1.2-1.3-1.2h1.3M295.9 240.8v2.6M324.5 245.9h5.1M324.5 242.1h5.1M324.5 249.7h5.1M324.5 253.5h5.1M329.6 257.3h-5.1v1.3h1.3l-1.3 1.3-1.3-1.3h1.3M344.8 257.3h5.1v1.3l-.3 .8M344.8 245.9h5.1M344.8 242.1h5.1"/>
<path d="M344.8 249.7h5.1M344.8 253.5h5.1M348.6 259.4l.3-.8h2l-.3 .8M349.4 258.6l-.3 .8M350.4 258.6l-.3 .8M371.1 259.9h2v5.1h-2zM372.1 253.5v2.6M372.1 258.6v1.3M372.1 253.5l-.8 1.3M372.1 253.5l.8 1.3M383.5 251.1l.3-.7h2l-.2 .7M384.3 250.4l-.3 .7"/>
<path d="M384.8 246.3v4.1l-.2 .7M385.3 250.4l-.2 .7M388.6 256.1h2.6M391.2 253.5h17.7v20.4h-17.7zM408.9 256.1h2.6M414.7 257.3v2.8M414.7 249.1h3.8M418.5 247.8v2.6M424.8 246.5v2.6h-3.8M424.8 246.5l-.7 1.3M424.8 246.5l.8 1.3M431.8 257.3h5.1"/>
<path d="M431.8 259.9h5.1M436.9 252.3h17.8v22.8h-17.8zM454.7 257.3h5M454.7 259.9h5M454.7 254.8h5M460.4 253.7h11.7v2.2h-11.7l-.7-1.1zM476.2 254.8v2.5M476.2 259.9v1.3M476.2 254.8l-.7 1.3M476.2 254.8l.8 1.3M487.7 252.4l.2-.8h2.1l-.3 .8M488.4 251.6l-.2 .8"/>
<path d="M488.9 247.6v4l-.2 .8M488.9 240.2v5.3M488.9 240.2l-.7 1.3M488.9 240.2l.8 1.3M489.5 251.6l-.3 .8M492.8 257.3h2.5M495.3 254.8h17.8v20.3h-17.8zM513.1 257.3h2.5M518.8 258.6v2.8M518.8 250.4h3.8M522.6 249.1v2.5M529 247.8v2.6h-3.9"/>
<path d="M529 247.8l-.8 1.3M529 247.8l.7 1.3M535.9 258.6h5.1M541 253.5h17.8v22.9h-17.8zM558.8 256.1h5.1M558.8 258.6h5.1M564.5 255h11.8v2.2h-11.8l-.6-1.1zM10 260.2h2M21.6 263.4v4.1h1.3l-1.3 1.3-1.3-1.3h1.3M26 273.2h2.6M26 275.8h2.6M28.6 270.7h20.3v15.2h-20.3z"/>
<path d="M38.7 265.6v5.1M48.9 275.8h2.5M49.5 261.2h4.2M60.6 261.2h5.4M66 260.1h5.1v2.1h-5.1zM71.1 261.2h1.3M142.2 278.7v4h1.3l-1.3 1.3-1.2-1.3h1.2M142.2 271.3l-.7 1.3M142.2 271.3v5.3M142.2 271.3l.8 1.3M238.8 273.9h2.5l-1.3 2.5zM238.8 276.4h2.5"/>
<path d="M239 265h2v5h-2zM240 270v10.2h1.3l-1.3 1.3-1.2-1.3h1.2M240 263.7v1.3M240.8 278.2l1.5 1.5v-.8v.8h-.7M240.8 276.9l1.5 1.5v-.7v.7h-.7M250.2 273.9h2.5l-1.2 2.5zM250.2 276.4h2.5M250.4 265h2.1v5h-2.1zM251.5 270v10.2h1.2l-1.2 1.3-1.3-1.3h1.3M251.5 263.7v1.3M252.2 278.2l1.5 1.5v-.8v.8h-.7M252.2 276.9l1.5 1.5v-.7v.7h-.7"/>
<path d="M261.6 273.9h2.6l-1.3 2.5zM261.6 276.4h2.6M261.9 265h2v5h-2zM262.9 270v10.2h1.3l-1.3 1.3-1.3-1.3h1.3M262.9 263.7v1.3M263.7 278.2l1.5 1.5v-.8v.8h-.8M263.7 276.9l1.5 1.5v-.7v.7h-.8M273 273.9h2.6l-1.3 2.5zM273 276.4h2.6M273.3 265h2v5h-2zM274.3 270v10.2h1.3l-1.3 1.3-1.3-1.3h1.3M274.3 263.7v1.3"/>
<path d="M275.1 278.2l1.5 1.5v-.8v.8h-.8M275.1 276.9l1.5 1.5v-.7v.7h-.8M284.5 273.9h2.5l-1.3 2.5zM284.5 276.4h2.5M284.7 265h2.1v5h-2.1zM285.7 270v10.2h1.3l-1.3 1.3-1.2-1.3h1.2M285.7 263.7v1.3M286.5 278.2l1.5 1.5v-.8v.8h-.7M286.5 276.9l1.5 1.5v-.7v.7h-.7M294.6 273.9h2.6l-1.3 2.5zM294.6 276.4h2.6M294.9 265h2v5h-2z"/>
<path d="M295.9 270v10.2h1.3l-1.3 1.3-1.3-1.3h1.3M295.9 263.7v1.3M296.7 278.2l1.5 1.5v-.8v.8h-.8M296.7 276.9l1.5 1.5v-.7v.7h-.8M321.3 277.4v4.1h1.3l-1.3 1.2-1.3-1.2h1.3M321.3 270l-.8 1.3M321.3 270v5.4M321.3 270l.8 1.3M354.3 277.4v4.1l-.2 .7M354.3 270v5.4M354.3 270l-.7 1.3M354.3 270l.8 1.3"/>
<path d="M372.1 265v1.2M387.3 275.9l.3-.8h2l-.2 .8M388.1 275.1l-.2 .8M388.6 273.9v1.2l-.2 .8M388.6 261.2h2.6M388.6 266.2h2.6M388.6 271.3h2.6M389.1 275.1l-.2 .8M408.9 261.2h2.6M408.9 266.2h2.6M408.9 271.3h2.6M414.7 262.2v2.8"/>
<path d="M417.2 261.2h1.3M417.2 271.3h1.3M418.5 260.1h5v2.1h-5zM418.5 270.3h5v2h-5zM423.5 261.2h1.3M423.5 271.3h1.3M430.5 264.5l.3-.8h2l-.2 .8M431.3 263.7l-.3 .8M431.8 267.5h5.1M431.8 270h5.1M431.8 265h5.1M432.3 263.7l-.2 .8"/>
<path d="M436.9 262.4h-5.1v1.3l-.3 .8M454.7 272.6h5M454.7 262.4h5M454.7 267.5h5M454.7 270h5M454.7 265h5M475.2 261.2h2.1v5h-2.1zM476.2 266.2v1.3M491.5 277.2l.2-.8h2.1l-.3 .8M492.3 276.4l-.3 .8M492.8 275.1v1.3l-.3 .8M492.8 272.6h2.5"/>
<path d="M492.8 262.4h2.5M492.8 267.5h2.5M493.3 276.4l-.3 .8M513.1 272.6h2.5M513.1 262.4h2.5M513.1 267.5h2.5M518.8 263.4v2.8M521.3 272.6h1.3M521.3 262.4h1.3M522.6 271.6h5.1v2h-5.1zM522.6 261.4h5.1v2h-5.1zM527.7 272.6h1.3"/>
<path d="M527.7 262.4h1.3M534.7 265.7l.2-.7h2.1l-.3 .7M535.4 265l-.2 .7M535.9 261.2h5.1M535.9 266.2h5.1M535.9 271.3h5.1M535.9 268.8h5.1M536.4 265l-.2 .7M541 263.7h-5.1v1.3l-.2 .7M558.8 261.2h5.1M558.8 266.2h5.1M558.8 271.3h5.1"/>
<path d="M558.8 263.7h5.1M558.8 268.8h5.1M558.8 273.9h5.1M582 260.2h2M26 280.8h2.6M26 283.4h2.6M38.7 285.9v3.8h1.3l-1.3 1.3-1.2-1.3h1.2M48.9 280.8h2.5M66.7 296.1v2.5h2.8M66.7 296.1l-.8 1.2M66.7 296.1l.7 1.2M71.5 298.6h2.8"/>
<path d="M74.9 298.6v1.3h1.3l-1.3 1.3-1.2-1.3h1.2M75.6 298.6h3.8M79.4 297.3h2.5v10.2h-2.5zM79.4 298.5h1.2v.2h-1.2zM94.6 287.8h10.2v15.3h-10.2zM95 289.6h3.3v.3l-.3 1h-2.8zM97.2 293.3h.6l.6 1.3h1.3M97.8 293.3h2.5M99.1 292h-.7l-1.2 1.3h-.7M104 297.9h.8v.2h-.8zM104 295.3h.8v.3h-.8zM104 290.2h.8v.3h-.8z"/>
<path d="M104.8 295.4h2.5M104.8 298h2.5M104.8 290.4h6.3M113.7 289.1v2.5M117.5 287.8l-.8 1.3M117.5 287.8v2.6h-3.8M117.5 287.8l.7 1.3M121.3 295.4h2.5M121.3 293.5h8.9M121.3 289.1l-.8 1.3M121.3 289.1v2.5M121.3 289.1l.7 1.3"/>
<path d="M123.8 294.2l2.6 1.2-2.6 1.3zM123.8 292.3l2.6 1.2-2.6 1.3zM126.4 295.4h3.8M126.4 292.3v4.4M128.4 293.9v-.7h-.8h.8l-1.5 1.5M128.4 292v-.7h-.8h.8l-1.5 1.5M129.7 293.9v-.7h-.8h.8l-1.6 1.5M129.7 292v-.7h-.8h.8l-1.6 1.5M130.2 296.3h5.1v2.1h-5.1zM130.2 294.4h5.1v2.1h-5.1zM130.2 292.5h5.1v2.1h-5.1zM135.3 295.4h6.3"/>
<path d="M135.3 293.5h6.3M136.5 299.3h5.1M136.5 291.6h5.1M136.5 297.3h5.1M141.6 290.4h12.7v13.9h-12.7zM154.3 299.3h5.1M154.3 295.4h5.1M154.3 291.6h5.1M154.3 293.5h5.1M154.3 297.3h5.1M163.8 291.6v1.3h1.3l-1.3 1.3-1.2-1.3h1.2M167.6 294.8l-.7 1.3"/>
<path d="M167.6 294.8v2.5M167.6 294.8l.8 1.3M189.9 298h2.5M196.6 295.7l-3.2 2M197.5 295.4h2.5M221.6 298h2.6M228.3 295.7l-3.1 2M229.2 295.4h2.6M253.4 298h2.5M260.1 295.7l-3.2 2M261 295.4h2.5M285.1 298h2.6"/>
<path d="M291.8 295.7l-3.1 2M292.7 295.4h2.6M324.5 281.5v2.5h5.1M324.5 299.3h5.1M324.5 295.4h5.1M324.5 291.6h5.1M324.5 287.8h5.1M324.5 281.5l-.8 1.2M324.5 281.5l.7 1.2M329.6 281.5h15.2v31.7h-15.2zM344.8 299.3h5.1M344.8 295.4h5.1"/>
<path d="M344.8 291.6h5.1M344.8 287.8h5.1M349.9 281.5v2.5h-5.1M349.9 281.5l-.8 1.2M349.9 281.5l.7 1.2M353.1 282.2l.2-.7h2l-.2 .7M353.8 281.5l-.2 .7M354.8 281.5l-.2 .7M372.7 297.3v2.6M372.7 297.3l-.7 1.3M372.7 297.3l.8 1.3M383.5 294.9l.3-.7h2l-.2 .7"/>
<path d="M384.3 294.2l-.3 .7M384.8 290.1v4.1l-.2 .7M384.8 282.7v5.4M384.8 282.7l-.8 1.3M384.8 282.7l.8 1.3M385.3 294.2l-.2 .7M388.6 299.9h2.6M391.2 297.3h17.7v20.4h-17.7zM408.9 299.9h2.6M414.7 292.9h3.8M418.5 291.6v2.6M424.8 290.4v2.5h-3.8"/>
<path d="M424.8 290.4l-.7 1.2M424.8 290.4l.8 1.2M436.9 296.1h17.8v22.8h-17.8zM454.7 298.6h5M460.4 297.5h11.7v2.2h-11.7l-.7-1.1zM476.9 298.6v2.6M476.9 298.6l-.8 1.3M476.9 298.6l.7 1.3M487.7 296.2l.2-.8h2.1l-.3 .8M488.4 295.4l-.2 .8M488.9 291.4v4l-.2 .8M488.9 284v5.3"/>
<path d="M488.9 284l-.7 1.3M488.9 284l.8 1.3M489.5 295.4l-.3 .8M495.3 298.6h17.8v20.3h-17.8zM518.8 294.2h3.8M522.6 292.9v2.5M529 291.6v2.6h-3.9M529 291.6l-.8 1.3M529 291.6l.7 1.3M541 297.3h17.8v22.9h-17.8zM558.8 299.9h5.1M564.5 298.8h11.8v2.2h-11.8l-.6-1.1z"/>
<path d="M10 310.2h2M19 319.6v1.2M27.9 319.6v1.2M36.8 319.6v1.2M45.7 319.6v1.2M54.6 319.6v1.2M63.5 319.6v1.2M72.4 319.6v1.2M75.6 301.2h3.8M75.6 306.2h3.8M75.6 303.7h3.8M79.4 306.1h1.2v.3h-1.2z"/>
<path d="M79.4 303.6h1.2v.2h-1.2zM79.4 301h1.2v.3h-1.2zM81.3 319.6v1.2M97.2 303.1v2.5M99.6 302.3h.2v.8h-.2zM99.7 303.1v3.8h1.3l-1.3 1.2-1.3-1.2h1.3M104 300.4h.8v.3h-.8zM104.8 300.5h2.5M121.3 303.1h8.9M123.8 301.8l2.6 1.3-2.6 1.2zM126.4 301.8v2.5M128.4 301.5v-.7h-.8h.8l-1.5 1.5"/>
<path d="M129.7 301.5v-.7h-.8h.8l-1.6 1.5M130.2 302h5.1v2.1h-5.1zM135.3 303.1h6.3M136.5 301.2h5.1M154.3 303.1h5.1M154.3 301.2h5.1M196.8 319.6h7.7l3.8-3.8h1.2v1.2h2.6l1.3-1.2h12.7v24.1h-29.3zM197.5 300.5h2.5v1.3h1.3l-1.3 1.3-1.2-1.3h1.2M222.2 315.8v-1.3h-35.5v33h35.5v-7.6M229.2 300.5h2.6v1.3h1.2l-1.2 1.3-1.3-1.3h1.3M239.4 312l-.8 1.2M239.4 312v5.3"/>
<path d="M239.4 319.3v2.8M239.4 312l.8 1.2M248.3 314.5v2.8M248.3 319.3v2.8M257.2 319.3v4.1h1.2l-1.2 1.3-1.3-1.3h1.3M257.2 314.5v2.8M261 300.5h2.5v1.3h1.3l-1.3 1.3-1.2-1.3h1.2M269.2 317.7l-.7 1.2M269.2 317.7v10.1M269.2 317.7l.8 1.2M292.7 300.5h2.6v1.3h1.2l-1.2 1.3-1.3-1.3h1.3M324.5 306.9h5.1"/>
<path d="M324.5 303.1h5.1M329.6 310.7h-5.1v1.3h1.3l-1.3 1.2-1.3-1.2h1.3M344.8 310.7h5.1v1.3l-.3 .7M344.8 306.9h5.1M344.8 303.1h5.1M348.6 312.7l.3-.7h2l-.3 .7M349.4 312l-.3 .7M350.4 312l-.3 .7M371.7 303.7h2.1v5.1h-2.1zM372.7 302.4v1.3M372.7 308.8v1.2M387.3 319.7l.3-.8h2l-.2 .8"/>
<path d="M388.1 318.9l-.2 .8M388.6 317.7v1.2l-.2 .8M388.6 305h2.6M388.6 310h2.6M388.6 315.1h2.6M389.1 318.9l-.2 .8M408.9 305h2.6M408.9 310h2.6M408.9 315.1h2.6M414.7 301.2v2.8M414.7 306v2.8M417.2 305h1.3"/>
<path d="M417.2 315.1h1.3M418.5 304h5v2h-5zM418.5 314.1h5v2h-5zM423.5 305h1.3M423.5 315.1h1.3M430.5 308.3l.3-.8h2l-.2 .8M431.3 307.5l-.3 .8M431.8 301.2h5.1M431.8 311.3h5.1M431.8 313.9h5.1M431.8 303.7h5.1M431.8 308.8h5.1"/>
<path d="M432.3 307.5l-.2 .8M436.9 306.2h-5.1v1.3l-.3 .8M454.7 301.2h5M454.7 306.2h5M454.7 311.3h5M454.7 316.4h5M454.7 313.9h5M454.7 303.7h5M454.7 308.8h5M475.9 305h2v5h-2zM476.9 303.7v1.3M476.9 310v1.3"/>
<path d="M492.8 318.9v1.3l-.3 .8M492.8 301.2h2.5M492.8 306.2h2.5M492.8 311.3h2.5M492.8 316.4h2.5M513.1 301.2h2.5M513.1 306.2h2.5M513.1 311.3h2.5M513.1 316.4h2.5M518.8 302.4v2.8M518.8 307.3v2.7M521.3 306.2h1.3"/>
<path d="M521.3 316.4h1.3M522.6 305.2h5.1v2.1h-5.1zM522.6 315.4h5.1v2h-5.1zM527.7 306.2h1.3M527.7 316.4h1.3M534.7 309.5l.2-.7h2.1l-.3 .7M535.4 308.8l-.2 .7M535.9 305h5.1M535.9 310h5.1M535.9 315.1h5.1M535.9 302.4h5.1M535.9 312.6h5.1"/>
<path d="M536.4 308.8l-.2 .7M541 307.5h-5.1v1.3l-.2 .7M558.8 305h5.1M558.8 310h5.1M558.8 315.1h5.1M558.8 302.4h5.1M558.8 307.5h5.1M558.8 312.6h5.1M558.8 317.7h5.1M582 310.2h2M17.8 329.7h2.5l-1.3 2.6zM17.8 332.3h2.5"/>
<path d="M18 320.8h2.1v5.1h-2.1zM19 325.9v10.2h1.3l-1.3 1.3-1.2-1.3h1.2M19.8 334.1l1.5 1.5v-.8v.8h-.7M19.8 332.8l1.5 1.5v-.8v.8h-.7M26.7 329.7h2.5l-1.3 2.6zM26.7 332.3h2.5M26.9 320.8h2.1v5.1h-2.1zM27.9 325.9v10.2h1.3l-1.3 1.3-1.2-1.3h1.2M28.7 334.1l1.5 1.5v-.8v.8h-.7M28.7 332.8l1.5 1.5v-.8v.8h-.7M35.6 329.7h2.5l-1.3 2.6zM35.6 332.3h2.5"/>
<path d="M35.8 320.8h2v5.1h-2zM36.8 325.9v10.2h1.3l-1.3 1.3-1.2-1.3h1.2M37.6 334.1l1.5 1.5v-.8v.8h-.7M37.6 332.8l1.5 1.5v-.8v.8h-.7M44.4 329.7h2.6l-1.3 2.6zM44.4 332.3h2.6M44.7 320.8h2v5.1h-2zM45.7 325.9v10.2h1.3l-1.3 1.3-1.3-1.3h1.3M46.5 334.1l1.5 1.5v-.8v.8h-.8M46.5 332.8l1.5 1.5v-.8v.8h-.8M53.3 329.7h2.6l-1.3 2.6zM53.3 332.3h2.6"/>
<path d="M53.6 320.8h2v5.1h-2zM54.6 325.9v10.2h1.3l-1.3 1.3-1.3-1.3h1.3M55.4 334.1l1.5 1.5v-.8v.8h-.8M55.4 332.8l1.5 1.5v-.8v.8h-.8M62.2 329.7h2.6l-1.3 2.6zM62.2 332.3h2.6M62.5 320.8h2v5.1h-2zM63.5 325.9v10.2h1.3l-1.3 1.3-1.3-1.3h1.3M64.3 334.1l1.5 1.5v-.8v.8h-.8M64.3 332.8l1.5 1.5v-.8v.8h-.8M71.1 329.7h2.6l-1.3 2.6zM71.1 332.3h2.6"/>
<path d="M71.4 320.8h2v5.1h-2zM72.4 325.9v10.2h1.3l-1.3 1.3-1.3-1.3h1.3M73.2 334.1l1.5 1.5v-.8v.8h-.8M73.2 332.8l1.5 1.5v-.8v.8h-.8M80 329.7h2.5l-1.2 2.6zM80 332.3h2.5M80.3 320.8h2v5.1h-2zM81.3 325.9v10.2h1.2l-1.2 1.3-1.3-1.3h1.3M82 334.1l1.6 1.5v-.8v.8h-.8M82 332.8l1.6 1.5v-.8v.8h-.8M113.7 325.9h5M113.7 333.5h5"/>
<path d="M118.7 323.4h12.7v12.7h-12.7zM118.7 329.7h-5v1.3h1.2l-1.2 1.3-1.3-1.3h1.3M127.6 325.9l-2.5 3.8M131.4 329.7h5.1v1.3h1.3l-1.3 1.3-1.2-1.3h1.2M131.4 325.9h5.1M131.4 333.5h5.1M175.3 325.9h1.2M175.3 336.1h1.2M175.3 323.4h1.2M175.5 337.4h2v5h-2zM176.5 335.1h5.1v2h-5.1zM176.5 322.4h5.1v2h-5.1z"/>
<path d="M176.5 324.9h5.1v2h-5.1zM176.5 330h5.1v2h-5.1zM176.5 333.5v3.9M176.5 333.5l-.7 1.3M176.5 333.5l.8 1.3M181.6 325.9h5.1M181.6 336.1h5.1M181.6 331h5.1M182.9 325.9l-.8 1.3M182.9 325.9v2.6h3.8M182.9 325.9l.7 1.3M182.9 323.4h3.8"/>
<path d="M182.9 320.8h3.8M182.9 338.6h3.8M186.7 333.5h-3.8v1.3h1.2l-1.2 1.3-1.3-1.3h1.3M237.5 327.8v2.6h1.3M237.5 327.8l-.8 1.3M237.5 327.8l.8 1.3M238.8 329.4h5v2h-5zM243.8 330.4h1.3M246.4 338v2.5h7.6M246.4 338l-.8 1.3M246.4 338l.7 1.3M246.4 330.4h6.3"/>
<path d="M246.4 335.4h7.6M253.4 334.8l1.2 1.3M253.4 339.9l1.2 1.3M254 327.8h80v66.1h-80zM254.6 334.8l-1.2 1.3M254.6 339.9l-1.2 1.3M268.6 327.2l1.3 1.3M269.9 327.2l-1.3 1.3M271.1 327.2l1.3 1.3M271.8 320.2v7.6M272.4 327.2l-1.3 1.3M273.7 327.2l1.3 1.3"/>
<path d="M274.3 320.2v7.6M275 327.2l-1.3 1.3M334 330.4h7.6M334 335.4h7.6M334 332.9h7.6M334 338h7.6M372.1 336.7v2.6M372.1 336.7l-.8 1.3M372.1 336.7l.8 1.3M383.5 334.3l.3-.8h2l-.2 .8M384.3 333.5l-.3 .8M384.8 329.5v4l-.2 .8"/>
<path d="M384.8 322.1v5.3M384.8 322.1l-.8 1.3M384.8 322.1l.8 1.3M385.3 333.5l-.2 .8M388.6 339.3h2.6M391.2 336.7h17.7v20.3h-17.7zM408.9 339.3h2.6M414.7 332.3h3.8M418.5 331v2.5M424.8 329.7v2.6h-3.8M424.8 329.7l-.7 1.3M424.8 329.7l.8 1.3"/>
<path d="M436.9 335.4h17.8v22.9h-17.8zM454.7 338h5M460.4 336.9h11.7v2.2h-11.7l-.7-1.1zM476.2 338v2.5M476.2 338l-.7 1.3M476.2 338l.8 1.3M487.7 335.6l.2-.8h2.1l-.3 .8M488.4 334.8l-.2 .8M488.9 330.8v4l-.2 .8M488.9 323.4v5.3M488.9 323.4l-.7 1.3M488.9 323.4l.8 1.3"/>
<path d="M489.5 334.8l-.3 .8M491.5 321l.2-.8h2.1l-.3 .8M492.3 320.2l-.3 .8M493.3 320.2l-.3 .8M495.3 338h17.8v20.3h-17.8zM518.8 333.5h3.8M522.6 332.3v2.5M529 331v2.5h-3.9M529 331l-.8 1.3M529 331l.7 1.3M541 336.7h17.8v22.9h-17.8zM558.8 339.3h5.1"/>
<path d="M564.5 338.1h11.8v2.3h-11.8l-.6-1.1zM44.4 352l-.7 1.2M44.4 352v2.5M44.4 352l.8 1.2M47 354.5h2.8M51.8 354.5h2.8M99.1 354.5v2.5h2.4M99.1 354.5l-.8 1.3M99.1 354.5l.7 1.3M102.6 355.8a1.62 1.62 0 0 1 2.6 0M105.7 355.8a1.62 1.62 0 0 1 2.5 0M109.3 357h2.5"/>
<path d="M131.4 358.3v2.5M131.4 358.3l-.7 1.3M131.4 358.3l.8 1.3M176.5 342.4v1.3M180.3 358.3v2.5M180.3 358.3l-.7 1.3M180.3 358.3l.8 1.3M181 346.9v1.2h1.2l-1.2 1.3-1.3-1.3h1.3M182.9 341.2h3.8M182.9 343.7h3.8M222.2 343.7h3.9M246.4 345.6h7.6"/>
<path d="M246.4 355.8h7.6M246.4 348.1h7.6M246.4 353.2h7.6M334 340.5h7.6M334 350.7h7.6M334 355.8h7.6M334 358.3h7.6M334 343.1h7.6M334 348.1h7.6M334 353.2h7.6M340.9 359.3v-.7h.7h-.7l1.5 1.5M344.2 359.6v5.1"/>
<path d="M350.5 359.8h5.1v2.1h-5.1zM356.9 358.3v2.5h-1.3M356.9 358.3l-.8 1.3M356.9 358.3l.7 1.3M371.1 343.1h2v5h-2zM372.1 341.8v1.3M372.1 348.1v1.3M387.3 359.1l.3-.8h2l-.2 .8M388.1 358.3l-.2 .8M388.6 357v1.3l-.2 .8M388.6 354.5h2.6M388.6 344.3h2.6"/>
<path d="M388.6 349.4h2.6M389.1 358.3l-.2 .8M408.9 354.5h2.6M408.9 344.3h2.6M408.9 349.4h2.6M414.7 340.5v2.8M414.7 345.4v2.7M417.2 354.5h1.3M417.2 344.3h1.3M418.5 353.5h5v2h-5zM418.5 343.3h5v2.1h-5zM423.5 354.5h1.3"/>
<path d="M423.5 344.3h1.3M430.5 347.6l.3-.7h2l-.2 .7M431.3 346.9l-.3 .7M431.8 340.5h5.1M431.8 350.7h5.1M431.8 343.1h5.1M431.8 348.1h5.1M431.8 353.2h5.1M432.3 346.9l-.2 .7M436.9 345.6h-5.1v1.3l-.3 .7M454.7 340.5h5M454.7 345.6h5"/>
<path d="M454.7 350.7h5M454.7 355.8h5M454.7 343.1h5M454.7 348.1h5M454.7 353.2h5M475.2 344.3h2.1v5.1h-2.1zM476.2 343.1v1.2M476.2 349.4v1.3M492.3 359.6l-.3 .7M492.8 358.3v1.3l-.3 .7M492.8 340.5h2.5M492.8 345.6h2.5"/>
<path d="M492.8 350.7h2.5M492.8 355.8h2.5M493.3 359.6l-.3 .7M513.1 340.5h2.5M513.1 345.6h2.5M513.1 350.7h2.5M513.1 355.8h2.5M518.8 341.8v2.8M518.8 346.6v2.8M521.3 345.6h1.3M521.3 355.8h1.3M522.6 344.6h5.1v2h-5.1z"/>
<path d="M522.6 354.8h5.1v2h-5.1zM527.7 345.6h1.3M527.7 355.8h1.3M534.7 348.9l.2-.8h2.1l-.3 .8M535.4 348.1l-.2 .8M535.9 354.5h5.1M535.9 344.3h5.1M535.9 349.4h5.1M535.9 341.8h5.1M535.9 352h5.1M536.4 348.1l-.2 .8M541 346.9h-5.1v1.2l-.2 .8"/>
<path d="M558.8 354.5h5.1M558.8 344.3h5.1M558.8 349.4h5.1M558.8 357h5.1M558.8 341.8h5.1M558.8 346.9h5.1M558.8 352h5.1M10 360.2h2M32.4 363.4h3.8M32.4 365.9h3.8M32.4 368.5h3.8M32.4 371h3.8"/>
<path d="M32.4 373.5h3.8M32.4 376.1h3.8M32.4 378.6h3.8M36.2 362.1h2.5v25.4h-2.5zM36.2 378.5h1.3v.3h-1.3zM36.2 376h1.3v.2h-1.3zM36.2 370.9h1.3v.2h-1.3zM36.2 368.3h1.3v.3h-1.3zM36.2 365.8h1.3v.3h-1.3zM36.2 363.3h1.3v.2h-1.3zM36.2 373.4h1.3v.3h-1.3zM44.4 363.4h3.9"/>
<path d="M44.4 365.9h3.9M44.4 368.5h3.9M44.4 371h3.9M44.4 373.5h3.9M44.4 376.1h3.9M44.4 378.6h3.9M48.3 362.1h5v25.4h-5zM48.3 378.5h1.2v.3h-1.2zM48.3 376h1.2v.2h-1.2zM48.3 370.9h1.2v.2h-1.2zM48.3 368.3h1.2v.3h-1.2zM48.3 365.8h1.2v.3h-1.2z"/>
<path d="M48.3 363.3h1.2v.2h-1.2zM48.3 373.4h1.2v.3h-1.2zM52.1 378.5h1.2v.3h-1.2zM52.1 376h1.2v.2h-1.2zM52.1 370.9h1.2v.2h-1.2zM52.1 368.3h1.2v.3h-1.2zM52.1 365.8h1.2v.3h-1.2zM52.1 363.3h1.2v.2h-1.2zM52.1 373.4h1.2v.3h-1.2zM53.3 363.4h3.8M53.3 365.9h3.8M53.3 368.5h3.8"/>
<path d="M53.3 371h3.8M53.3 373.5h3.8M53.3 376.1h3.8M53.3 378.6h3.8M74.9 371h2.6M74.9 373.5h2.6M74.9 376.1h2.6M74.9 378.6h2.6M77.5 368.5h12.7v25.4h-12.7zM92.7 371h3.8M92.7 373.5h3.8M92.7 376.1h3.8"/>
<path d="M92.7 378.6h3.8M93.6 361h9.9l.6 1.1-.6 1.1h-9.9zM96.5 369.7h2.6v20.4h-2.6zM96.5 376h1.3v.2h-1.3zM96.5 373.4h1.3v.3h-1.3zM96.5 370.9h1.3v.2h-1.3zM96.5 378.5h1.3v.3h-1.3zM105.4 371h3.8M105.4 373.5h3.8M105.4 376.1h3.8M105.4 378.6h3.8M107.9 362.1h2.8"/>
<path d="M109.2 369.7h5.1v20.4h-5.1zM109.2 376h1.3v.2h-1.3zM109.2 373.4h1.3v.3h-1.3zM109.2 370.9h1.3v.2h-1.3zM109.2 378.5h1.3v.3h-1.3zM112.8 362.1h2.8M113 376h1.3v.2h-1.3zM113 373.4h1.3v.3h-1.3zM113 370.9h1.3v.2h-1.3zM113 378.5h1.3v.3h-1.3zM114.3 371h3.8M114.3 373.5h3.8"/>
<path d="M114.3 376.1h3.8M114.3 378.6h3.8M130.4 364.7h2.1v5h-2.1zM131.4 363.4v1.3M131.4 369.7v1.3M136.1 362.1h2.1v5.1h-2.1zM137.2 360.8v1.3M137.2 367.2v1.3M137.4 372.3h2v5.1h-2zM138.4 371v1.3M138.4 377.4v1.2M143.8 369.7h2v5.1h-2z"/>
<path d="M144.8 368.5v1.2M144.8 374.8v1.3M151.8 360.8v2.6h2.8M151.8 360.8l-.8 1.3M151.8 360.8l.7 1.3M156.6 363.4h2.8M160 363.4v1.3h1.3l-1.3 1.2-1.3-1.2h1.3M160.7 363.4h3.8M160.7 365.9h3.8M160.7 368.5h3.8M160.7 371h3.8M164.5 362.1h2.5v10.2h-2.5z"/>
<path d="M164.5 370.9h1.2v.2h-1.2zM164.5 368.3h1.2v.3h-1.2zM164.5 363.3h1.2v.2h-1.2zM164.5 365.8h1.2v.3h-1.2zM179.3 364.7h2.1v5h-2.1zM180.3 363.4v1.3M180.3 369.7v1.3M185 362.1h2.1v5.1h-2.1zM186.1 360.8v1.3M186.1 367.2v1.3M186.3 372.3h2v5.1h-2zM187.3 371v1.3"/>
<path d="M187.3 377.4v1.2M192.7 369.7h2v5.1h-2zM193.7 368.5v1.2M193.7 374.8v1.3M200.7 360.8v2.6h2.8M200.7 360.8l-.8 1.3M200.7 360.8l.7 1.3M205.5 363.4h2.8M208.9 363.4v1.3h1.3l-1.3 1.2-1.3-1.2h1.3M209.5 363.4h3.9M209.5 365.9h3.9M209.5 368.5h3.9"/>
<path d="M209.5 371h3.9M213.4 362.1h2.5v10.2h-2.5zM213.4 370.9h1.2v.2h-1.2zM213.4 368.3h1.2v.3h-1.2zM213.4 363.3h1.2v.2h-1.2zM213.4 365.8h1.2v.3h-1.2zM246.4 363.4h7.6M246.4 368.5h7.6M246.4 371h7.6M246.4 360.8h7.6M246.4 376.1h7.6M246.4 378.6h7.6"/>
<path d="M334 363.4h16.5M334 368.5h7.6M334 371h7.6M334 360.8h16.5M334 373.5h7.6M334 376.1h7.6M334 378.6h7.6M340.9 361.9v-.8h.7h-.7l1.5 1.5M342.1 361.9v-.8h.8h-.8l1.6 1.5M344.2 363.4l2.5-1.3v2.6zM344.2 360.8l2.5-1.2v2.5zM350.5 362.4h5.1v2h-5.1z"/>
<path d="M355.6 363.4h1.3M384.8 374.2h15.2v2.5h-15.2zM386 375.5h.2v1.2h-.2zM386.1 376.7v3.8M388.5 375.5h.2v1.2h-.2zM388.6 376.7v7.6M391 375.5h.3v1.2h-.3zM391.2 376.7v5.1h1.2l-1.2 1.3-1.3-1.3h1.3M393.6 375.5h.2v1.2h-.2zM393.7 376.7v3.8M396.1 375.5h.3v1.2h-.3zM396.2 376.7v3.8"/>
<path d="M398.7 375.5h.2v1.2h-.2zM398.8 376.7v3.8M474 376.2h108v32h-108zM491.5 360.3l.2-.7h2.1l-.3 .7M582 360.2h2M32.4 383.7h3.8M32.4 386.2h3.8M32.4 381.2h3.8M36.2 381h1.3v.3h-1.3zM36.2 383.6h1.3v.2h-1.3zM36.2 386.1h1.3v.3h-1.3zM44.4 383.7h3.9"/>
<path d="M44.4 386.2h3.9M44.4 381.2h3.9M48.3 381h1.2v.3h-1.2zM48.3 383.6h1.2v.2h-1.2zM48.3 386.1h1.2v.3h-1.2zM52.1 381h1.2v.3h-1.2zM52.1 383.6h1.2v.2h-1.2zM52.1 386.1h1.2v.3h-1.2zM53.3 386.2h3.8v1.3h1.3l-1.3 1.3-1.2-1.3h1.2M53.3 383.7h3.8M53.3 381.2h3.8M74.9 388.8h2.6"/>
<path d="M74.9 383.7h2.6M74.9 386.2h2.6M74.9 381.2h2.6M77.5 391.3h-2.6v1.3h1.3l-1.3 1.3-1.2-1.3h1.2M92.7 388.8h3.8M92.7 383.7h3.8M92.7 386.2h3.8M92.7 381.2h3.8M93.3 390.2h10v2.2h-10l-.6-1.1zM96.5 383.6h1.3v.2h-1.3zM96.5 386.1h1.3v.3h-1.3zM96.5 388.7h1.3v.2h-1.3z"/>
<path d="M96.5 381h1.3v.3h-1.3zM105.4 388.8h3.8M105.4 383.7h3.8M105.4 386.2h3.8M105.4 381.2h3.8M109.2 383.6h1.3v.2h-1.3zM109.2 386.1h1.3v.3h-1.3zM109.2 388.7h1.3v.2h-1.3zM109.2 381h1.3v.3h-1.3zM113 383.6h1.3v.2h-1.3zM113 386.1h1.3v.3h-1.3zM113 388.7h1.3v.2h-1.3z"/>
<path d="M113 381h1.3v.3h-1.3zM114.3 388.8h3.8v1.3h1.3l-1.3 1.2-1.3-1.2h1.3M114.3 383.7h3.8M114.3 386.2h3.8M114.3 381.2h3.8M130.4 390.1h2.1v5h-2.1zM131.4 383.7v2.5M131.4 388.8v1.3M131.4 395.1v1.3M131.4 383.7l-.7 1.3M131.4 383.7l.8 1.3M136.1 387.5h2.1v5.1h-2.1z"/>
<path d="M137.2 386.2v1.3M137.2 392.6v1.3M137.4 397.7h2v5.1h-2zM138.4 396.4v1.3M143.8 395.1h2v5.1h-2zM144.8 393.9v1.2M151.8 386.2v2.6h2.8M151.8 386.2l-.8 1.3M151.8 386.2l.7 1.3M156.6 388.8h2.8M160 388.8v1.3h1.3l-1.3 1.2-1.3-1.2h1.3M160.7 388.8h3.8"/>
<path d="M160.7 391.3h3.8M160.7 393.9h3.8M160.7 396.4h3.8M164.5 387.5h2.5v10.2h-2.5zM164.5 396.3h1.2v.2h-1.2zM164.5 393.7h1.2v.3h-1.2zM164.5 388.7h1.2v.2h-1.2zM164.5 391.2h1.2v.3h-1.2zM179.3 390.1h2.1v5h-2.1zM180.3 383.7v2.5M180.3 388.8v1.3M180.3 395.1v1.3"/>
<path d="M180.3 383.7l-.7 1.3M180.3 383.7l.8 1.3M185 387.5h2.1v5.1h-2.1zM186.1 386.2v1.3M186.1 392.6v1.3M186.3 397.7h2v5.1h-2zM187.3 396.4v1.3M192.7 395.1h2v5.1h-2zM193.7 393.9v1.2M200.7 386.2v2.6h2.8M200.7 386.2l-.8 1.3M200.7 386.2l.7 1.3"/>
<path d="M205.5 388.8h2.8M208.9 388.8v1.3h1.3l-1.3 1.2-1.3-1.2h1.3M209.5 388.8h3.9M209.5 391.3h3.9M209.5 393.9h3.9M209.5 396.4h3.9M213.4 387.5h2.5v10.2h-2.5zM213.4 396.3h1.2v.2h-1.2zM213.4 393.7h1.2v.3h-1.2zM213.4 388.7h1.2v.2h-1.2zM213.4 391.2h1.2v.3h-1.2zM238.8 388.8h2.8"/>
<path d="M243.6 388.8h10.4M253.4 388.2l1.2 1.2M254 391.3h-7.6v1.3h1.2l-1.2 1.3-1.3-1.3h1.3M254.6 388.2l-1.2 1.2M268.6 393.2l1.3 1.3M269.2 393.9v7.6M269.9 393.2l-1.3 1.3M271.1 393.2l1.3 1.3M271.8 393.9v7.6M272.4 393.2l-1.3 1.3M273.7 393.2l1.3 1.3M274.3 393.9v8.9h1.3l-1.3 1.2-1.3-1.2h1.3"/>
<path d="M275 393.2l-1.3 1.3M334 388.8h7.6M334 391.3h7.6M334 383.7h7.6M334 386.2h7.6M334 381.2h7.6M360.7 382.4h10.1v15.3h-10.1zM361.2 384.2h3.3v1.3h-3.3zM363.2 387.9h.7l.6 1.3h1.3M363.2 397.7v2.5M363.9 387.9h2.5M365.1 386.6h-.6l-1.3 1.3h-.6"/>
<path d="M365.6 396.9h.3v.8h-.3zM365.8 397.7v3.8h1.2l-1.2 1.3-1.3-1.3h1.3M370.1 392.5h.7v.2h-.7zM370.1 389.9h.7v.3h-.7zM370.1 384.9h.7v.2h-.7zM370.8 385h2.6M370.8 392.6h2.6M370.8 390.1h2.6M376.6 382.4l-.8 1.3M376.6 382.4v2.6M376.6 382.4l.7 1.3M387.3 386.9h2.6"/>
<path d="M388.6 386.9v3.8h4.2M393.7 389.4a3.2 3.2 0 0 1 5.1 0M403.9 388.2v2.5h-4.2M403.9 388.2l-.8 1.2M403.9 388.2l.7 1.2M474 397.7h108M474 391.7h108M484.6 392.2l-1.3 2M489.1 395.6l-.5-.1-.3 .3 .1 .6h.7M489.7 395.6h.6v.9M489.7 395v1.5M60 408.2v2"/>
<path d="M110 408.2v2M138.4 402.8v1.2M144.8 400.2v1.3M160 408.2v2M187.3 402.8v1.2M193.7 400.2v1.3M210 408.2v2M260 408.2v2M310 408.2v2M360 408.2v2M410 408.2v2M460 408.2v2"/>
<path d="M474 404.7h108M474 401.7h108M483.1 402.6l.6-.2 .3 .5-.9 1h.9M494 401.7v3M501.7 406.7h.8M503.2 406.6v.1M504.2 405.1l-.4 1.1h.9M504.5 405.7v1M505.2 405a1.71 1.71 0 0 1 0 2.3M506.3 406.2h1.2M508.1 405.7l.4-.5v1.5M508.1 406.7h.9"/>
<path d="M510 408.2v2M536.5 409.7h.8M558 401.7v6.5M560 408.2v2M566.8 405.1l-1.2 2M567.3 405.7l.4-.5v1.5M567.3 406.7h.8"/>
<circle cx="222.1" cy="28.7" r=".51"/>
<circle cx="222.1" cy="33.8" r=".51"/>
<circle cx="226.2" cy="31.3" r=".51"/>
<circle cx="236" cy="31.3" r="2.82"/>
<circle cx="272.8" cy="26.2" r="2.82"/>
<circle cx="450.7" cy="28.7" r=".51"/>
<circle cx="454.8" cy="31.3" r=".51"/>
<circle cx="454.8" cy="26.2" r=".51"/>
<circle cx="467.1" cy="26.2" r="2.82"/>
<circle cx="71.8" cy="51.6" r=".89"/>
<circle cx="76.8" cy="51.6" r=".89"/>
<circle cx="450.7" cy="75.7" r=".51"/>
<circle cx="454.8" cy="78.3" r=".51"/>
<circle cx="465.8" cy="78.3" r="2.82"/>
<circle cx="478.2" cy="77.6" r=".89"/>
<circle cx="478.2" cy="72.6" r=".89"/>
<circle cx="24.6" cy="99.9" r=".51"/>
<circle cx="28.7" cy="99.9" r=".51"/>
<circle cx="450.7" cy="80.8" r=".51"/>
<circle cx="108.6" cy="252.3" r="2.82"/>
<circle cx="262.9" cy="247.9" r=".51"/>
<circle cx="262.9" cy="243.9" r=".51"/>
<circle cx="273" cy="247.9" r=".51"/>
<circle cx="273" cy="243.9" r=".51"/>
<circle cx="284.5" cy="243.9" r=".51"/>
<circle cx="284.5" cy="247.9" r=".51"/>
<circle cx="295.9" cy="247.9" r=".51"/>
<circle cx="295.9" cy="243.9" r=".51"/>
<circle cx="54.6" cy="261.2" r=".89"/>
<circle cx="59.7" cy="261.2" r=".89"/>
<circle cx="192.9" cy="298" r=".51"/>
<circle cx="197" cy="295.4" r=".51"/>
<circle cx="224.7" cy="298" r=".51"/>
<circle cx="228.7" cy="295.4" r=".51"/>
<circle cx="256.4" cy="298" r=".51"/>
<circle cx="260.5" cy="295.4" r=".51"/>
<circle cx="288.2" cy="298" r=".51"/>
<circle cx="292.2" cy="295.4" r=".51"/>
<circle cx="197" cy="300.5" r=".51"/>
<circle cx="228.7" cy="300.5" r=".51"/>
<circle cx="260.5" cy="300.5" r=".51"/>
<circle cx="292.2" cy="300.5" r=".51"/>
<circle cx="125.1" cy="329.7" r="2.84"/>
<circle cx="253.4" cy="330.4" r=".63"/>
<circle cx="102.4" cy="357" r=".89"/>
<circle cx="105.4" cy="357" r=".91"/>
<circle cx="108.5" cy="357" r=".89"/>
<circle cx="393.7" cy="390.7" r=".89"/>
<circle cx="398.8" cy="390.7" r=".89"/>
</g>
<g fill="none" stroke="#840000" stroke-width=".51">
<path d="M109.1 19.1v4.1M110.6 19.1v4.1M73.5 25.7h4.1M73.5 24.2h4.1M120.5 39.4h4.1M147.8 38.4h4.1M147.8 36.9h4.1M165.6 31.4h4.1M165.6 29.9h4.1M188.5 31.4h4M188.5 29.9h4M359.9 34.5a3.3 3.3 0 0 1 4.1 0"/>
<path d="M359.9 32.4h4.1M389.1 34.5a3.3 3.3 0 0 1 4.1 0M389.1 32.4h4.1M120.5 40.9h4.1M218.9 56.8h4.1M218.9 55.3h4.1M227.8 56.8h4.1M227.8 55.3h4.1M236.7 56.8h4.1M236.7 55.3h4.1M245.6 56.8h4.1M245.6 55.3h4.1"/>
<path d="M254.5 56.8h4.1M254.5 55.3h4.1M263.4 56.8h4.1M263.4 55.3h4.1M272.3 56.8h4.1M272.3 55.3h4.1M281.2 56.8h4M281.2 55.3h4M290.1 56.8h4M290.1 55.3h4M24.8 76.4v2.5M28.6 76.4v2.5"/>
<path d="M20.2 82.2h4.1M20.2 80.7h4.1M29.1 82.2h4M29.1 80.7h4M361.2 85.8v4M362.7 85.8v4M25.9 105.5v4M27.4 105.5v4M349.8 108.2h4M349.8 106.7h4M372.6 104.2h4.1M372.6 105.7h4.1"/>
<path d="M382.1 106.2a3.3 3.3 0 0 1 4.1 0M382.1 104.2h4.1M405 104.4h4.1M405 102.9h4.1M415.8 103.2h4.1M415.8 101.6h4.1M436.1 103.2h4.1M436.1 101.6h4.1M502.2 106.8a3.3 3.3 0 0 1 4 0M502.2 104.8h4M512.3 106.8a3.3 3.3 0 0 1 4.1 0M512.3 104.8h4.1"/>
<path d="M522.5 106.3h4M522.5 104.8h4M532 106.3h4.1M532 104.8h4.1M382.8 123.5h4M382.8 122h4M412.6 139.4h4.1M412.6 137.8h4.1M486.9 124.8h4.1M486.9 123.2h4.1M516.8 139.1h4M516.8 140.6h4"/>
<path d="M382.8 162.9h4M382.8 161.3h4M412.6 178.7h4.1M412.6 177.2h4.1M486.9 164.1h4.1M486.9 162.6h4.1M516.8 178.5h4M516.8 180h4M382.8 206.7h4M382.8 205.1h4M486.9 207.9h4.1M486.9 206.4h4.1"/>
<path d="M158.6 238.2v6.6M160.1 238.2v6.6M201.2 223.8h4M201.2 222.3h4M213.9 223.8h4M213.9 222.3h4M319.3 223.8h4M319.3 222.3h4M352.3 223.8h4.1M352.3 222.3h4.1M412.6 222.5h4.1M412.6 221h4.1"/>
<path d="M516.8 223.8h4M516.8 222.3h4M24.6 240.1v4M26.2 240.1v4M45.6 240.1v4M47.1 240.1v4M107.9 250.4v3.8M157.4 248.3v4.1M158.9 248.3v4.1M382.8 246h4M382.8 244.5h4M486.9 247.3h4.1"/>
<path d="M486.9 245.8h4.1M19.6 263.2h4M19.6 261.7h4M140.2 278.4h4.1M140.2 276.9h4.1M319.3 277.2h4M319.3 275.6h4M352.3 277.2h4.1M352.3 275.6h4.1M412.6 261.9h4.1M412.6 260.4h4.1M516.8 263.2h4"/>
<path d="M516.8 261.7h4M69.7 296.6v4.1M71.2 296.6v4.1M382.8 289.9h4M382.8 288.3h4M486.9 291.1h4.1M486.9 289.6h4.1M237.4 319.1h4M237.4 317.5h4M246.3 319.1h4M246.3 317.5h4M255.1 319.1h4.1"/>
<path d="M255.1 317.5h4.1M412.6 305.7h4.1M412.6 304.2h4.1M516.8 307h4M516.8 305.5h4M382.8 329.2h4M382.8 327.7h4M486.9 330.5h4.1M486.9 329h4.1M50 352.5v4M51.6 352.5v4M412.6 345.1h4.1"/>
<path d="M412.6 343.6h4.1M516.8 346.4h4M516.8 344.8h4M111 360.1v4.1M112.5 360.1v4.1M154.8 361.4v4M156.3 361.4v4M203.7 361.4v4M205.2 361.4v4M154.8 386.8v4M156.3 386.8v4M203.7 386.8v4"/>
<path d="M205.2 386.8v4M241.8 386.8v4M243.3 386.8v4"/>
</g>
<g fill="#ffffc2" stroke="#ffffc2" stroke-width=".26">
<path d="M436.9 56h2.5v5.1h-2.5z"/>
<path d="M164.5 387.5h2.5v10.2h-2.5z"/>
<path d="M164.5 362.1h2.5v10.2h-2.5z"/>
<path d="M213.4 362.1h2.5v10.2h-2.5z"/>
<path d="M57.1 47.8h2.6v12.7h-2.6z"/>
<path d="M391.2 297.3h17.7v20.4h-17.7z"/>
<path d="M391.2 336.7h17.7v20.3h-17.7z"/>
<path d="M495.3 132.2h17.8v20.4h-17.8z"/>
<path d="M391.2 214.2h17.7v20.3h-17.7z"/>
<path d="M391.2 253.5h17.7v20.4h-17.7z"/>
<path d="M495.3 298.6h17.8v20.3h-17.8z"/>
<path d="M495.3 338h17.8v20.3h-17.8z"/>
<path d="M495.3 171.6h17.8v20.3h-17.8z"/>
<path d="M495.3 215.4h17.8v20.4h-17.8z"/>
<path d="M495.3 254.8h17.8v20.3h-17.8z"/>
<path d="M360.7 382.4h10.1v15.3h-10.1z"/>
<path d="M384.8 374.2h15.2v2.5h-15.2z"/>
<path d="M254 327.8h80v66.1h-80z"/>
<path d="M141.6 290.4h12.7v13.9h-12.7z"/>
<path d="M196.8 319.6h7.7l3.8-3.8h1.2v1.2h2.6l1.3-1.2h12.7v24.1h-29.3z"/>
<path d="M96.5 369.7h2.6v20.4h-2.6z"/>
<path d="M213.4 387.5h2.5v10.2h-2.5z"/>
<path d="M36.2 362.1h2.5v25.4h-2.5z"/>
<path d="M48.3 362.1h5v25.4h-5z"/>
<path d="M61 74.5h238.7v137.1h-238.7z"/>
<path d="M109.2 369.7h5.1v20.4h-5.1z"/>
<path d="M55.2 240.8h2.6v10.2h-2.6z"/>
<path d="M34.3 240.8h2.5v10.2h-2.5z"/>
<path d="M311.8 20.5h2.5v5.1h-2.5z"/>
<path d="M28.6 270.7h20.3v15.2h-20.3z"/>
<path d="M94.6 287.8h10.2v15.3h-10.2z"/>
<path d="M79.4 297.3h2.5v10.2h-2.5z"/>
<path d="M391.2 131h17.7v20.3h-17.7z"/>
<path d="M522.6 21.8h2.5v5h-2.5z"/>
<path d="M522.6 33.2h2.5v5.1h-2.5z"/>
<path d="M391.2 170.3h17.7v20.4h-17.7z"/>
<path d="M172.7 22.4h12.7v8.9h-12.7z"/>
<path d="M499.7 78.9h2.6v5.1h-2.6z"/>
<path d="M499.7 21.8h2.6v5h-2.6z"/>
<path d="M499.7 33.2h2.6v5.1h-2.6z"/>
<path d="M499.7 44.6h2.6v5.1h-2.6z"/>
<path d="M499.7 56h2.6v5.1h-2.6z"/>
<path d="M499.7 67.5h2.6v5.1h-2.6z"/>
</g>
<g fill="#840000" stroke="#840000" stroke-width=".26">
<path d="M85.7 50.3l2.6 1.3-2.6 1.3z"/>
<path d="M126.4 36.4l2.5-1.3v2.5z"/>
<path d="M137.2 36.4l1.2 2.5h-2.5z"/>
<path d="M153.7 30l2.5 1.3-2.5 1.3z"/>
<path d="M418.5 292.9l2.5-1.3v2.6z"/>
<path d="M418.5 332.3l2.5-1.3v2.5z"/>
<path d="M522.6 127.8l2.5-1.3v2.6z"/>
<path d="M418.5 209.7l2.5-1.3v2.6z"/>
<path d="M418.5 249.1l2.5-1.3v2.6z"/>
<path d="M522.6 294.2l2.5-1.3v2.5z"/>
<path d="M522.6 333.5l2.5-1.2v2.5z"/>
<path d="M522.6 167.2l2.5-1.3v2.5z"/>
<path d="M522.6 211l2.5-1.3v2.6z"/>
<path d="M522.6 250.4l2.5-1.3v2.5z"/>
<path d="M361.4 384.7h2.8v.5h-2.8z"/>
<path d="M365.3 388.8h.7v.8h-.7z"/>
<path d="M366.4 387.3l1.3 .6-1.3 .6z"/>
<path d="M387.3 384.3h2.6l-1.3 2.6z"/>
<path d="M440.7 18.6l3.8 2.5-3.8 2.6z"/>
<path d="M466.5 26.2l1-.4v.8z"/>
<path d="M272.2 26.2l1-.4v.8z"/>
<path d="M235.3 31.3l1-.4v.8z"/>
<path d="M465.2 78.3l1-.4v.8z"/>
<path d="M198.1 338h2.6v1.3h-2.6z"/>
<path d="M198.1 335.4h2.6v1.3h-2.6z"/>
<path d="M198.1 332.9h2.6v1.3h-2.6z"/>
<path d="M198.1 330.4h2.6v1.2h-2.6z"/>
<path d="M198.1 327.8h2.6v1.3h-2.6z"/>
<path d="M198.1 325.3h2.6v1.3h-2.6z"/>
<path d="M198.1 322.7h2.6v1.3h-2.6z"/>
<path d="M198.1 320.2h2.6v1.3h-2.6z"/>
<path d="M108.6 254l.5-.5 .5 1.1z"/>
<path d="M563.1 24.4l1.7-.7a1.45 1.45 0 0 0 1.3-.7l.3-.1a.73 .73 0 0 1 1.2-.2 1.67 1.67 0 0 1 1.5 1.5l.2 .7a.73 .73 0 0 1-.1 1.2 5.7 5.7 0 0 0-1.3 4.4 .71 .71 0 0 1 .2 1.1 1.16 1.16 0 0 0 .4 1.8 1.19 1.19 0 0 1-.1 1.6l-.1 .4a2.11 2.11 0 0 0-.1 2.1l-.3 .7v1a4.7 4.7 0 0 1-.8 4.3l-.3 1.6-.4-1 .1-1.2a2.97 2.97 0 0 1 .3-2.7 1.94 1.94 0 0 1 .2-1.9l.1-2.3-.2-1.5a2.37 2.37 0 0 1-.1-2.1v-.2a1.96 1.96 0 0 1-.6-2.4v-.2a.49 .49 0 0 1-.4-.5 .49 .49 0 0 1 .4-.5l.2-.2v-1.9a.83 .83 0 0 0-.3-1.2l-.8-.4h-1.1l-.9-.3z"/>
<path d="M548.3 24l2.5-.8a4.3 4.3 0 0 0 2.5-.6 2.42 2.42 0 0 0 2 .5 .78 .78 0 0 0 1.2-.1l4.2-1.4 1.3 1a.67 .67 0 0 1 .7 .8l.4 .1-.5 .6a3 3 0 0 0-.8 3.3l.2 1.8 .2 .2-.2 .7a3.6 3.6 0 0 0 .3 3.4 1.25 1.25 0 0 1-.8 1.5l-.7 1.7 .1 2.4-.3 2.9 .1 1.2 .4 .5a1.45 1.45 0 0 1-.4 1.5l-.1 2-.3 .8-.5 .4-.1-.7 .2-.4a1.44 1.44 0 0 0-.3-1.8l-.3-1.1 .1-3.3-.3-.7 .1-.8-.3-.5a7.4 7.4 0 0 1 .9-4.1l-.1-1.2a6.9 6.9 0 0 1-.2-3.3 1.07 1.07 0 0 1-.3-1.2l-.1-1.5a1.04 1.04 0 0 0-.4-1.5v-.4a1.56 1.56 0 0 0 0-1.5l-.3-.1-.3-.5-1.2-.1a.78 .78 0 0 0-1 .3l-.1 1.5-1 .3 .1 2.2a2.1 2.1 0 0 0-.3 2.5l.9 2.5-.3 .8v1.3a1.78 1.78 0 0 1 0 2.4 6.1 6.1 0 0 0-.2 3.4l-.2 2.4 .1 2.2-.5-.7-.5-2.8a3.6 3.6 0 0 1-.5-2.7 1.07 1.07 0 0 1-.1-1.7l.1-.1a3.5 3.5 0 0 0-.2-2.8v-1.7l-.5-1.6a2.21 2.21 0 0 1-.3-2.7l.3-1.1a2.08 2.08 0 0 0-.9-1.9v-.6a.73 .73 0 0 0-.7-.8z"/>
<path d="M454.7 67.5l2.5-1.3v2.5z"/>
<path d="M267.3 30l2.6 1.3-2.6 1.3z"/>
<path d="M267.3 19.9l2.6 1.2-2.6 1.3z"/>
<path d="M411.5 97.3l2.5 1.3-2.5 1.3z"/>
<path d="M102.2 237l2.6-1.2v2.5z"/>
<path d="M99.2 294.2h.7v.7h-.7z"/>
<path d="M100.3 292.7l1.3 .6-1.3 .6z"/>
<path d="M95.4 289.9h2.5l-.2 .7h-2.1z"/>
<path d="M111.1 289.1l2.6 1.3-2.6 1.2z"/>
<path d="M194.3 23.7l2.5 1.2-2.5 1.3z"/>
<path d="M418.5 126.5l2.5-1.2v2.5z"/>
<path d="M418.5 165.9l2.5-1.3v2.6z"/>
<path d="M355.6 29.4l2.5-1.3v2.5z"/>
<path d="M393.7 102.4l1.3 2.5h-2.6z"/>
<circle cx="361.9" cy="387.9" r=".63"/>
<circle cx="365.1" cy="386.6" r=".38"/>
<circle cx="468" cy="24.4" r=".28"/>
<circle cx="468" cy="28" r=".28"/>
<circle cx="273.7" cy="24.4" r=".28"/>
<circle cx="273.7" cy="28" r=".28"/>
<circle cx="236.9" cy="29.5" r=".28"/>
<circle cx="236.9" cy="33.1" r=".28"/>
<circle cx="466.7" cy="80.1" r=".28"/>
<circle cx="466.7" cy="76.5" r=".28"/>
<circle cx="95.9" cy="293.3" r=".63"/>
<circle cx="99.1" cy="292" r=".38"/>
</g>
<g fill="none" stroke="#008484" stroke-width=".26">
<path d="M368.6 16.5a.68 .68 0 0 0-1 .6 .68 .68 0 0 0 1 .7M383.3 16.5l.5-.1 .3 .4-.9 1.1h.9M40.5 26.1l.4-.4v1.3M40.5 27h.7M46.7 25.7l.4 1.3 .4-1.3M216.3 25.8a.56 .56 0 0 0-.8 .5 .56 .56 0 0 0 .8 .5M231.7 25.7l.3 1.3 .3-.9 .2 .9 .3-1.3M373.2 21.5h.5M373.2 29.1h.5M373.4 21v1.1l.3 .2M373.4 28.7v1.1l.3 .1M379.6 25.6h1"/>
<path d="M447.8 46.9l.5 1.5 .5-1.5M464.3 47.3l.4-.4v1.5M464.3 48.4h.9M253.2 78.2l.7-.1v-.4l-.7-.1v1.2M254.5 78.2h.4M255.1 77.6h-.6v1.2h.6M255.7 77.7l.2-.1a.62 .62 0 0 1 .4 .6 .62 .62 0 0 1-.6 .6l-.2-.4zM82.5 87.7v1.1l.3 .2 .5-.2v-1.1M83.7 87.7h.7M84 87.7v1.3M242.6 93.5l.6-.1 .1-.5-.7-.1v1.3M243.9 93.4h.4"/>
<path d="M244.5 92.8h-.6v1.3h.6M244.6 90.9h.6v-.5l-.6-.1v1.2M245.6 92.8l-.6 .3v.7l.2 .3 .4-.2 .1-.4-.2-.2-.5 .2M245.8 90.9h.5M246.4 90.3h-.6v1.2h.6M247.1 92.8l-1.1 1.6M247.6 90.3h-.6l-.1 .6 .6-.1 .1 .6h-.7M249.1 90.2l-1.1 1.6M249.1 83.3h.7v-.5l-.7-.2v1.3M250.4 83.3h.5M251 82.6h-.6v1.3h.6M251.5 82.8l.5-.2 .2 .4-.8 .9h.8"/>
<path d="M254.9 88.4l.6-.1v-.4l-.6-.2v1.3M256.2 88.3h.4M256.8 87.7h-.6v1.3h.6M257.6 87.7l-.3 .9h.7M257.9 88.2v.8M263.1 80.8l.6-.1 .1-.5-.7-.1v1.3M263.2 98.5h.6v-.5l-.6-.1v1.3M264.3 85.8h.6v-.5l-.6-.1v1.3M264.4 80.7h.4M264.4 98.5h.5M264.9 96l.7-.1v-.4l-.7-.2v1.3M265 80.1h-.6v1.3h.6"/>
<path d="M265 97.9h-.6v1.3h.6M265.5 85.8h.5M265.8 98.4l-.3-.3 .5-.2 .3 .2-.1 .2-.7 .4 .3 .5 .5-.3-.3-.5M266.1 85.2h-.6v1.3h.6M266.2 96h.4M266.8 95.3h-.6v1.3h.6M85.4 103h.7M85.8 103v1.2M261.4 116.3h.6l.1-.5-.7-.1v1.2M262 103.6l.6-.1v-.4l-.6-.1v1.2M262 108.7l.6-.1v-.4l-.6-.2v1.3M262.1 111.2l.7-.1v-.4l-.7-.1v1.3"/>
<path d="M262.1 113.8l.7-.1v-.4l-.7-.2v1.3M262.7 116.3h.4M263.2 103.6h.5M263.2 108.7h.5M263.3 106.2l.6-.1 .1-.5-.7-.1v1.3M263.3 115.7h-.6v1.2h.6M263.3 111.2h.5M263.3 113.7h.5M263.8 116l.3-.3v1.2M263.8 116.9h.7M263.8 103h-.6v1.2h.6M263.8 108h-.6v1.3h.6"/>
<path d="M264 110.6h-.7v1.3h.7M264 113.1h-.7v1.3h.7M264.3 103.3l.4-.3v1.2M264.3 108.4l.4-.4v1.3M264.3 104.2h.7M264.3 109.3h.7M264.4 110.9l.4-.3v1.3M264.4 113.5l.4-.4v1.3M264.4 111.9h.8M264.4 114.4h.8M264.5 101.1l.7-.1v-.4l-.7-.2v1.3M264.6 106.1h.4"/>
<path d="M265.2 105.5h-.6v1.3h.6M265.7 105.9l.3-.4v1.3M265.7 106.8h.7M265.8 101h.4M266.4 100.4h-.6v1.3h.6M267.6 101l-.2 .2h-.4l-.1-.6 .5-.2 .2 .3-.1 .7-.1 .2-.4 .1M124.3 128.4v1.2l-.7-1.2v1.2M124.6 136v1.3l-.7-1.3v1.3M124.8 128.4h.7M125 136h.7M125.1 128.4v1.2M125.3 136v1.3"/>
<path d="M125.9 128.5l.2-.1 .5 .1 .1 .7-.2 .4-.6-.1zM126.1 136.2l.3-.2 .5 .2v.6l-.2 .4-.6-.1zM127.2 128.4v1l.3 .2 .5-.2v-1M127.5 136v1l.2 .3 .5-.3v-1M128.4 128.4h.7M128.6 136h.8M128.8 128.4v1.2M129 136v1.3M136.9 138.5l.4 1.3 .4-1.3M137.4 134.1h.4M138 133.4h-.6v1.3h.6M138.1 139.1h.4"/>
<path d="M138.7 138.5h-.6v1.3h.6M139.3 133.4v1.3l-.8-1.3v1.3M139.7 133.4h.7M140 138.5v1.3l-.7-1.3v1.3M140.1 133.4v1.3M140.4 138.5h.7M140.8 138.5v1.3M140.8 133.6l.3-.2 .5 .2v.7l-.1 .4-.7-.2zM141.6 138.7l.2-.2 .5 .2v.7l-.1 .3-.6-.1zM142.2 133.4v1.1l.2 .2 .5-.2v-1.1M142.4 131.5h.4M142.9 138.5v1.1l.2 .2 .5-.2v-1.1"/>
<path d="M143 130.9h-.6v1.3h.6M143.3 133.4h.7M143.7 133.4v1.3M144 138.5h.8M144.3 130.9v1.3l-.7-1.3v1.3M144.4 138.5v1.3M144.7 130.9h.7M145.1 130.9v1.3M145.9 131.1l.2-.2 .5 .2v.9l-.2 .2-.5-.2zM147.2 130.9v1l.2 .3 .5-.3v-1M148.3 123.9h.5M148.3 130.9h.8"/>
<path d="M148.7 130.9v1.3M148.9 123.3h-.6v1.3h.6M150.2 126.4h.4M150.2 123.3v1.3l-.7-1.3v1.3M150.6 123.3h.8M150.7 125.8h-.5v1.3h.5M151 123.3v1.3M151.8 123.5l.2-.2 .5 .2 .1 .6-.2 .4-.6-.1zM152 125.8v1.3l-.7-1.3v1.3M152.5 125.8h.7M152.8 125.8v1.3M153.1 123.3v1l.3 .3 .4-.3v-1"/>
<path d="M153.6 126l.2-.2 .5 .2 .1 .7-.2 .3-.6-.1zM154.3 123.3h.7M154.6 123.3v1.3M154.9 125.8v1.1l.3 .2 .5-.2v-1.1M156.1 125.8h.7M156.4 125.8v1.3M242.7 129h.6v-.5l-.6-.1v1.2M243.9 128.4a.64 .64 0 0 1 .8 .6 .64 .64 0 0 1-.8 .6zM245.2 128.5l.4-.1 .3 .3-.8 .9h.8M247.3 128.3l-1 1.6M259.9 139.2l.6-.1 .1-.4-.7-.2v1.3M260.6 134.1h.6v-.5l-.6-.2v1.3"/>
<path d="M260.8 131.6l.7-.1v-.5l-.7-.1v1.3M261.2 138.5a.64 .64 0 0 1 .7 .7 .64 .64 0 0 1-.7 .6zM261.7 136.6h.6l.1-.5-.7-.1v1.3M261.8 133.4a.64 .64 0 0 1 .8 .7 .64 .64 0 0 1-.8 .6zM262.1 130.9a.64 .64 0 0 1 .7 .6 .64 .64 0 0 1-.7 .7zM263 136a.64 .64 0 0 1 .7 .6 .64 .64 0 0 1-.7 .7zM265 123.9h.7v-.5l-.7-.1v1.3M265.4 126.5l.6-.1v-.4l-.6-.2v1.3M266.3 123.3a.64 .64 0 0 1 .8 .6 .64 .64 0 0 1-.8 .7zM266.6 125.8a.64 .64 0 0 1 .8 .7 .64 .64 0 0 1-.8 .6zM88.6 156.3v1l.2 .3 .5-.3v-1M88.8 158.8v1.1l.3 .2 .5-.2v-1.1"/>
<path d="M89.7 156.3h.8M90 158.8h.7M90.1 156.3v1.3M90.3 158.8v1.3M114.7 146.1h.7M115 146.1v1.3M115.6 148.7h.7M115.8 146.3l.3-.2 .4 .2 .1 .7-.2 .4-.6-.2zM115.9 148.7v1.3M116.7 148.9l.2-.2 .5 .2 .1 .6-.2 .4-.6-.1zM117.1 146.1v1.1l.3 .2 .5-.2v-1.1M117.9 153.9l.3-.1 .4 .1v1l-.2 .1-.5-.1z"/>
<path d="M118 148.7v1l.3 .3 .5-.3v-1M118.3 146.1h.7M118.6 146.1v1.3M118.6 151.2h.8M119 151.2v1.3M119.2 148.7h.7M119.3 153.8v1l.2 .2 .5-.2v-1M119.6 148.7v1.3M119.8 151.4l.2-.2 .5 .2 .1 .7-.2 .3-.6-.1zM120.4 153.8h.7M120.8 153.8v1.2M121.1 151.2v1.1l.3 .2 .4-.2v-1.1"/>
<path d="M122.3 151.2h.7M122.6 151.2v1.3M123.1 143.6v1.3l-.8-1.3v1.3M123.5 143.6h.7M123.9 143.6v1.3M124.6 143.8l.3-.2 .4 .2 .1 .6-.2 .4-.6-.1zM126 143.6v1l.2 .3 .5-.3v-1M127.1 143.6h.7M127.5 143.6v1.3M152.1 141.7h.5M152.8 141.1h-.7v1.2h.7M153.1 141.1l.4 1.2 .5-1.2"/>
<path d="M154.4 141.7h.4M155 141.1h-.6v1.2h.6M156.3 141.1v1.2l-.8-1.2v1.2M156.7 141.1h.7M157 141.1v1.2M157.8 141.2l.3-.1 .5 .1v.7l-.2 .4-.6-.1zM159.2 141.1v1l.2 .2 .5-.2v-1M160.3 141.1h.7M160.7 141.1v1.2M238.7 154.4l.7-.1v-.4l-.7-.1v1.2M240 153.8a.64 .64 0 0 1 .7 .6 .64 .64 0 0 1-.7 .6zM241.2 154.1l.4-.3v1.2"/>
<path d="M241.2 155h.8M242.4 153.9l.5-.1 .3 .3-.8 .9h.8M248.9 151.9l.7-.1v-.4l-.7-.2v1.3M249.3 141.7h.6l.1-.5-.7-.1v1.2M250.2 151.2a.64 .64 0 0 1 .7 .7 .64 .64 0 0 1-.7 .6zM250.6 141.1a.64 .64 0 0 1 .7 .6 .64 .64 0 0 1-.7 .6zM251.4 151.6l.3-.4v1.3M251.4 152.5h.7M251.6 159.5h.6v-.5l-.6-.2v1.3M251.7 141.1h.9l-.6 1.2M252.8 158.8a.64 .64 0 0 1 .8 .7 .64 .64 0 0 1-.8 .6zM254.1 159.2l.3-.4v1.3"/>
<path d="M260.4 149.3h.6l.1-.5-.7-.1v1.3M261.7 146.8h.6v-.5l-.6-.2v1.3M261.7 148.7a.64 .64 0 0 1 .7 .6 .64 .64 0 0 1-.7 .7zM262 144.3l.6-.1v-.5l-.6-.1v1.3M262.2 157l.6-.1v-.5l-.6-.1v1.3M262.9 146.1a.64 .64 0 0 1 .8 .7 .64 .64 0 0 1-.8 .6zM263.2 143.6a.64 .64 0 0 1 .8 .6 .64 .64 0 0 1-.8 .7zM263.4 156.3a.64 .64 0 0 1 .7 .6 .64 .64 0 0 1-.7 .7zM264.6 156.7l.4-.4v1.3M264.6 157.6h.8M81.9 174.1v1l.2 .3 .5-.3v-1M83 174.1h.7"/>
<path d="M83.4 174.1v1.3M120.4 162h.4M121 161.4h-.6v1.3h.6M122.3 161.4v1.3l-.8-1.3v1.3M122.3 179.8h.4M122.7 161.4h.7M122.9 179.2h-.6v1.2h.6M123.1 161.4v1.3M123.9 161.6l.2-.2 .5 .2v.6l-.1 .4-.6-.1zM124.2 179.2v1.2l-.8-1.2v1.2M124.6 179.2h.7M124.9 179.2v1.2"/>
<path d="M125.2 161.4v1l.2 .3 .5-.3v-1M125.8 179.2h.4l.2 .1 .1 .7-.3 .4-.5-.1v-.7zM126.3 161.4h.8M126.7 161.4v1.3M126.7 177.2h.4M127.1 179.2v1l.2 .2 .5-.2v-1M127.3 176.6h-.6v1.3h.6M128.2 179.2h.7M128.6 176.6v1.3l-.8-1.3v1.3M128.6 179.2v1.2M129 176.6h.7M129.4 176.6v1.3"/>
<path d="M130.1 176.8l.3-.2 .5 .2v.7l-.2 .3-.6-.1zM131.5 176.6v1.1l.2 .2 .5-.2v-1.1M132.6 176.6h.7M133 176.6v1.3M134.7 169.6h.5M135.3 169h-.6v1.3h.6M136.6 169v1.3l-.7-1.3v1.3M137 169h.7M137.4 169v1.3M138.2 169.2l.2-.2 .5 .2 .1 .6-.2 .4-.6-.1zM139.5 169v1l.3 .3 .4-.3v-1M140.7 169h.7"/>
<path d="M141 169v1.3M147.1 171.5l.4 1.3 .4-1.3M148.3 172.2h.5M148.9 171.5h-.6v1.3h.6M150.2 171.5v1.3l-.7-1.3v1.3M150.6 171.5h.8M151 171.5v1.3M151.8 171.7l.2-.2 .5 .2 .1 .7-.2 .4-.6-.2zM153.1 171.5v1.1l.3 .2 .4-.2v-1.1M154.3 171.5h.7M154.6 171.5v1.3M229.7 174.7l.7-.1v-.4l-.7-.1v1.3"/>
<path d="M230.1 177.3l.7-.1v-.4l-.7-.2v1.3M231.7 174.2a.56 .56 0 0 0-.8 .5 .56 .56 0 0 0 .8 .5M232.2 176.8a.56 .56 0 0 0-.8 .5 .56 .56 0 0 0 .8 .5M232.2 174.2l.5-.1 .2 .3-.7 1h.7M232.6 176.6h.7l-.4 .5 .4 .1-.1 .6h-.6M234.4 174l-1.1 1.7M234.8 176.6l-1.1 1.6M235.5 174.2h-.6l-.1 .4a.5 .5 0 0 1 .5 .2 .5 .5 0 0 1 .1 .5h-.7M252.7 179.8h.6v-.5l-.6-.1v1.2M254.1 160.1h.7M254.7 179.3a.56 .56 0 0 0-.8 .5 .56 .56 0 0 0 .8 .5M263.2 162h.6v-.5l-.6-.1v1.3"/>
<path d="M264.4 161.4a.64 .64 0 0 1 .8 .6 .64 .64 0 0 1-.8 .7zM265.7 161.7l.3-.3v1.3M265.7 162.7h.7M266.5 169.7l.6-.1 .1-.5-.7-.1v1.3M273.8 172.2l.7-.1v-.4l-.7-.2v1.3M122.3 184.2v1.3l-.8-1.3v1.3M122.7 184.2h.7M123.1 184.2v1.3M123.9 184.4l.2-.2 .5 .2v.7l-.1 .4-.6-.2zM125.2 184.2v1.1l.2 .2 .5-.2v-1.1M126.3 184.2h.8M126.4 186.8v1.3l-.7-1.3v1.3"/>
<path d="M126.7 184.2v1.3M126.9 186.8h.7M127.2 186.8v1.3M128 187l.3-.2 .5 .2v.6l-.2 .4-.6-.1zM129.4 186.8v1l.2 .3 .5-.3v-1M130.5 186.8h.7M130.9 186.8v1.3M141.7 189.9h.4M142.3 189.3h-.6v1.3h.6M142.6 189.3l.5 1.3 .4-1.3M143.9 189.9h.4M144.5 189.3h-.6v1.3h.6"/>
<path d="M145.8 189.3v1.3l-.7-1.3v1.3M146.2 189.3h.7M146.5 191.8l-1.1 1.6M146.6 189.3v1.3M146.9 192.5h.5M147.4 189.5l.2-.2 .5 .2 .1 .7-.2 .3-.6-.1zM147.5 191.9h-.6v1.2h.6M147.9 191.9l.4 1.2 .5-1.2M148.7 189.3v1.1l.2 .2 .5-.2v-1.1M149.2 192.5h.4M149.8 191.9h-.6v1.2h.6M149.9 189.3h.7"/>
<path d="M150.2 189.3v1.3M151.1 191.9v1.2l-.8-1.2v1.2M151.5 191.9h.7M151.5 197.6h.5M151.8 191.9v1.2M152.1 196.9h-.6v1.3h.6M152.3 195h.5M152.6 192l.3-.1 .5 .1v.7l-.2 .4-.6-.1zM152.9 194.4h-.6v1.3h.6M153.3 194.4l.4 1.3 .5-1.3M153.4 196.9v1.3l-.7-1.3v1.3M153.8 196.9h.8"/>
<path d="M154 191.9v1l.2 .2 .5-.2v-1M154.2 196.9v1.3M154.6 195h.4M155 197.1l.2-.2 .5 .2 .1 .7-.2 .4-.6-.2zM155.1 191.9h.7M155.2 194.4h-.6v1.3h.6M155.5 191.9v1.2M156.3 196.9v1.1l.3 .2 .4-.2v-1.1M156.4 194.4v1.3l-.7-1.3v1.3M156.9 194.4h.7M157.2 194.4v1.3M157.5 196.9h.7"/>
<path d="M157.8 196.9v1.3M158 194.6l.3-.2 .4 .2 .1 .6-.2 .4-.6-.1zM159.3 194.4v1l.3 .3 .5-.3v-1M160.5 194.4h.7M160.9 194.4v1.3M169.6 181.7a.64 .64 0 0 1 .7 .6 .64 .64 0 0 1-.7 .7zM171.8 181.7l-1.1 1.6M172.2 182.3h.4M172.8 181.7h-.6v1.3h.6M173.1 181.7l.5 1.3 .4-1.3M174.4 182.3h.4M175 181.7h-.6v1.3h.6"/>
<path d="M176.3 181.7v1.3l-.7-1.3v1.3M176.7 181.7h.7M177.1 181.7v1.3M177.9 181.9l.2-.2 .5 .2v.6l-.1 .4-.6-.1zM179.2 181.7v1l.2 .3 .5-.3v-1M180.3 181.7h.8M180.7 181.7v1.3M187.4 199.5a.64 .64 0 0 1 .7 .6 .64 .64 0 0 1-.7 .7zM189.6 199.4l-1.1 1.7M190.6 199.5h-.6v1.3h.6M191 199.5l.4 1.3 .4-1.3M192.9 199.5h-.6v1.3h.6"/>
<path d="M194.1 199.5v1.3l-.7-1.3v1.3M194.5 199.5h.8M194.9 199.5v1.3M195.7 199.7l.2-.2 .5 .2 .1 .6-.2 .4-.6-.1zM197 199.5v1l.3 .3 .4-.3v-1M198.2 199.5h.7M198.5 199.5v1.3M218.7 192.5h.6l.1-.5-.7-.1v1.2M219.2 197.6l.7-.1v-.4l-.7-.2v1.3M220.7 192a.56 .56 0 0 0-.8 .5 .56 .56 0 0 0 .8 .5M221.2 197.1a.56 .56 0 0 0-.8 .5 .56 .56 0 0 0 .8 .5M221.7 197.3l.3-.4v1.3"/>
<path d="M221.7 198.2h.7M221.9 192.4l-.2 .3-.4-.1v-.6l.4-.1 .2 .2v.7l-.2 .3h-.4M222.9 187.4l.7-.1v-.4l-.7-.1v1.3M222.9 197.3l.4-.4v1.3M222.9 198.2h.7M223.2 184.9l.7-.1v-.4l-.7-.2v1.3M223.4 191.8l-1.1 1.6M223.4 195.1l.7-.1v-.5l-.7-.1v1.3M223.8 191.9v1.2M224.2 199.6a.56 .56 0 0 0-.8 .5 .56 .56 0 0 0 .8 .5M224.4 192l.4-.1 .3 .3-.8 .9h.8M224.7 199.8l.4-.3v1.3"/>
<path d="M224.9 186.9a.56 .56 0 0 0-.8 .5 .56 .56 0 0 0 .8 .5M225.1 196.9l-1.1 1.6M225.2 184.4a.56 .56 0 0 0-.8 .5 .56 .56 0 0 0 .8 .5M225.3 186.8h.9l-.6 1.3M225.5 194.5a.56 .56 0 0 0-.8 .5 .56 .56 0 0 0 .8 .5M225.5 196.9v1.1l.2 .2 .5-.2v-1.1M225.9 194.8l.4-.4v1.3M225.9 199.6l.5-.1 .2 .3-.7 1h.7M225.9 195.7h.7M226.3 184.2l-.4 .2-.2 .4v.6l.6 .1v-.7l-.4-.1-.2 .3M226.3 191.9h-.6l-.1 .4a.5 .5 0 0 1 .5 .2 .5 .5 0 0 1 .1 .6h-.6M226.5 193.3h1"/>
<path d="M227.3 194.5l.1-.1a.62 .62 0 0 1 .5 .7 .62 .62 0 0 1-.6 .5l-.2-.4zM227.6 186.7l-1.1 1.7M227.9 184.2l-1.1 1.6M228 186.8v1.3M228.1 199.4l-1.1 1.7M228.3 184.2v1.3M228.5 186.9l.5-.1 .3 .3-.8 1h.8M228.5 199.5v1l.3 .3 .5-.3v-1M228.8 184.4l.5-.2 .2 .4-.7 .9h.7M229.3 194.4l-1.1 1.6M230.4 194.5h-.6l-.1 .4a.5 .5 0 0 1 .5 .2 .5 .5 0 0 1 .1 .5h-.6M230.5 186.9h-.7v.4a.5 .5 0 0 1 .5 .2 .5 .5 0 0 1 0 .5h-.6"/>
<path d="M230.8 184.3h-.7v.4a.5 .5 0 0 1 .5 .2 .5 .5 0 0 1 0 .6h-.6M233.3 190l.7-.1v-.4l-.7-.2v1.3M235.4 189.5a.56 .56 0 0 0-.8 .5 .56 .56 0 0 0 .8 .5M236.1 189.9l-.2-.1v-.3l.4-.2 .3 .3-.1 .2-.7 .3 .3 .5 .5-.2-.3-.5M238 189.3l-1.1 1.6M238.3 189.3h.7M238.6 189.3v1.3M252.7 182.4l.6-.1v-.5l-.6-.1v1.3M254.7 181.8a.56 .56 0 0 0-.8 .5 .56 .56 0 0 0 .8 .5M136.6 207.1l.4 1.3 .5-1.3M137.9 207.7h.4M138.5 207.1h-.6v1.3h.6"/>
<path d="M139.8 207.1v1.3l-.8-1.3v1.3M140.2 207.1h.7M140.5 207.1v1.3M141.3 207.3l.3-.2 .5 .2v.6l-.2 .4-.6-.1zM142.6 207.1v1l.3 .3 .5-.3v-1M143.8 207.1h.7M144.2 207.1v1.3M151.1 204.5l-1.1 1.6M151.5 205.2h.4M152.1 204.6h-.6v1.2h.6M152.5 204.6l.4 1.2 .4-1.2M153.7 205.2h.5"/>
<path d="M154.3 204.6h-.6v1.2h.6M155.6 204.6v1.2l-.7-1.2v1.2M156 204.6h.7M156.4 204.6v1.2M157.2 204.7l.2-.1 .5 .1 .1 .7-.2 .4-.6-.1zM158.5 204.6v1l.2 .2 .5-.2v-1M159.6 204.6h.8M160 204.6v1.2M167.9 202l-1.1 1.6M168.3 202.6h.4M168.9 202h-.6v1.3h.6M169.3 202l.4 1.3 .4-1.3"/>
<path d="M170.5 202.6h.5M171.1 202h-.6v1.3h.6M172.4 202v1.3l-.7-1.3v1.3M172.8 202h.8M173.2 202v1.3M174 202.2l.2-.2 .5 .2 .1 .7-.3 .4-.5-.2zM175.3 202v1.1l.3 .2 .4-.2v-1.1M176.5 202h.7M176.8 202v1.3M190 200.1h.4M192.3 200.1h.4M222.2 200.1l.7-.1v-.4l-.7-.1v1.3"/>
<path d="M224.7 200.8h.8M271.2 207.8l.6-.1v-.5l-.6-.1v1.3M272.8 205.2h.7v-.5l-.7-.1v1.2M273.2 207.2a.56 .56 0 0 0-.8 .5 .56 .56 0 0 0 .8 .5M274.9 204.7a.56 .56 0 0 0-.8 .5 .56 .56 0 0 0 .8 .5M283.3 202.7l.6-.1 .1-.4-.7-.2v1.3M173.3 257.3h.7M96.4 296.4h1.3M96.9 296.4v.4l.2 .2 .6-.1v-.5M101.1 297.3a.64 .64 0 0 1 .8 .6 .64 .64 0 0 1-.8 .6zM102.4 298.1h1M150.7 294.7a.64 .64 0 0 1 .7 .7 .64 .64 0 0 1-.7 .6z"/>
<path d="M151.9 295.5h1M284.6 317.8l.8-.1v-.6l-.8-.1v1.5M302.9 316.9l-.3 1.1h.9M303.3 317.5v1M195.2 322.7a.64 .64 0 0 1 .7 .6 .64 .64 0 0 1-.7 .6zM288.7 332.9l.6-.1 .1-.5-.7-.1v1.3M289.7 330.3h.6v-.5l-.6-.1v1.2M290.6 332.3a.57 .57 0 0 0-.7 .6 .57 .57 0 0 0 .8 .4v-.4h-.3M291.6 329.7a.57 .57 0 0 0-.7 .6 .57 .57 0 0 0 .8 .5v-.4h-.3M280.7 347.8l.4-.4v1.3M280.7 346.2h.8M280.7 348.7h.8"/>
<path d="M281.9 347.8l.4-.4v1.3M281.9 348.7h.8M282 345l.2-.1a.63 .63 0 0 1 .5 .7 .63 .63 0 0 1-.6 .5l-.2-.4zM283.7 352.6l.5-.1 .3 .4-.8 .9h.8M289.8 355.1h.8l-.5 .4 .4 .2v.5h-.7M297.9 358.9l.4-1.3 .4 1.3M298 358.5h.6M299.9 357.6v1.3l-.7-1.3v1.3M300.5 350.6l.7-.1v-.4l-.7-.1v1.2M301.6 348.1l.6-.1v-.4l-.6-.2v1.3M313.7 355.7l.7-.1v-.4l-.7-.1v1.2M314 355.7l.4 .6"/>
<path d="M317.6 352.6a.56 .56 0 0 0-.8 .6 .56 .56 0 0 0 .8 .5M274.5 363.2l-.3-.3 .5-.2 .3 .2-.1 .2-.7 .4 .3 .4 .5-.2-.3-.5M275 360.7l-.2 .2h-.4v-.6l.4-.2 .2 .3v.7l-.2 .3h-.4M275.3 370.3h.8l-.4 .5 .4 .1v.5h-.8M279.7 375.3l-.3 .9h.8M280 375.8v.8M281.5 367.9l.4-.1 .3 .3-.8 .9h.8M288.2 377.9l-.3 .9h.7M288.5 378.3v.9M289.2 361.4l.5-1.3 .4 1.3M289.4 361.1h.6M291.2 360.1v1.3l-.7-1.3v1.3"/>
<path d="M295.4 363.9l.4-1.2 .4 1.2M295.5 363.6h.6M311.6 376.6l.4-1.2 .4 1.2M311.7 376.3h.6M312.8 374.1l.4-1.3 .4 1.3M312.9 373.8h.6M314 369l.4-1.2 .4 1.2M314 371.6l.4-1.3 .4 1.3M314.1 368.7h.6M314.1 371.2h.6M317.6 378.6l.6-.1v-.5l-.6-.1v1.3M317.9 378.6l.4 .6"/>
<path d="M267.4 388.9l.6-.1-.1-.2-.4-.1-.1 .2v.6h.5M317.6 383.7l.6-.1v-.5l-.6-.1v1.3M317.6 386.2l.6-.1v-.4l-.6-.2v1.3M317.6 381.1h.6v-.5l-.6-.1v1.2M317.6 388.7h.6v-.5l-.6-.1v1.2M317.6 391.3l.6-.1v-.5l-.6-.1v1.3M317.9 383.7l.4 .6M317.9 386.2l.4 .6M317.9 381.1l.4 .6M317.9 388.7l.4 .6M317.9 391.3l.4 .6M362.5 391h1.2v.5h-.7v-.5"/>
<path d="M367.2 391.9a.64 .64 0 0 1 .7 .6 .64 .64 0 0 1-.7 .7zM368.5 392.7h.9M390.3 384.3a.57 .57 0 0 0-.7 .6 .57 .57 0 0 0 .8 .5v-.4h-.3M400.9 386.1h-.4l-.2 .2 .1 .6h.5M400.9 385.6v1.3"/>
</g>
<path d="M155.5 227.1l.7-.1 .1-.5-.8-.2v1.6M157 226.9h.6l.1 1M157.7 227.2l-.7 .3 .2 .4 .5-.1M201.8 227l.6-.1 .1 1M202.5 227l.2-.2 .3 .1 .1 1M203.8 227l.6-.1 .1 1M203.8 226.8v1.1M204.5 227l.2-.2 .4 .1 .1 1" fill="none" stroke="#840084" stroke-width=".26"/>
<path d="M25.5 75.1h2.3v5.1h-2.3z" fill="none" stroke="#840000" stroke-width=".3"/>
<g fill="none" stroke="#008400" stroke-width=".26">
<path d="M411.5 19.9h-3.8v20.3h3.8M414 19.9h5.1v20.3M47.6 21.8v26.6M67.3 21.8v8.8M75.6 28.7h9.5M75.6 21.1h9.5M106 21.1h-6.3v10.2M113.7 21.1h6.3v10.2h17.2v1.3M122.6 36.4h-2.6v5M149.9 24.9v8.9M160 21.1v10.2M167.6 34.5v1.9h22.9v-1.9"/>
<path d="M167.6 24.9v1.9M190.5 24.9v1.9M214 33.8h5.1M216.5 28.7h2.6M236.9 21.1v5.1M236.9 36.4h10.7M266.1 26.2h-2.6v5.1M273.7 31.3h3.2M302.9 24.3h5.1M306.7 21.8h1.3M343.5 29.4h8.3M361.9 21.8h-24.7v15.2h24.7"/>
<path d="M389.9 21.8v3.8h11.4v11.4h-10.1M389.9 29.4h2.5M435.6 21.1h1.9M457.8 26.2h2.6M459.1 26.2v5.1M468 31.3v5.1h-3.2M468 21.1h-20.3v7.6M515 34.5v2.5h3.8M515 23v2.6h3.8M63.5 51.6h3.2M63.5 49.1h1.9M63.5 59.2h14"/>
<path d="M63.5 56.7h14M63.5 54.1h14M137.2 42.7v1.3M149.9 41.4v2.6h-27.3M221 59.9h71.1M221 52.2h71.1M395.6 50.3v26.7M414 40.2h8.9M416.6 50.3v8.9M443.2 59.9h3.2v15.8h1.3M446.4 50.3v1.9M466.7 59.9v13.3"/>
<path d="M21.6 77.6h1.3M30.5 77.6h1.2M123.2 66.8h88.9M446.4 67.5h4.4M457.8 78.3h1.3M461 67.5h17.2M19.7 99.9h1.9v7.6h1.3M22.2 85.3h8.9M31.7 99.9v7.6h-1.2M358.1 87.8h-6.3v10.8M365.8 87.8h6.3v10.8h21.6M406.4 98.6h1.3"/>
<path d="M407 92.2v7.7M466.7 83.4v2.5M478.2 82.7v3.2h-19.7M336.5 103.7h15.3M343.5 111.3h8.9M384.8 101.1h-12.7v2.6M407 107.5v1.3M417.8 106.2v2.6M428 106.2v2.6M438.1 106.2v2.6h-63.5M502.3 101.8h31.7M504.2 109.4h29.8"/>
<path d="M388.6 133.5h-15.9v2.6M411.5 133.5h3.2M411.5 138.6h5.7M414.7 126.5v8.3M431.8 137.3h-1.3v1.3h-5.7M459.7 132.2v10.2M492.8 134.8h-15.9v2.5M515.6 134.8h3.2M515.6 139.9h5.7M518.8 127.8v8.3M535.9 138.6h-1.2v1.3h-5.7M563.9 133.5v10.2"/>
<path d="M372.7 143.7h15.9M388.6 148.8v2.5M411.5 143.7h3.2v1.2h17.1v2.6M411.5 148.8h5.7M431.8 142.4h-1.3v6.4h-5.7M459.7 144.9v5.1M476.9 144.9h15.9M492.8 150v2.6M515.6 144.9h3.2v1.3h17.1v2.6M515.6 150h5.7M535.9 143.7h-1.2v6.3h-5.7M563.9 146.2v5.1"/>
<path d="M388.6 172.9h-16.5v2.5M411.5 172.9h3.2M411.5 178h5.7M414.7 165.9v8.3M431.8 176.7h-1.3v1.3h-5.7M459.7 171.6v10.2M492.8 174.2h-16.6v2.5M515.6 179.2h5.7M515.6 174.2h3.2M518.8 167.2v8.2M535.9 178h-1.2v1.2h-5.7M563.9 172.9v10.1"/>
<path d="M372.1 183h16.5M388.6 188.1v2.6M411.5 183h3.2v1.3h17.1v2.6M411.5 188.1h5.7M431.8 181.8h-1.3v6.3h-5.7M459.7 184.3v5.1M476.2 184.3h16.6M492.8 189.4v2.5M515.6 184.3h3.2v1.3h17.1v2.5M515.6 189.4h5.7M535.9 183h-1.2v6.4h-5.7M563.9 185.6v5.1"/>
<path d="M170.2 219.2v7.7h45.7M175.3 219.2v7.7M180.3 219.2v7.7M185.4 219.2v7.7M190.5 219.2v7.7M388.6 216.7h-15.9v2.5M411.5 216.7h3.2M414.7 209.7v8.3M459.7 215.4v10.2M492.8 218h-15.9v2.5M515.6 218h3.2M518.8 211v8.2"/>
<path d="M563.9 216.7v10.2M21.6 237.7v6.9h8.9M42.5 237.7v6.9h8.9M98.4 237v2.6h11.5M108.6 237h1.3M262.9 239.6v1.2M273 239.6v1.2M284.5 239.6v1.2M295.9 239.6v1.2M372.7 226.9h15.9M388.6 231.9v2.6M411.5 226.9h3.2v1.2h17.1v2.6"/>
<path d="M411.5 221.8h5.7M411.5 231.9h5.7M431.8 220.5h-1.3v1.3h-5.7M431.8 225.6h-1.3v6.3h-5.7M459.7 228.1v5.1M476.9 228.1h15.9M492.8 233.2v2.6M515.6 228.1h3.2v1.3h17.1v2.5M515.6 223.1h5.7M515.6 233.2h5.7M535.9 226.9h-1.2v6.3h-5.7M535.9 221.8h-1.2v1.3h-5.7"/>
<path d="M563.9 229.4v5.1M27.9 249.7h2.6M29.2 242.1h1.3M48.9 249.7h2.5M50.2 242.1h1.2M139.7 252.9h23.5M139.7 255.4h23.5M147.3 240.2v7.6M153 247.8h10.2M153 240.2v17.8h10.2M154.3 247.8v2.6M155.6 242.7v2.6h7.6"/>
<path d="M155.6 240.2h-14.6v5.1M161.9 250.4h1.3M238.1 242.7v5.1M262.9 240.2h.6M273 240.2h.7M284.5 240.2h.6M295.9 240.2h.6M388.6 256.1h-16.5v2.5M411.5 256.1h3.2M414.7 249.1v8.2M431.8 259.9h-1.3v1.3h-5.7M459.7 254.8v10.2"/>
<path d="M492.8 257.3h-16.6v2.6M515.6 257.3h3.2M518.8 250.4v8.2M563.9 256.1v10.1M372.1 266.2h16.5M388.6 271.3v2.6M411.5 271.3h5.7M411.5 266.2h3.2v1.3h17.1v2.5M411.5 261.2h5.7M431.8 265h-1.3v6.3h-5.7M459.7 267.5v5.1M476.2 267.5h16.6"/>
<path d="M492.8 272.6v2.5M515.6 267.5h3.2v1.3h17.1v2.5M515.6 262.4h5.7M515.6 272.6h5.7M535.9 266.2h-1.2v6.4h-5.7M535.9 261.2h-1.2v1.2h-5.7M563.9 268.8v5.1M26 280.8v7.7h12.7M66.7 298.6v2.6h8.9M74.3 298.6h1.3M121.3 297.3h7.6M136.5 291.6h-15.2v11.5"/>
<path d="M159.4 291.6h4.4M159.4 297.3h8.2M188 298h1.9M219.7 298h1.9M251.5 298h1.9M283.2 298h1.9M388.6 299.9h-15.9v2.5M411.5 299.9h3.2M414.7 292.9v8.3M459.7 298.6v10.2M518.8 294.2v8.2M563.9 299.9v10.1"/>
<path d="M72.4 306.2h3.2M72.4 303.7h3.2M239.4 314.5h17.8M372.7 310h15.9M388.6 315.1v2.6M411.5 310h3.2v1.3h17.1v2.6M411.5 305h5.7M411.5 315.1h5.7M431.8 303.7h-1.3v1.3h-5.7M431.8 308.8h-1.3v6.3h-5.7M459.7 311.3v5.1M476.9 311.3h15.9"/>
<path d="M492.8 316.4v2.5M492.8 301.2h-15.9v2.5M515.6 306.2h5.7M515.6 311.3h3.2v1.3h17.1v2.5M515.6 301.2h3.2M515.6 316.4h5.7M535.9 305h-1.2v1.2h-5.7M535.9 310h-1.2v6.4h-5.7M563.9 312.6v5.1M237.5 330.4v5h8.9M239.4 322.1h17.8M245.1 330.4h1.3"/>
<path d="M245.7 328.5v1.9M269.2 320.2h5.1M388.6 339.3h-16.5v2.5M411.5 339.3h3.2M414.7 332.3v8.2M459.7 338v10.1M518.8 333.5v8.3M563.9 339.3v10.1M47 354.5h-2.6v31.7M54.6 354.5h2.5v31.7M105.4 359.6v29.2M175.3 343.7h7.6"/>
<path d="M182.9 341.2h-1.9v5.7M372.1 349.4h16.5M388.6 354.5v2.5M411.5 349.4h3.2v1.3h17.1v2.5M411.5 354.5h5.7M411.5 344.3h5.7M431.8 343.1h-1.3v1.2h-5.7M431.8 348.1h-1.3v6.4h-5.7M459.7 350.7v5.1M476.2 350.7h16.6M492.8 355.8v2.5M492.8 340.5h-16.6v2.6"/>
<path d="M515.6 350.7h3.2v1.3h17.1v2.5M515.6 355.8h5.7M515.6 345.6h5.7M515.6 340.5h3.2M535.9 344.3h-1.2v1.3h-5.7M535.9 349.4h-1.2v6.4h-5.7M563.9 352v5M104.1 362.1h3.8M115.6 362.1h2.5v26.7M131.4 371h29.3M137.2 360.8h-5.8v2.6M137.2 368.5h23.5"/>
<path d="M138.4 378.6h7.6M144.8 376.1h1.2M151.8 363.4v2.5h8.9M159.4 363.4h1.3M180.3 371h29.2M186.1 368.5h23.4M186.1 360.8h-5.8v2.6M187.3 378.6h7.6M193.7 376.1h1.2M200.7 363.4v2.5h8.8M208.3 363.4h1.2M356.9 360.8v2.6"/>
<path d="M131.4 396.4h29.3M137.2 386.2h-5.8v2.6M137.2 393.9h23.5M151.8 388.8v2.5h8.9M159.4 388.8h1.3M180.3 396.4h29.2M186.1 393.9h23.4M186.1 386.2h-5.8v2.6M200.7 388.8v2.5h8.8M208.3 388.8h1.2M238.8 388.8v2.5h7.6M373.4 385h3.2"/>
<path d="M138.4 404h7.6M144.8 401.5h1.2M187.3 404h7.6M193.7 401.5h1.2M269.2 401.5h5.1"/>
</g>
<g fill="none" stroke="#000" stroke-width=".26">
<path d="M99.1 19.5h.7M99.5 19.5v1.3M95 27.1v1.1l.2 .2M321.3 89.9h.5l.1 .7M321.6 92.4h.4l.1 .8M321.9 90.1l-.6 .2v.3h.6M322.1 92.7l-.6 .2 .2 .3 .4-.1M322.5 89.4v1.1l.2 .1M322.7 91.9v1.1l.2 .2M322.7 99.5v1.1l.2 .2M316.1 116h.7M320.6 103.3h.8"/>
<path d="M321.3 105.1h.5l.1 .8M321.3 112.7h.5l.1 .8M321.6 100h.4l.1 .8M321.6 110.2h.4l.1 .8M321.9 105.4l-.6 .2v.2h.6M321.9 113l-.6 .2v.3h.6M322.1 100.3l-.6 .2 .2 .3h.4M322.1 110.4l-.6 .3 .2 .3 .4-.1M322.5 104.6v1.1l.2 .2M322.5 112.2v1.1l.2 .2M322.7 109.7v1.1l.2 .2M38.9 128.1h.6v-.5l-.6-.1v1.2"/>
<path d="M38.9 130.7l.6-.1v-.5l-.6-.1v1.3M319.1 131.3h.8M321.4 155.5l.5-.1 .2 .4-.8 .9h.8M321.4 153.2l.3-.3v1.2M321.4 154.1h.7M421.5 142.1v1.2h.6M466.6 143.3v1.3h.6M525.6 143.3v1.3h.6M570.7 144.6v1.3h.6M38.7 168.8l.6-.1v-.5l-.6-.1v1.3M38.7 171.3h.6v-.5l-.6-.1v1.2M38.8 161.2l.7-.1v-.5l-.7-.1v1.3"/>
<path d="M39.8 176.4l.6-.1 .1-.4-.7-.2v1.3M39.8 178.9h.6l.1-.5-.7-.1v1.2M322.5 175.7h.7l-.4 .5 .4 .1-.1 .7-.6-.1M322.5 171l.4-.3v1.2M322.5 173.3l.5-.1 .2 .3-.7 1h.7M322.5 171.9h.7M322.7 168.2l.1-.1a.63 .63 0 0 1 .5 .7 .63 .63 0 0 1-.6 .5l-.2-.4zM322.8 178.2l-.3 .9h.8M323.1 178.7v.8M31.3 189.1l.6-.1 .1-.4-.7-.2v1.3M34.9 191.6h.6v-.5l-.6-.1v1.2M39.8 181.5l.6-.1 .1-.5-.7-.1v1.3"/>
<path d="M40.1 184l.6-.1v-.4l-.6-.1v1.2M52.4 191.5h.5l.1 .7M317 193.6l.5-.1 .3 .4-.8 .9h.8M317 197.3h.8M317.2 198.7l.1-.1a.62 .62 0 0 1 .5 .7 .62 .62 0 0 1-.6 .5l-.2-.4zM321.3 191.5h.5l.1 .7M321.3 186.4h.5l.1 .8M321.6 188.9h.3l.2 .1v.7h-.4l-.2-.2 .1-.2 .5-.1M321.6 183.8h.4l.1 .8M321.9 191.7l-.6 .2v.3h.6M321.9 186.6l-.6 .3v.2h.6M322.1 184.1l-.6 .2 .2 .3h.4"/>
<path d="M322.5 191v1.1l.2 .1M322.5 185.9v1.1l.2 .2M322.7 188.4v1.1l.2 .2M322.7 183.4v1l.2 .2M323.2 180.8h-.6l-.1 .6h.6l.1 .6h-.7M421.5 182.1h.6v-.5l-.6-.2v1.3M466.6 183.4l.6-.1v-.5l-.6-.1v1.3M466.9 183.4l.4 .6M525.6 183.4l.6-.1 .1-.5-.7-.1v1.3M570.7 184.6h.6l.1-.5-.7-.1v1.3M571 184.6l.4 .7M37.9 204.2h.5v.7"/>
<path d="M37.9 204.1v.8M38.1 206.8l.5-.1 .1 .8M38.1 206.6v.9M38.4 204.3l.5-.1 .1 .7M38.7 206.8l.5-.1v.8M52.9 206.2v1.1l.2 .2M52.9 203.7v1.1l.2 .1M282.4 239.9h.8M309 237.3l.5-.1 .1 .8M309 237.1v.9M309.3 233.4h.5v.8M309.3 233.3v.9"/>
<path d="M309.6 237.3l.5-.1v.8M309.8 233.5l.5-.1 .1 .8M324 232.9v1.1l.2 .2M324 236.7v1.1l.2 .2M421.5 225.3v1.2h.6M466.6 226.5v1.3h.6M525.6 226.5v1.3h.6M570.7 227.8v1.3h.6M80.2 251.3h.6v-.5l-.6-.1v1.2M126.4 254.5l.7-.1v-.4l-.7-.2v1.3M309 252.5l.5-.1 .1 .8M309 244.9l.5-.1 .1 .8"/>
<path d="M309 244.7v.9M309 252.4v.8M309.3 248.7l.5-.1v.8M309.3 241.1l.5-.1v.8M309.3 240.9v.9M309.3 248.6v.8M309.6 252.5l.5-.1v.8M309.6 244.9l.5-.1v.8M309.8 248.7l.5-.1 .1 .8M309.8 241.1l.5-.1 .1 .8M324 248.1v1.1l.2 .2M324 251.9v1.1l.2 .2"/>
<path d="M324 244.3v1.1l.2 .2M324 240.5v1.1l.2 .2M421.5 265.3l.6-.1v-.4l-.6-.2v1.3M466.6 266.6l.6-.1v-.5l-.6-.1v1.3M466.9 266.6l.4 .6M525.6 266.6l.6-.1 .1-.5-.7-.1v1.3M570.7 267.8h.6l.1-.5-.7-.1v1.2M571 267.8l.4 .6M108.9 297.2h1M159.7 293.8a.64 .64 0 0 1 .8 .7 .64 .64 0 0 1-.8 .6zM161 294.6h1M309 290.6l.5-.1 .1 .8"/>
<path d="M309 298.2l.5-.1 .1 .8M309 290.5v.8M309 298.1v.8M309.3 286.8l.5-.1v.8M309.3 294.4l.5-.1v.8M309.3 286.7v.8M309.3 294.3v.8M309.6 290.6l.5-.1v.8M309.6 298.3l.5-.2v.8M309.8 286.8l.5-.1 .1 .8M309.8 294.5l.5-.2 .1 .8M324 286.2v1.1l.2 .2"/>
<path d="M324 290v1.1l.2 .2M324 293.8v1.1l.2 .2M324 297.7v1l.2 .2M309 305.8h.5l.1 .7M309 305.7v.8M309.3 302l.5-.1v.8M309.3 301.9v.8M309.6 305.9l.5-.1v.7M309.8 302.1l.5-.2 .1 .8M324 305.3v1.1l.2 .1M324 301.5v1.1l.2 .1M421.5 308.4v1.3h.6"/>
<path d="M466.6 309.7v1.3h.6M525.6 309.7v1.3h.6M570.7 311v1.3h.6M149.9 324.3h.8l-.4 .5 .3 .1v.6h-.7M150 332.1l.4-.2 .3 .4-.8 .9h.8M156.8 342.8l.7-.1v-.5l-.7-.1v1.3M174.3 342.7l.5-.1 .1 .8M236.9 346.5v1.1l.3 .2 .4-.2v-1.1M421.5 348.5l.6-.1v-.5l-.6-.1v1.3M466.6 349.7h.6v-.5l-.6-.1v1.3M466.9 349.7l.4 .7M525.6 349.7h.6l.1-.5-.7-.1v1.3"/>
<path d="M570.7 351h.6l.1-.5-.7-.1v1.2M571 351l.4 .6M16.5 362.4h.6l.1-.5-.7-.1v1.3M16.5 365l.6-.1 .1-.4-.7-.2v1.3M16.5 367.5h.6l.1-.5-.7-.1v1.2M16.5 370.1l.6-.1 .1-.5-.7-.1v1.3M16.5 377.7l.6-.1 .1-.4-.7-.2v1.3M17.9 372.6h.6l.1-.5-.7-.2v1.3M17.9 375.1h.6l.1-.5-.7-.1v1.3M158.7 378.3h.7M207.8 374.6l.5-.1 .2 .3-.8 1h.8M208.8 377.4l.4-.4v1.3"/>
<path d="M208.8 378.3h.7M16.5 380.2h.6l.1-.5-.7-.1v1.2M17.7 382.8l.6-.1 .1-.5-.7-.1v1.3M17.7 385.3h.6l.1-.5-.7-.2v1.3M381.8 391.8h1M158.9 400l.5-.1 .2 .3-.8 1h.8M158.9 402.8l.3-.4v1.3M158.9 403.7h.7M209 400l.5-.1 .2 .3-.8 1h.8M209 402.8l.3-.4v1.3M209 403.7h.7"/>
</g>
<g fill="#008400" stroke="#008400" stroke-width=".26">
<circle cx="245.7" cy="330.4" r=".51"/>
<circle cx="137.2" cy="44" r=".51"/>
<circle cx="38.7" cy="288.5" r=".51"/>
<circle cx="121.3" cy="291.6" r=".51"/>
<circle cx="121.3" cy="293.5" r=".51"/>
<circle cx="57.2" cy="378.6" r=".51"/>
<circle cx="29.8" cy="242.1" r=".51"/>
<circle cx="121.3" cy="295.4" r=".51"/>
<circle cx="138.4" cy="371" r=".51"/>
<circle cx="57.2" cy="381.2" r=".51"/>
<circle cx="57.2" cy="383.7" r=".51"/>
<circle cx="356.9" cy="360.8" r=".51"/>
<circle cx="273.7" cy="31.3" r=".51"/>
<circle cx="121.3" cy="297.3" r=".51"/>
<circle cx="44.5" cy="376.1" r=".51"/>
<circle cx="238.8" cy="59.9" r=".51"/>
<circle cx="167.6" cy="24.9" r=".51"/>
<circle cx="193.7" cy="368.5" r=".51"/>
<circle cx="44.5" cy="363.4" r=".51"/>
<circle cx="149.9" cy="44" r=".51"/>
<circle cx="295.9" cy="240.2" r=".51"/>
<circle cx="57.2" cy="365.9" r=".51"/>
<circle cx="160" cy="363.4" r=".51"/>
<circle cx="83.8" cy="28.7" r=".51"/>
<circle cx="57.2" cy="371" r=".51"/>
<circle cx="57.2" cy="363.4" r=".51"/>
<circle cx="237.5" cy="330.4" r=".51"/>
<circle cx="57.2" cy="386.2" r=".51"/>
<circle cx="57.2" cy="373.5" r=".51"/>
<circle cx="239.4" cy="314.5" r=".51"/>
<circle cx="248.3" cy="314.5" r=".51"/>
<circle cx="284.5" cy="240.2" r=".51"/>
<circle cx="414.7" cy="266.2" r=".51"/>
<circle cx="351.8" cy="111.3" r=".51"/>
<circle cx="518.8" cy="174.2" r=".51"/>
<circle cx="257.2" cy="322.1" r=".51"/>
<circle cx="248.3" cy="322.1" r=".51"/>
<circle cx="57.2" cy="376.1" r=".51"/>
<circle cx="149.9" cy="31.3" r=".51"/>
<circle cx="179.1" cy="36.4" r=".51"/>
<circle cx="292.1" cy="59.9" r=".51"/>
<circle cx="229.9" cy="59.9" r=".51"/>
<circle cx="144.8" cy="368.5" r=".51"/>
<circle cx="414.7" cy="339.3" r=".51"/>
<circle cx="57.2" cy="368.5" r=".51"/>
<circle cx="203.2" cy="226.9" r=".51"/>
<circle cx="120" cy="36.4" r=".51"/>
<circle cx="147.3" cy="255.4" r=".51"/>
<circle cx="122.6" cy="36.4" r=".51"/>
<circle cx="131.4" cy="386.2" r=".51"/>
<circle cx="141" cy="252.9" r=".51"/>
<circle cx="180.3" cy="386.2" r=".51"/>
<circle cx="273" cy="240.2" r=".51"/>
<circle cx="215.9" cy="226.9" r=".51"/>
<circle cx="187.3" cy="396.4" r=".51"/>
<circle cx="193.7" cy="393.9" r=".51"/>
<circle cx="262.9" cy="240.2" r=".51"/>
<circle cx="153" cy="240.2" r=".51"/>
<circle cx="147.3" cy="240.2" r=".51"/>
<circle cx="141" cy="240.2" r=".51"/>
<circle cx="138.4" cy="396.4" r=".51"/>
<circle cx="208.9" cy="363.4" r=".51"/>
<circle cx="26" cy="283.4" r=".51"/>
<circle cx="518.8" cy="134.8" r=".51"/>
<circle cx="208.9" cy="388.8" r=".51"/>
<circle cx="109.9" cy="239.6" r=".51"/>
<circle cx="384.2" cy="101.1" r=".51"/>
<circle cx="393.7" cy="98.6" r=".51"/>
<circle cx="221" cy="52.2" r=".51"/>
<circle cx="180.3" cy="360.8" r=".51"/>
<circle cx="187.3" cy="371" r=".51"/>
<circle cx="265.4" cy="52.2" r=".51"/>
<circle cx="518.8" cy="144.9" r=".51"/>
<circle cx="504.2" cy="101.8" r=".51"/>
<circle cx="414.7" cy="349.4" r=".51"/>
<circle cx="247.6" cy="59.9" r=".51"/>
<circle cx="256.5" cy="59.9" r=".51"/>
<circle cx="265.4" cy="59.9" r=".51"/>
<circle cx="131.4" cy="360.8" r=".51"/>
<circle cx="176.5" cy="343.7" r=".51"/>
<circle cx="274.3" cy="59.9" r=".51"/>
<circle cx="393.7" cy="108.8" r=".51"/>
<circle cx="162.6" cy="250.4" r=".51"/>
<circle cx="283.2" cy="52.2" r=".51"/>
<circle cx="274.3" cy="52.2" r=".51"/>
<circle cx="407" cy="98.6" r=".51"/>
<circle cx="190.5" cy="24.9" r=".51"/>
<circle cx="407" cy="108.8" r=".51"/>
<circle cx="256.5" cy="52.2" r=".51"/>
<circle cx="137.2" cy="31.3" r=".51"/>
<circle cx="283.2" cy="59.9" r=".51"/>
<circle cx="160" cy="388.8" r=".51"/>
<circle cx="247.6" cy="52.2" r=".51"/>
<circle cx="120" cy="31.3" r=".51"/>
<circle cx="238.8" cy="52.2" r=".51"/>
<circle cx="263.5" cy="31.3" r=".51"/>
<circle cx="144.8" cy="393.9" r=".51"/>
<circle cx="154.3" cy="247.8" r=".51"/>
<circle cx="229.9" cy="52.2" r=".51"/>
<circle cx="153" cy="247.8" r=".51"/>
<circle cx="50.8" cy="242.1" r=".51"/>
<circle cx="438.1" cy="98.6" r=".51"/>
<circle cx="518.8" cy="267.5" r=".51"/>
<circle cx="563.9" cy="188.1" r=".51"/>
<circle cx="419.1" cy="19.9" r=".51"/>
<circle cx="563.9" cy="180.5" r=".51"/>
<circle cx="563.9" cy="178" r=".51"/>
<circle cx="563.9" cy="175.4" r=".51"/>
<circle cx="535.9" cy="185.6" r=".51"/>
<circle cx="563.9" cy="231.9" r=".51"/>
<circle cx="417.8" cy="98.6" r=".51"/>
<circle cx="391.2" cy="29.4" r=".51"/>
<circle cx="563.9" cy="224.3" r=".51"/>
<circle cx="74.9" cy="298.6" r=".51"/>
<circle cx="563.9" cy="221.8" r=".51"/>
<circle cx="535.9" cy="146.2" r=".51"/>
<circle cx="563.9" cy="219.2" r=".51"/>
<circle cx="67.3" cy="30.6" r=".51"/>
<circle cx="535.9" cy="229.4" r=".51"/>
<circle cx="428" cy="108.8" r=".51"/>
<circle cx="563.9" cy="271.3" r=".51"/>
<circle cx="417.8" cy="108.8" r=".51"/>
<circle cx="563.9" cy="263.7" r=".51"/>
<circle cx="563.9" cy="261.2" r=".51"/>
<circle cx="518.8" cy="350.7" r=".51"/>
<circle cx="563.9" cy="258.6" r=".51"/>
<circle cx="372.7" cy="133.5" r=".51"/>
<circle cx="535.9" cy="268.8" r=".51"/>
<circle cx="563.9" cy="315.1" r=".51"/>
<circle cx="47.6" cy="48.4" r=".51"/>
<circle cx="476.9" cy="134.8" r=".51"/>
<circle cx="401.3" cy="37" r=".51"/>
<circle cx="361.9" cy="29.4" r=".51"/>
<circle cx="246.4" cy="391.3" r=".51"/>
<circle cx="26.7" cy="85.3" r=".51"/>
<circle cx="47.6" cy="30.6" r=".51"/>
<circle cx="351.8" cy="29.4" r=".51"/>
<circle cx="524.5" cy="101.8" r=".51"/>
<circle cx="514.3" cy="101.8" r=".51"/>
<circle cx="524.5" cy="109.4" r=".51"/>
<circle cx="534" cy="109.4" r=".51"/>
<circle cx="395.6" cy="68.1" r=".51"/>
<circle cx="395.6" cy="77" r=".51"/>
<circle cx="416.6" cy="59.2" r=".51"/>
<circle cx="21.6" cy="242.1" r=".51"/>
<circle cx="42.5" cy="242.1" r=".51"/>
<circle cx="459.1" cy="26.2" r=".51"/>
<circle cx="389.9" cy="25.6" r=".51"/>
<circle cx="414.7" cy="299.9" r=".51"/>
<circle cx="446.4" cy="67.5" r=".51"/>
<circle cx="563.9" cy="148.8" r=".51"/>
<circle cx="563.9" cy="141.1" r=".51"/>
<circle cx="563.9" cy="138.6" r=".51"/>
<circle cx="407.7" cy="19.9" r=".51"/>
<circle cx="563.9" cy="136.1" r=".51"/>
<circle cx="419.1" cy="40.2" r=".51"/>
<circle cx="459.7" cy="139.9" r=".51"/>
<circle cx="459.7" cy="306.2" r=".51"/>
<circle cx="459.7" cy="303.7" r=".51"/>
<circle cx="431.8" cy="144.9" r=".51"/>
<circle cx="459.7" cy="301.2" r=".51"/>
<circle cx="518.8" cy="340.5" r=".51"/>
<circle cx="431.8" cy="311.3" r=".51"/>
<circle cx="459.7" cy="147.5" r=".51"/>
<circle cx="459.7" cy="270" r=".51"/>
<circle cx="83.8" cy="21.1" r=".51"/>
<circle cx="459.7" cy="134.8" r=".51"/>
<circle cx="459.7" cy="262.4" r=".51"/>
<circle cx="459.7" cy="137.3" r=".51"/>
<circle cx="459.7" cy="259.9" r=".51"/>
<circle cx="109.2" cy="237" r=".51"/>
<circle cx="459.7" cy="257.3" r=".51"/>
<circle cx="431.8" cy="184.3" r=".51"/>
<circle cx="431.8" cy="267.5" r=".51"/>
<circle cx="459.7" cy="230.7" r=".51"/>
<circle cx="459.7" cy="174.2" r=".51"/>
<circle cx="459.7" cy="223.1" r=".51"/>
<circle cx="459.7" cy="176.7" r=".51"/>
<circle cx="459.7" cy="220.5" r=".51"/>
<circle cx="518.8" cy="311.3" r=".51"/>
<circle cx="459.7" cy="218" r=".51"/>
<circle cx="459.7" cy="179.2" r=".51"/>
<circle cx="431.8" cy="228.1" r=".51"/>
<circle cx="372.1" cy="98.6" r=".51"/>
<circle cx="563.9" cy="307.5" r=".51"/>
<circle cx="563.9" cy="305" r=".51"/>
<circle cx="372.1" cy="172.9" r=".51"/>
<circle cx="414.7" cy="256.1" r=".51"/>
<circle cx="563.9" cy="302.4" r=".51"/>
<circle cx="372.7" cy="216.7" r=".51"/>
<circle cx="535.9" cy="312.6" r=".51"/>
<circle cx="563.9" cy="354.5" r=".51"/>
<circle cx="372.1" cy="256.1" r=".51"/>
<circle cx="563.9" cy="346.9" r=".51"/>
<circle cx="563.9" cy="344.3" r=".51"/>
<circle cx="343.5" cy="103.7" r=".51"/>
<circle cx="563.9" cy="341.8" r=".51"/>
<circle cx="361.9" cy="37" r=".51"/>
<circle cx="535.9" cy="352" r=".51"/>
<circle cx="372.1" cy="101.1" r=".51"/>
<circle cx="459.7" cy="353.2" r=".51"/>
<circle cx="372.7" cy="299.9" r=".51"/>
<circle cx="459.7" cy="345.6" r=".51"/>
<circle cx="459.7" cy="343.1" r=".51"/>
<circle cx="518.8" cy="301.2" r=".51"/>
<circle cx="459.7" cy="340.5" r=".51"/>
<circle cx="431.8" cy="350.7" r=".51"/>
<circle cx="414.7" cy="226.9" r=".51"/>
<circle cx="459.7" cy="313.9" r=".51"/>
<circle cx="372.1" cy="339.3" r=".51"/>
<circle cx="518.8" cy="218" r=".51"/>
<circle cx="44.5" cy="378.6" r=".51"/>
<circle cx="274.3" cy="401.5" r=".51"/>
<circle cx="271.8" cy="401.5" r=".51"/>
<circle cx="459.7" cy="186.9" r=".51"/>
<circle cx="44.5" cy="373.5" r=".51"/>
<circle cx="269.2" cy="320.2" r=".51"/>
<circle cx="271.8" cy="320.2" r=".51"/>
<circle cx="44.5" cy="371" r=".51"/>
<circle cx="199.4" cy="66.8" r=".51"/>
<circle cx="414.7" cy="310" r=".51"/>
<circle cx="518.8" cy="184.3" r=".51"/>
<circle cx="44.5" cy="368.5" r=".51"/>
<circle cx="118.1" cy="388.8" r=".51"/>
<circle cx="414.7" cy="143.7" r=".51"/>
<circle cx="118.1" cy="371" r=".51"/>
<circle cx="514.3" cy="109.4" r=".51"/>
<circle cx="118.1" cy="373.5" r=".51"/>
<circle cx="118.1" cy="376.1" r=".51"/>
<circle cx="44.5" cy="365.9" r=".51"/>
<circle cx="118.1" cy="381.2" r=".51"/>
<circle cx="184.1" cy="66.8" r=".51"/>
<circle cx="123.2" cy="66.8" r=".51"/>
<circle cx="466.7" cy="85.9" r=".51"/>
<circle cx="135.9" cy="66.8" r=".51"/>
<circle cx="447.7" cy="21.1" r=".51"/>
<circle cx="414.7" cy="216.7" r=".51"/>
<circle cx="161.3" cy="66.8" r=".51"/>
<circle cx="458.5" cy="78.3" r=".51"/>
<circle cx="168.9" cy="66.8" r=".51"/>
<circle cx="176.5" cy="66.8" r=".51"/>
<circle cx="118.1" cy="378.6" r=".51"/>
<circle cx="191.8" cy="66.8" r=".51"/>
<circle cx="66.7" cy="298.6" r=".51"/>
<circle cx="44.5" cy="354.5" r=".51"/>
<circle cx="374.6" cy="101.1" r=".51"/>
<circle cx="414.7" cy="133.5" r=".51"/>
<circle cx="238.1" cy="247.8" r=".51"/>
<circle cx="238.1" cy="245.3" r=".51"/>
<circle cx="44.5" cy="383.7" r=".51"/>
<circle cx="44.5" cy="381.2" r=".51"/>
<circle cx="518.8" cy="228.1" r=".51"/>
<circle cx="151.8" cy="388.8" r=".51"/>
<circle cx="151.8" cy="363.4" r=".51"/>
<circle cx="414.7" cy="172.9" r=".51"/>
<circle cx="22.2" cy="77.6" r=".51"/>
<circle cx="384.2" cy="108.8" r=".51"/>
<circle cx="476.2" cy="340.5" r=".51"/>
<circle cx="31.1" cy="77.6" r=".51"/>
<circle cx="476.9" cy="301.2" r=".51"/>
<circle cx="466.7" cy="67.5" r=".51"/>
<circle cx="105.4" cy="386.2" r=".51"/>
<circle cx="47.6" cy="39.5" r=".51"/>
<circle cx="476.2" cy="257.3" r=".51"/>
<circle cx="476.9" cy="218" r=".51"/>
<circle cx="478.2" cy="85.9" r=".51"/>
<circle cx="476.2" cy="174.2" r=".51"/>
<circle cx="446.4" cy="59.9" r=".51"/>
<circle cx="414.7" cy="183" r=".51"/>
<circle cx="518.8" cy="257.3" r=".51"/>
<circle cx="105.4" cy="378.6" r=".51"/>
<circle cx="118.1" cy="383.7" r=".51"/>
<circle cx="118.1" cy="386.2" r=".51"/>
<circle cx="31.7" cy="107.5" r=".51"/>
<circle cx="105.4" cy="371" r=".51"/>
<circle cx="105.4" cy="373.5" r=".51"/>
<circle cx="105.4" cy="376.1" r=".51"/>
<circle cx="105.4" cy="362.1" r=".51"/>
<circle cx="200.7" cy="388.8" r=".51"/>
<circle cx="105.4" cy="381.2" r=".51"/>
<circle cx="351.8" cy="103.7" r=".51"/>
<circle cx="21.6" cy="99.9" r=".51"/>
<circle cx="105.4" cy="383.7" r=".51"/>
<circle cx="200.7" cy="363.4" r=".51"/>
</g>
<g fill="none" stroke="#000084" stroke-width=".26">
<path d="M361.3 25l1.3 1.2M362.6 25l-1.3 1.2M457.2 30.7l1.2 1.2M458.4 30.7l-1.2 1.2M466.1 51.6l1.2 1.2M467.3 51.6l-1.2 1.2M447.1 80.2l1.2 1.2M448.3 80.2l-1.2 1.2M162.6 237l1.2 1.3M163.8 237l-1.2 1.3M106.7 299.9l1.2 1.2M107.9 299.9l-1.2 1.2"/>
<path d="M158.8 298.6l1.2 1.3M160 298.6l-1.2 1.3M199.4 294.8l1.2 1.3M200.6 294.8l-1.2 1.3M231.2 294.8l1.2 1.3M232.4 294.8l-1.2 1.3M262.9 294.8l1.2 1.3M264.1 294.8l-1.2 1.3M294.7 294.8l1.2 1.3M295.9 294.8l-1.2 1.3M96.5 305l1.3 1.2M97.8 305l-1.3 1.2"/>
<path d="M158.8 302.5l1.2 1.2M158.8 300.5l1.2 1.3M160 302.5l-1.2 1.2M160 300.5l-1.2 1.3M182.3 320.2l1.2 1.3M183.5 320.2l-1.2 1.3M341 329.8l1.2 1.2M341 339.9l1.2 1.2M341 337.4l1.2 1.2M341 334.8l1.2 1.3M341 332.3l1.2 1.2M342.2 329.8l-1.2 1.2"/>
<path d="M342.2 339.9l-1.2 1.2M342.2 337.4l-1.2 1.2M342.2 334.8l-1.2 1.3M342.2 332.3l-1.2 1.2M225.5 343.1l1.2 1.2M226.7 343.1l-1.2 1.2M245.8 355.2l1.2 1.2M245.8 352.6l1.2 1.2M247 355.2l-1.2 1.2M247 352.6l-1.2 1.2M341 342.5l1.2 1.2M341 355.2l1.2 1.2"/>
<path d="M341 352.6l1.2 1.2M342.2 342.5l-1.2 1.2M342.2 355.2l-1.2 1.2M342.2 352.6l-1.2 1.2M245.8 360.2l1.2 1.3M245.8 362.8l1.2 1.2M245.8 375.5l1.2 1.2M245.8 370.4l1.2 1.2M245.8 378l1.2 1.2M245.8 367.9l1.2 1.2M247 360.2l-1.2 1.3M247 362.8l-1.2 1.2"/>
<path d="M247 375.5l-1.2 1.2M247 370.4l-1.2 1.2M247 378l-1.2 1.2M247 367.9l-1.2 1.2M341 367.9l1.2 1.2M341 370.4l1.2 1.2M341 372.9l1.2 1.3M341 375.5l1.2 1.2M341 378l1.2 1.2M342.2 367.9l-1.2 1.2M342.2 370.4l-1.2 1.2M342.2 372.9l-1.2 1.3"/>
<path d="M342.2 375.5l-1.2 1.2M342.2 378l-1.2 1.2M398.2 379.9l1.2 1.2M399.4 379.9l-1.2 1.2M341 380.6l1.2 1.2M341 388.2l1.2 1.2M341 390.7l1.2 1.2M342.2 380.6l-1.2 1.2M342.2 388.2l-1.2 1.2M342.2 390.7l-1.2 1.2M362.6 399.6l1.2 1.2M363.8 399.6l-1.2 1.2"/>
</g>
<use href="#words"/>
</svg>
